VERSION 5.8 ;
BUSBITCHARS "[]" ;
DIVIDERCHAR "/" ;
UNITS
    DATABASE MICRONS 1000 ;
END UNITS

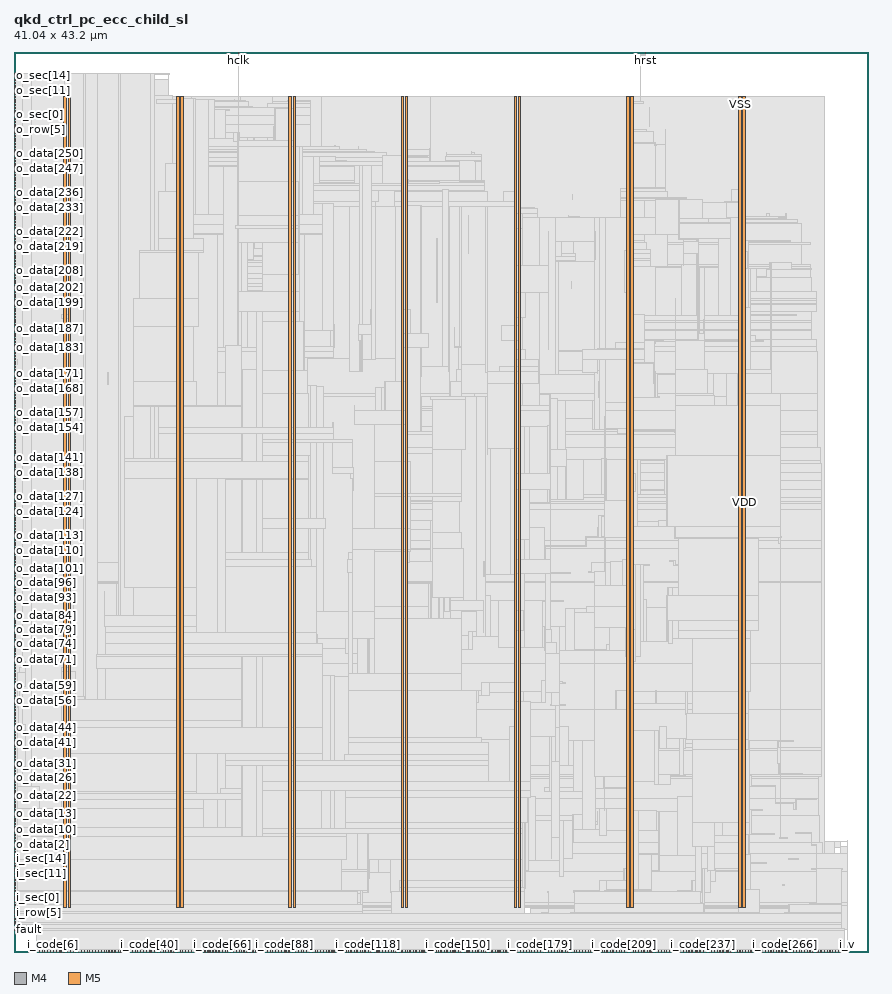
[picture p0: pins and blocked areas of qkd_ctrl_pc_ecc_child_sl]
MACRO qkd_ctrl_pc_ecc_child_sl
  FOREIGN qkd_ctrl_pc_ecc_child_sl 0 0 ;
  CLASS BLOCK ;
  SIZE 41.04 BY 43.2 ;
  PIN fault
    DIRECTION OUTPUT ;
    USE SIGNAL ;
    PORT
      LAYER M4 ;
        RECT  0 1.056 0.084 1.08 ;
    END
  END fault
  PIN hclk
    DIRECTION INPUT ;
    USE SIGNAL ;
    PORT
      LAYER M5 ;
        RECT  10.752 43.116 10.776 43.2 ;
    END
  END hclk
  PIN hrst
    DIRECTION INPUT ;
    USE SIGNAL ;
    PORT
      LAYER M5 ;
        RECT  30.288 43.116 30.312 43.2 ;
    END
  END hrst
  PIN i_code[0]
    DIRECTION INPUT ;
    USE SIGNAL ;
    PORT
      LAYER M5 ;
        RECT  1.056 0 1.08 0.084 ;
    END
  END i_code[0]
  PIN i_code[100]
    DIRECTION INPUT ;
    USE SIGNAL ;
    PORT
      LAYER M5 ;
        RECT  14.544 0 14.568 0.084 ;
    END
  END i_code[100]
  PIN i_code[101]
    DIRECTION INPUT ;
    USE SIGNAL ;
    PORT
      LAYER M5 ;
        RECT  14.688 0 14.712 0.084 ;
    END
  END i_code[101]
  PIN i_code[102]
    DIRECTION INPUT ;
    USE SIGNAL ;
    PORT
      LAYER M5 ;
        RECT  14.832 0 14.856 0.084 ;
    END
  END i_code[102]
  PIN i_code[103]
    DIRECTION INPUT ;
    USE SIGNAL ;
    PORT
      LAYER M5 ;
        RECT  14.976 0 15 0.084 ;
    END
  END i_code[103]
  PIN i_code[104]
    DIRECTION INPUT ;
    USE SIGNAL ;
    PORT
      LAYER M5 ;
        RECT  15.12 0 15.144 0.084 ;
    END
  END i_code[104]
  PIN i_code[105]
    DIRECTION INPUT ;
    USE SIGNAL ;
    PORT
      LAYER M5 ;
        RECT  15.264 0 15.288 0.084 ;
    END
  END i_code[105]
  PIN i_code[106]
    DIRECTION INPUT ;
    USE SIGNAL ;
    PORT
      LAYER M5 ;
        RECT  15.36 0 15.384 0.084 ;
    END
  END i_code[106]
  PIN i_code[107]
    DIRECTION INPUT ;
    USE SIGNAL ;
    PORT
      LAYER M5 ;
        RECT  15.504 0 15.528 0.084 ;
    END
  END i_code[107]
  PIN i_code[108]
    DIRECTION INPUT ;
    USE SIGNAL ;
    PORT
      LAYER M5 ;
        RECT  15.648 0 15.672 0.084 ;
    END
  END i_code[108]
  PIN i_code[109]
    DIRECTION INPUT ;
    USE SIGNAL ;
    PORT
      LAYER M5 ;
        RECT  15.792 0 15.816 0.084 ;
    END
  END i_code[109]
  PIN i_code[10]
    DIRECTION INPUT ;
    USE SIGNAL ;
    PORT
      LAYER M5 ;
        RECT  2.4 0 2.424 0.084 ;
    END
  END i_code[10]
  PIN i_code[110]
    DIRECTION INPUT ;
    USE SIGNAL ;
    PORT
      LAYER M5 ;
        RECT  15.936 0 15.96 0.084 ;
    END
  END i_code[110]
  PIN i_code[111]
    DIRECTION INPUT ;
    USE SIGNAL ;
    PORT
      LAYER M5 ;
        RECT  16.032 0 16.056 0.084 ;
    END
  END i_code[111]
  PIN i_code[112]
    DIRECTION INPUT ;
    USE SIGNAL ;
    PORT
      LAYER M5 ;
        RECT  16.176 0 16.2 0.084 ;
    END
  END i_code[112]
  PIN i_code[113]
    DIRECTION INPUT ;
    USE SIGNAL ;
    PORT
      LAYER M5 ;
        RECT  16.32 0 16.344 0.084 ;
    END
  END i_code[113]
  PIN i_code[114]
    DIRECTION INPUT ;
    USE SIGNAL ;
    PORT
      LAYER M5 ;
        RECT  16.464 0 16.488 0.084 ;
    END
  END i_code[114]
  PIN i_code[115]
    DIRECTION INPUT ;
    USE SIGNAL ;
    PORT
      LAYER M5 ;
        RECT  16.608 0 16.632 0.084 ;
    END
  END i_code[115]
  PIN i_code[116]
    DIRECTION INPUT ;
    USE SIGNAL ;
    PORT
      LAYER M5 ;
        RECT  16.704 0 16.728 0.084 ;
    END
  END i_code[116]
  PIN i_code[117]
    DIRECTION INPUT ;
    USE SIGNAL ;
    PORT
      LAYER M5 ;
        RECT  16.848 0 16.872 0.084 ;
    END
  END i_code[117]
  PIN i_code[118]
    DIRECTION INPUT ;
    USE SIGNAL ;
    PORT
      LAYER M5 ;
        RECT  16.992 0 17.016 0.084 ;
    END
  END i_code[118]
  PIN i_code[119]
    DIRECTION INPUT ;
    USE SIGNAL ;
    PORT
      LAYER M5 ;
        RECT  17.136 0 17.16 0.084 ;
    END
  END i_code[119]
  PIN i_code[11]
    DIRECTION INPUT ;
    USE SIGNAL ;
    PORT
      LAYER M5 ;
        RECT  2.544 0 2.568 0.084 ;
    END
  END i_code[11]
  PIN i_code[120]
    DIRECTION INPUT ;
    USE SIGNAL ;
    PORT
      LAYER M5 ;
        RECT  17.28 0 17.304 0.084 ;
    END
  END i_code[120]
  PIN i_code[121]
    DIRECTION INPUT ;
    USE SIGNAL ;
    PORT
      LAYER M5 ;
        RECT  17.424 0 17.448 0.084 ;
    END
  END i_code[121]
  PIN i_code[122]
    DIRECTION INPUT ;
    USE SIGNAL ;
    PORT
      LAYER M5 ;
        RECT  17.52 0 17.544 0.084 ;
    END
  END i_code[122]
  PIN i_code[123]
    DIRECTION INPUT ;
    USE SIGNAL ;
    PORT
      LAYER M5 ;
        RECT  17.664 0 17.688 0.084 ;
    END
  END i_code[123]
  PIN i_code[124]
    DIRECTION INPUT ;
    USE SIGNAL ;
    PORT
      LAYER M5 ;
        RECT  17.808 0 17.832 0.084 ;
    END
  END i_code[124]
  PIN i_code[125]
    DIRECTION INPUT ;
    USE SIGNAL ;
    PORT
      LAYER M5 ;
        RECT  17.952 0 17.976 0.084 ;
    END
  END i_code[125]
  PIN i_code[126]
    DIRECTION INPUT ;
    USE SIGNAL ;
    PORT
      LAYER M5 ;
        RECT  18.096 0 18.12 0.084 ;
    END
  END i_code[126]
  PIN i_code[127]
    DIRECTION INPUT ;
    USE SIGNAL ;
    PORT
      LAYER M5 ;
        RECT  18.192 0 18.216 0.084 ;
    END
  END i_code[127]
  PIN i_code[128]
    DIRECTION INPUT ;
    USE SIGNAL ;
    PORT
      LAYER M5 ;
        RECT  18.336 0 18.36 0.084 ;
    END
  END i_code[128]
  PIN i_code[129]
    DIRECTION INPUT ;
    USE SIGNAL ;
    PORT
      LAYER M5 ;
        RECT  18.48 0 18.504 0.084 ;
    END
  END i_code[129]
  PIN i_code[12]
    DIRECTION INPUT ;
    USE SIGNAL ;
    PORT
      LAYER M5 ;
        RECT  2.688 0 2.712 0.084 ;
    END
  END i_code[12]
  PIN i_code[130]
    DIRECTION INPUT ;
    USE SIGNAL ;
    PORT
      LAYER M5 ;
        RECT  18.624 0 18.648 0.084 ;
    END
  END i_code[130]
  PIN i_code[131]
    DIRECTION INPUT ;
    USE SIGNAL ;
    PORT
      LAYER M5 ;
        RECT  18.768 0 18.792 0.084 ;
    END
  END i_code[131]
  PIN i_code[132]
    DIRECTION INPUT ;
    USE SIGNAL ;
    PORT
      LAYER M5 ;
        RECT  18.864 0 18.888 0.084 ;
    END
  END i_code[132]
  PIN i_code[133]
    DIRECTION INPUT ;
    USE SIGNAL ;
    PORT
      LAYER M5 ;
        RECT  19.008 0 19.032 0.084 ;
    END
  END i_code[133]
  PIN i_code[134]
    DIRECTION INPUT ;
    USE SIGNAL ;
    PORT
      LAYER M5 ;
        RECT  19.152 0 19.176 0.084 ;
    END
  END i_code[134]
  PIN i_code[135]
    DIRECTION INPUT ;
    USE SIGNAL ;
    PORT
      LAYER M5 ;
        RECT  19.296 0 19.32 0.084 ;
    END
  END i_code[135]
  PIN i_code[136]
    DIRECTION INPUT ;
    USE SIGNAL ;
    PORT
      LAYER M5 ;
        RECT  19.44 0 19.464 0.084 ;
    END
  END i_code[136]
  PIN i_code[137]
    DIRECTION INPUT ;
    USE SIGNAL ;
    PORT
      LAYER M5 ;
        RECT  19.584 0 19.608 0.084 ;
    END
  END i_code[137]
  PIN i_code[138]
    DIRECTION INPUT ;
    USE SIGNAL ;
    PORT
      LAYER M5 ;
        RECT  19.68 0 19.704 0.084 ;
    END
  END i_code[138]
  PIN i_code[139]
    DIRECTION INPUT ;
    USE SIGNAL ;
    PORT
      LAYER M5 ;
        RECT  19.824 0 19.848 0.084 ;
    END
  END i_code[139]
  PIN i_code[13]
    DIRECTION INPUT ;
    USE SIGNAL ;
    PORT
      LAYER M5 ;
        RECT  2.832 0 2.856 0.084 ;
    END
  END i_code[13]
  PIN i_code[140]
    DIRECTION INPUT ;
    USE SIGNAL ;
    PORT
      LAYER M5 ;
        RECT  19.968 0 19.992 0.084 ;
    END
  END i_code[140]
  PIN i_code[141]
    DIRECTION INPUT ;
    USE SIGNAL ;
    PORT
      LAYER M5 ;
        RECT  20.112 0 20.136 0.084 ;
    END
  END i_code[141]
  PIN i_code[142]
    DIRECTION INPUT ;
    USE SIGNAL ;
    PORT
      LAYER M5 ;
        RECT  20.256 0 20.28 0.084 ;
    END
  END i_code[142]
  PIN i_code[143]
    DIRECTION INPUT ;
    USE SIGNAL ;
    PORT
      LAYER M5 ;
        RECT  20.352 0 20.376 0.084 ;
    END
  END i_code[143]
  PIN i_code[144]
    DIRECTION INPUT ;
    USE SIGNAL ;
    PORT
      LAYER M5 ;
        RECT  20.496 0 20.52 0.084 ;
    END
  END i_code[144]
  PIN i_code[145]
    DIRECTION INPUT ;
    USE SIGNAL ;
    PORT
      LAYER M5 ;
        RECT  20.64 0 20.664 0.084 ;
    END
  END i_code[145]
  PIN i_code[146]
    DIRECTION INPUT ;
    USE SIGNAL ;
    PORT
      LAYER M5 ;
        RECT  20.784 0 20.808 0.084 ;
    END
  END i_code[146]
  PIN i_code[147]
    DIRECTION INPUT ;
    USE SIGNAL ;
    PORT
      LAYER M5 ;
        RECT  20.928 0 20.952 0.084 ;
    END
  END i_code[147]
  PIN i_code[148]
    DIRECTION INPUT ;
    USE SIGNAL ;
    PORT
      LAYER M5 ;
        RECT  21.072 0 21.096 0.084 ;
    END
  END i_code[148]
  PIN i_code[149]
    DIRECTION INPUT ;
    USE SIGNAL ;
    PORT
      LAYER M5 ;
        RECT  21.168 0 21.192 0.084 ;
    END
  END i_code[149]
  PIN i_code[14]
    DIRECTION INPUT ;
    USE SIGNAL ;
    PORT
      LAYER M5 ;
        RECT  2.928 0 2.952 0.084 ;
    END
  END i_code[14]
  PIN i_code[150]
    DIRECTION INPUT ;
    USE SIGNAL ;
    PORT
      LAYER M5 ;
        RECT  21.312 0 21.336 0.084 ;
    END
  END i_code[150]
  PIN i_code[151]
    DIRECTION INPUT ;
    USE SIGNAL ;
    PORT
      LAYER M5 ;
        RECT  21.456 0 21.48 0.084 ;
    END
  END i_code[151]
  PIN i_code[152]
    DIRECTION INPUT ;
    USE SIGNAL ;
    PORT
      LAYER M5 ;
        RECT  21.6 0 21.624 0.084 ;
    END
  END i_code[152]
  PIN i_code[153]
    DIRECTION INPUT ;
    USE SIGNAL ;
    PORT
      LAYER M5 ;
        RECT  21.744 0 21.768 0.084 ;
    END
  END i_code[153]
  PIN i_code[154]
    DIRECTION INPUT ;
    USE SIGNAL ;
    PORT
      LAYER M5 ;
        RECT  21.84 0 21.864 0.084 ;
    END
  END i_code[154]
  PIN i_code[155]
    DIRECTION INPUT ;
    USE SIGNAL ;
    PORT
      LAYER M5 ;
        RECT  21.984 0 22.008 0.084 ;
    END
  END i_code[155]
  PIN i_code[156]
    DIRECTION INPUT ;
    USE SIGNAL ;
    PORT
      LAYER M5 ;
        RECT  22.128 0 22.152 0.084 ;
    END
  END i_code[156]
  PIN i_code[157]
    DIRECTION INPUT ;
    USE SIGNAL ;
    PORT
      LAYER M5 ;
        RECT  22.272 0 22.296 0.084 ;
    END
  END i_code[157]
  PIN i_code[158]
    DIRECTION INPUT ;
    USE SIGNAL ;
    PORT
      LAYER M5 ;
        RECT  22.416 0 22.44 0.084 ;
    END
  END i_code[158]
  PIN i_code[159]
    DIRECTION INPUT ;
    USE SIGNAL ;
    PORT
      LAYER M5 ;
        RECT  22.512 0 22.536 0.084 ;
    END
  END i_code[159]
  PIN i_code[15]
    DIRECTION INPUT ;
    USE SIGNAL ;
    PORT
      LAYER M5 ;
        RECT  3.072 0 3.096 0.084 ;
    END
  END i_code[15]
  PIN i_code[160]
    DIRECTION INPUT ;
    USE SIGNAL ;
    PORT
      LAYER M5 ;
        RECT  22.656 0 22.68 0.084 ;
    END
  END i_code[160]
  PIN i_code[161]
    DIRECTION INPUT ;
    USE SIGNAL ;
    PORT
      LAYER M5 ;
        RECT  22.8 0 22.824 0.084 ;
    END
  END i_code[161]
  PIN i_code[162]
    DIRECTION INPUT ;
    USE SIGNAL ;
    PORT
      LAYER M5 ;
        RECT  22.944 0 22.968 0.084 ;
    END
  END i_code[162]
  PIN i_code[163]
    DIRECTION INPUT ;
    USE SIGNAL ;
    PORT
      LAYER M5 ;
        RECT  23.088 0 23.112 0.084 ;
    END
  END i_code[163]
  PIN i_code[164]
    DIRECTION INPUT ;
    USE SIGNAL ;
    PORT
      LAYER M5 ;
        RECT  23.232 0 23.256 0.084 ;
    END
  END i_code[164]
  PIN i_code[165]
    DIRECTION INPUT ;
    USE SIGNAL ;
    PORT
      LAYER M5 ;
        RECT  23.328 0 23.352 0.084 ;
    END
  END i_code[165]
  PIN i_code[166]
    DIRECTION INPUT ;
    USE SIGNAL ;
    PORT
      LAYER M5 ;
        RECT  23.472 0 23.496 0.084 ;
    END
  END i_code[166]
  PIN i_code[167]
    DIRECTION INPUT ;
    USE SIGNAL ;
    PORT
      LAYER M5 ;
        RECT  23.616 0 23.64 0.084 ;
    END
  END i_code[167]
  PIN i_code[168]
    DIRECTION INPUT ;
    USE SIGNAL ;
    PORT
      LAYER M5 ;
        RECT  23.76 0 23.784 0.084 ;
    END
  END i_code[168]
  PIN i_code[169]
    DIRECTION INPUT ;
    USE SIGNAL ;
    PORT
      LAYER M5 ;
        RECT  23.904 0 23.928 0.084 ;
    END
  END i_code[169]
  PIN i_code[16]
    DIRECTION INPUT ;
    USE SIGNAL ;
    PORT
      LAYER M5 ;
        RECT  3.216 0 3.24 0.084 ;
    END
  END i_code[16]
  PIN i_code[170]
    DIRECTION INPUT ;
    USE SIGNAL ;
    PORT
      LAYER M5 ;
        RECT  24 0 24.024 0.084 ;
    END
  END i_code[170]
  PIN i_code[171]
    DIRECTION INPUT ;
    USE SIGNAL ;
    PORT
      LAYER M5 ;
        RECT  24.144 0 24.168 0.084 ;
    END
  END i_code[171]
  PIN i_code[172]
    DIRECTION INPUT ;
    USE SIGNAL ;
    PORT
      LAYER M5 ;
        RECT  24.288 0 24.312 0.084 ;
    END
  END i_code[172]
  PIN i_code[173]
    DIRECTION INPUT ;
    USE SIGNAL ;
    PORT
      LAYER M5 ;
        RECT  24.432 0 24.456 0.084 ;
    END
  END i_code[173]
  PIN i_code[174]
    DIRECTION INPUT ;
    USE SIGNAL ;
    PORT
      LAYER M5 ;
        RECT  24.576 0 24.6 0.084 ;
    END
  END i_code[174]
  PIN i_code[175]
    DIRECTION INPUT ;
    USE SIGNAL ;
    PORT
      LAYER M5 ;
        RECT  24.72 0 24.744 0.084 ;
    END
  END i_code[175]
  PIN i_code[176]
    DIRECTION INPUT ;
    USE SIGNAL ;
    PORT
      LAYER M5 ;
        RECT  24.816 0 24.84 0.084 ;
    END
  END i_code[176]
  PIN i_code[177]
    DIRECTION INPUT ;
    USE SIGNAL ;
    PORT
      LAYER M5 ;
        RECT  24.96 0 24.984 0.084 ;
    END
  END i_code[177]
  PIN i_code[178]
    DIRECTION INPUT ;
    USE SIGNAL ;
    PORT
      LAYER M5 ;
        RECT  25.104 0 25.128 0.084 ;
    END
  END i_code[178]
  PIN i_code[179]
    DIRECTION INPUT ;
    USE SIGNAL ;
    PORT
      LAYER M5 ;
        RECT  25.248 0 25.272 0.084 ;
    END
  END i_code[179]
  PIN i_code[17]
    DIRECTION INPUT ;
    USE SIGNAL ;
    PORT
      LAYER M5 ;
        RECT  3.36 0 3.384 0.084 ;
    END
  END i_code[17]
  PIN i_code[180]
    DIRECTION INPUT ;
    USE SIGNAL ;
    PORT
      LAYER M5 ;
        RECT  25.392 0 25.416 0.084 ;
    END
  END i_code[180]
  PIN i_code[181]
    DIRECTION INPUT ;
    USE SIGNAL ;
    PORT
      LAYER M5 ;
        RECT  25.488 0 25.512 0.084 ;
    END
  END i_code[181]
  PIN i_code[182]
    DIRECTION INPUT ;
    USE SIGNAL ;
    PORT
      LAYER M5 ;
        RECT  25.632 0 25.656 0.084 ;
    END
  END i_code[182]
  PIN i_code[183]
    DIRECTION INPUT ;
    USE SIGNAL ;
    PORT
      LAYER M5 ;
        RECT  25.776 0 25.8 0.084 ;
    END
  END i_code[183]
  PIN i_code[184]
    DIRECTION INPUT ;
    USE SIGNAL ;
    PORT
      LAYER M5 ;
        RECT  25.92 0 25.944 0.084 ;
    END
  END i_code[184]
  PIN i_code[185]
    DIRECTION INPUT ;
    USE SIGNAL ;
    PORT
      LAYER M5 ;
        RECT  26.064 0 26.088 0.084 ;
    END
  END i_code[185]
  PIN i_code[186]
    DIRECTION INPUT ;
    USE SIGNAL ;
    PORT
      LAYER M5 ;
        RECT  26.16 0 26.184 0.084 ;
    END
  END i_code[186]
  PIN i_code[187]
    DIRECTION INPUT ;
    USE SIGNAL ;
    PORT
      LAYER M5 ;
        RECT  26.304 0 26.328 0.084 ;
    END
  END i_code[187]
  PIN i_code[188]
    DIRECTION INPUT ;
    USE SIGNAL ;
    PORT
      LAYER M5 ;
        RECT  26.448 0 26.472 0.084 ;
    END
  END i_code[188]
  PIN i_code[189]
    DIRECTION INPUT ;
    USE SIGNAL ;
    PORT
      LAYER M5 ;
        RECT  26.592 0 26.616 0.084 ;
    END
  END i_code[189]
  PIN i_code[18]
    DIRECTION INPUT ;
    USE SIGNAL ;
    PORT
      LAYER M5 ;
        RECT  3.504 0 3.528 0.084 ;
    END
  END i_code[18]
  PIN i_code[190]
    DIRECTION INPUT ;
    USE SIGNAL ;
    PORT
      LAYER M5 ;
        RECT  26.736 0 26.76 0.084 ;
    END
  END i_code[190]
  PIN i_code[191]
    DIRECTION INPUT ;
    USE SIGNAL ;
    PORT
      LAYER M5 ;
        RECT  26.88 0 26.904 0.084 ;
    END
  END i_code[191]
  PIN i_code[192]
    DIRECTION INPUT ;
    USE SIGNAL ;
    PORT
      LAYER M5 ;
        RECT  26.976 0 27 0.084 ;
    END
  END i_code[192]
  PIN i_code[193]
    DIRECTION INPUT ;
    USE SIGNAL ;
    PORT
      LAYER M5 ;
        RECT  27.12 0 27.144 0.084 ;
    END
  END i_code[193]
  PIN i_code[194]
    DIRECTION INPUT ;
    USE SIGNAL ;
    PORT
      LAYER M5 ;
        RECT  27.264 0 27.288 0.084 ;
    END
  END i_code[194]
  PIN i_code[195]
    DIRECTION INPUT ;
    USE SIGNAL ;
    PORT
      LAYER M5 ;
        RECT  27.408 0 27.432 0.084 ;
    END
  END i_code[195]
  PIN i_code[196]
    DIRECTION INPUT ;
    USE SIGNAL ;
    PORT
      LAYER M5 ;
        RECT  27.552 0 27.576 0.084 ;
    END
  END i_code[196]
  PIN i_code[197]
    DIRECTION INPUT ;
    USE SIGNAL ;
    PORT
      LAYER M5 ;
        RECT  27.648 0 27.672 0.084 ;
    END
  END i_code[197]
  PIN i_code[198]
    DIRECTION INPUT ;
    USE SIGNAL ;
    PORT
      LAYER M5 ;
        RECT  27.792 0 27.816 0.084 ;
    END
  END i_code[198]
  PIN i_code[199]
    DIRECTION INPUT ;
    USE SIGNAL ;
    PORT
      LAYER M5 ;
        RECT  27.936 0 27.96 0.084 ;
    END
  END i_code[199]
  PIN i_code[19]
    DIRECTION INPUT ;
    USE SIGNAL ;
    PORT
      LAYER M5 ;
        RECT  3.6 0 3.624 0.084 ;
    END
  END i_code[19]
  PIN i_code[1]
    DIRECTION INPUT ;
    USE SIGNAL ;
    PORT
      LAYER M5 ;
        RECT  1.2 0 1.224 0.084 ;
    END
  END i_code[1]
  PIN i_code[200]
    DIRECTION INPUT ;
    USE SIGNAL ;
    PORT
      LAYER M5 ;
        RECT  28.08 0 28.104 0.084 ;
    END
  END i_code[200]
  PIN i_code[201]
    DIRECTION INPUT ;
    USE SIGNAL ;
    PORT
      LAYER M5 ;
        RECT  28.224 0 28.248 0.084 ;
    END
  END i_code[201]
  PIN i_code[202]
    DIRECTION INPUT ;
    USE SIGNAL ;
    PORT
      LAYER M5 ;
        RECT  28.32 0 28.344 0.084 ;
    END
  END i_code[202]
  PIN i_code[203]
    DIRECTION INPUT ;
    USE SIGNAL ;
    PORT
      LAYER M5 ;
        RECT  28.464 0 28.488 0.084 ;
    END
  END i_code[203]
  PIN i_code[204]
    DIRECTION INPUT ;
    USE SIGNAL ;
    PORT
      LAYER M5 ;
        RECT  28.608 0 28.632 0.084 ;
    END
  END i_code[204]
  PIN i_code[205]
    DIRECTION INPUT ;
    USE SIGNAL ;
    PORT
      LAYER M5 ;
        RECT  28.752 0 28.776 0.084 ;
    END
  END i_code[205]
  PIN i_code[206]
    DIRECTION INPUT ;
    USE SIGNAL ;
    PORT
      LAYER M5 ;
        RECT  28.896 0 28.92 0.084 ;
    END
  END i_code[206]
  PIN i_code[207]
    DIRECTION INPUT ;
    USE SIGNAL ;
    PORT
      LAYER M5 ;
        RECT  29.04 0 29.064 0.084 ;
    END
  END i_code[207]
  PIN i_code[208]
    DIRECTION INPUT ;
    USE SIGNAL ;
    PORT
      LAYER M5 ;
        RECT  29.136 0 29.16 0.084 ;
    END
  END i_code[208]
  PIN i_code[209]
    DIRECTION INPUT ;
    USE SIGNAL ;
    PORT
      LAYER M5 ;
        RECT  29.28 0 29.304 0.084 ;
    END
  END i_code[209]
  PIN i_code[20]
    DIRECTION INPUT ;
    USE SIGNAL ;
    PORT
      LAYER M5 ;
        RECT  3.744 0 3.768 0.084 ;
    END
  END i_code[20]
  PIN i_code[210]
    DIRECTION INPUT ;
    USE SIGNAL ;
    PORT
      LAYER M5 ;
        RECT  29.424 0 29.448 0.084 ;
    END
  END i_code[210]
  PIN i_code[211]
    DIRECTION INPUT ;
    USE SIGNAL ;
    PORT
      LAYER M5 ;
        RECT  29.568 0 29.592 0.084 ;
    END
  END i_code[211]
  PIN i_code[212]
    DIRECTION INPUT ;
    USE SIGNAL ;
    PORT
      LAYER M5 ;
        RECT  29.712 0 29.736 0.084 ;
    END
  END i_code[212]
  PIN i_code[213]
    DIRECTION INPUT ;
    USE SIGNAL ;
    PORT
      LAYER M5 ;
        RECT  29.808 0 29.832 0.084 ;
    END
  END i_code[213]
  PIN i_code[214]
    DIRECTION INPUT ;
    USE SIGNAL ;
    PORT
      LAYER M5 ;
        RECT  29.952 0 29.976 0.084 ;
    END
  END i_code[214]
  PIN i_code[215]
    DIRECTION INPUT ;
    USE SIGNAL ;
    PORT
      LAYER M5 ;
        RECT  30.096 0 30.12 0.084 ;
    END
  END i_code[215]
  PIN i_code[216]
    DIRECTION INPUT ;
    USE SIGNAL ;
    PORT
      LAYER M5 ;
        RECT  30.24 0 30.264 0.084 ;
    END
  END i_code[216]
  PIN i_code[217]
    DIRECTION INPUT ;
    USE SIGNAL ;
    PORT
      LAYER M5 ;
        RECT  30.384 0 30.408 0.084 ;
    END
  END i_code[217]
  PIN i_code[218]
    DIRECTION INPUT ;
    USE SIGNAL ;
    PORT
      LAYER M5 ;
        RECT  30.528 0 30.552 0.084 ;
    END
  END i_code[218]
  PIN i_code[219]
    DIRECTION INPUT ;
    USE SIGNAL ;
    PORT
      LAYER M5 ;
        RECT  30.624 0 30.648 0.084 ;
    END
  END i_code[219]
  PIN i_code[21]
    DIRECTION INPUT ;
    USE SIGNAL ;
    PORT
      LAYER M5 ;
        RECT  3.888 0 3.912 0.084 ;
    END
  END i_code[21]
  PIN i_code[220]
    DIRECTION INPUT ;
    USE SIGNAL ;
    PORT
      LAYER M5 ;
        RECT  30.768 0 30.792 0.084 ;
    END
  END i_code[220]
  PIN i_code[221]
    DIRECTION INPUT ;
    USE SIGNAL ;
    PORT
      LAYER M5 ;
        RECT  30.912 0 30.936 0.084 ;
    END
  END i_code[221]
  PIN i_code[222]
    DIRECTION INPUT ;
    USE SIGNAL ;
    PORT
      LAYER M5 ;
        RECT  31.056 0 31.08 0.084 ;
    END
  END i_code[222]
  PIN i_code[223]
    DIRECTION INPUT ;
    USE SIGNAL ;
    PORT
      LAYER M5 ;
        RECT  31.2 0 31.224 0.084 ;
    END
  END i_code[223]
  PIN i_code[224]
    DIRECTION INPUT ;
    USE SIGNAL ;
    PORT
      LAYER M5 ;
        RECT  31.296 0 31.32 0.084 ;
    END
  END i_code[224]
  PIN i_code[225]
    DIRECTION INPUT ;
    USE SIGNAL ;
    PORT
      LAYER M5 ;
        RECT  31.44 0 31.464 0.084 ;
    END
  END i_code[225]
  PIN i_code[226]
    DIRECTION INPUT ;
    USE SIGNAL ;
    PORT
      LAYER M5 ;
        RECT  31.584 0 31.608 0.084 ;
    END
  END i_code[226]
  PIN i_code[227]
    DIRECTION INPUT ;
    USE SIGNAL ;
    PORT
      LAYER M5 ;
        RECT  31.728 0 31.752 0.084 ;
    END
  END i_code[227]
  PIN i_code[228]
    DIRECTION INPUT ;
    USE SIGNAL ;
    PORT
      LAYER M5 ;
        RECT  31.872 0 31.896 0.084 ;
    END
  END i_code[228]
  PIN i_code[229]
    DIRECTION INPUT ;
    USE SIGNAL ;
    PORT
      LAYER M5 ;
        RECT  31.968 0 31.992 0.084 ;
    END
  END i_code[229]
  PIN i_code[22]
    DIRECTION INPUT ;
    USE SIGNAL ;
    PORT
      LAYER M5 ;
        RECT  4.032 0 4.056 0.084 ;
    END
  END i_code[22]
  PIN i_code[230]
    DIRECTION INPUT ;
    USE SIGNAL ;
    PORT
      LAYER M5 ;
        RECT  32.112 0 32.136 0.084 ;
    END
  END i_code[230]
  PIN i_code[231]
    DIRECTION INPUT ;
    USE SIGNAL ;
    PORT
      LAYER M5 ;
        RECT  32.256 0 32.28 0.084 ;
    END
  END i_code[231]
  PIN i_code[232]
    DIRECTION INPUT ;
    USE SIGNAL ;
    PORT
      LAYER M5 ;
        RECT  32.4 0 32.424 0.084 ;
    END
  END i_code[232]
  PIN i_code[233]
    DIRECTION INPUT ;
    USE SIGNAL ;
    PORT
      LAYER M5 ;
        RECT  32.544 0 32.568 0.084 ;
    END
  END i_code[233]
  PIN i_code[234]
    DIRECTION INPUT ;
    USE SIGNAL ;
    PORT
      LAYER M5 ;
        RECT  32.688 0 32.712 0.084 ;
    END
  END i_code[234]
  PIN i_code[235]
    DIRECTION INPUT ;
    USE SIGNAL ;
    PORT
      LAYER M5 ;
        RECT  32.784 0 32.808 0.084 ;
    END
  END i_code[235]
  PIN i_code[236]
    DIRECTION INPUT ;
    USE SIGNAL ;
    PORT
      LAYER M5 ;
        RECT  32.928 0 32.952 0.084 ;
    END
  END i_code[236]
  PIN i_code[237]
    DIRECTION INPUT ;
    USE SIGNAL ;
    PORT
      LAYER M5 ;
        RECT  33.072 0 33.096 0.084 ;
    END
  END i_code[237]
  PIN i_code[238]
    DIRECTION INPUT ;
    USE SIGNAL ;
    PORT
      LAYER M5 ;
        RECT  33.216 0 33.24 0.084 ;
    END
  END i_code[238]
  PIN i_code[239]
    DIRECTION INPUT ;
    USE SIGNAL ;
    PORT
      LAYER M5 ;
        RECT  33.36 0 33.384 0.084 ;
    END
  END i_code[239]
  PIN i_code[23]
    DIRECTION INPUT ;
    USE SIGNAL ;
    PORT
      LAYER M5 ;
        RECT  4.176 0 4.2 0.084 ;
    END
  END i_code[23]
  PIN i_code[240]
    DIRECTION INPUT ;
    USE SIGNAL ;
    PORT
      LAYER M5 ;
        RECT  33.456 0 33.48 0.084 ;
    END
  END i_code[240]
  PIN i_code[241]
    DIRECTION INPUT ;
    USE SIGNAL ;
    PORT
      LAYER M5 ;
        RECT  33.6 0 33.624 0.084 ;
    END
  END i_code[241]
  PIN i_code[242]
    DIRECTION INPUT ;
    USE SIGNAL ;
    PORT
      LAYER M5 ;
        RECT  33.744 0 33.768 0.084 ;
    END
  END i_code[242]
  PIN i_code[243]
    DIRECTION INPUT ;
    USE SIGNAL ;
    PORT
      LAYER M5 ;
        RECT  33.888 0 33.912 0.084 ;
    END
  END i_code[243]
  PIN i_code[244]
    DIRECTION INPUT ;
    USE SIGNAL ;
    PORT
      LAYER M5 ;
        RECT  34.032 0 34.056 0.084 ;
    END
  END i_code[244]
  PIN i_code[245]
    DIRECTION INPUT ;
    USE SIGNAL ;
    PORT
      LAYER M5 ;
        RECT  34.176 0 34.2 0.084 ;
    END
  END i_code[245]
  PIN i_code[246]
    DIRECTION INPUT ;
    USE SIGNAL ;
    PORT
      LAYER M5 ;
        RECT  34.272 0 34.296 0.084 ;
    END
  END i_code[246]
  PIN i_code[247]
    DIRECTION INPUT ;
    USE SIGNAL ;
    PORT
      LAYER M5 ;
        RECT  34.416 0 34.44 0.084 ;
    END
  END i_code[247]
  PIN i_code[248]
    DIRECTION INPUT ;
    USE SIGNAL ;
    PORT
      LAYER M5 ;
        RECT  34.56 0 34.584 0.084 ;
    END
  END i_code[248]
  PIN i_code[249]
    DIRECTION INPUT ;
    USE SIGNAL ;
    PORT
      LAYER M5 ;
        RECT  34.704 0 34.728 0.084 ;
    END
  END i_code[249]
  PIN i_code[24]
    DIRECTION INPUT ;
    USE SIGNAL ;
    PORT
      LAYER M5 ;
        RECT  4.32 0 4.344 0.084 ;
    END
  END i_code[24]
  PIN i_code[250]
    DIRECTION INPUT ;
    USE SIGNAL ;
    PORT
      LAYER M5 ;
        RECT  34.848 0 34.872 0.084 ;
    END
  END i_code[250]
  PIN i_code[251]
    DIRECTION INPUT ;
    USE SIGNAL ;
    PORT
      LAYER M5 ;
        RECT  34.944 0 34.968 0.084 ;
    END
  END i_code[251]
  PIN i_code[252]
    DIRECTION INPUT ;
    USE SIGNAL ;
    PORT
      LAYER M5 ;
        RECT  35.088 0 35.112 0.084 ;
    END
  END i_code[252]
  PIN i_code[253]
    DIRECTION INPUT ;
    USE SIGNAL ;
    PORT
      LAYER M5 ;
        RECT  35.232 0 35.256 0.084 ;
    END
  END i_code[253]
  PIN i_code[254]
    DIRECTION INPUT ;
    USE SIGNAL ;
    PORT
      LAYER M5 ;
        RECT  35.376 0 35.4 0.084 ;
    END
  END i_code[254]
  PIN i_code[255]
    DIRECTION INPUT ;
    USE SIGNAL ;
    PORT
      LAYER M5 ;
        RECT  35.52 0 35.544 0.084 ;
    END
  END i_code[255]
  PIN i_code[256]
    DIRECTION INPUT ;
    USE SIGNAL ;
    PORT
      LAYER M5 ;
        RECT  35.616 0 35.64 0.084 ;
    END
  END i_code[256]
  PIN i_code[257]
    DIRECTION INPUT ;
    USE SIGNAL ;
    PORT
      LAYER M5 ;
        RECT  35.76 0 35.784 0.084 ;
    END
  END i_code[257]
  PIN i_code[258]
    DIRECTION INPUT ;
    USE SIGNAL ;
    PORT
      LAYER M5 ;
        RECT  35.904 0 35.928 0.084 ;
    END
  END i_code[258]
  PIN i_code[259]
    DIRECTION INPUT ;
    USE SIGNAL ;
    PORT
      LAYER M5 ;
        RECT  36.048 0 36.072 0.084 ;
    END
  END i_code[259]
  PIN i_code[25]
    DIRECTION INPUT ;
    USE SIGNAL ;
    PORT
      LAYER M5 ;
        RECT  4.416 0 4.44 0.084 ;
    END
  END i_code[25]
  PIN i_code[260]
    DIRECTION INPUT ;
    USE SIGNAL ;
    PORT
      LAYER M5 ;
        RECT  36.192 0 36.216 0.084 ;
    END
  END i_code[260]
  PIN i_code[261]
    DIRECTION INPUT ;
    USE SIGNAL ;
    PORT
      LAYER M5 ;
        RECT  36.336 0 36.36 0.084 ;
    END
  END i_code[261]
  PIN i_code[262]
    DIRECTION INPUT ;
    USE SIGNAL ;
    PORT
      LAYER M5 ;
        RECT  36.432 0 36.456 0.084 ;
    END
  END i_code[262]
  PIN i_code[263]
    DIRECTION INPUT ;
    USE SIGNAL ;
    PORT
      LAYER M5 ;
        RECT  36.576 0 36.6 0.084 ;
    END
  END i_code[263]
  PIN i_code[264]
    DIRECTION INPUT ;
    USE SIGNAL ;
    PORT
      LAYER M5 ;
        RECT  36.72 0 36.744 0.084 ;
    END
  END i_code[264]
  PIN i_code[265]
    DIRECTION INPUT ;
    USE SIGNAL ;
    PORT
      LAYER M5 ;
        RECT  36.864 0 36.888 0.084 ;
    END
  END i_code[265]
  PIN i_code[266]
    DIRECTION INPUT ;
    USE SIGNAL ;
    PORT
      LAYER M5 ;
        RECT  37.008 0 37.032 0.084 ;
    END
  END i_code[266]
  PIN i_code[267]
    DIRECTION INPUT ;
    USE SIGNAL ;
    PORT
      LAYER M5 ;
        RECT  37.104 0 37.128 0.084 ;
    END
  END i_code[267]
  PIN i_code[268]
    DIRECTION INPUT ;
    USE SIGNAL ;
    PORT
      LAYER M5 ;
        RECT  37.248 0 37.272 0.084 ;
    END
  END i_code[268]
  PIN i_code[269]
    DIRECTION INPUT ;
    USE SIGNAL ;
    PORT
      LAYER M5 ;
        RECT  37.392 0 37.416 0.084 ;
    END
  END i_code[269]
  PIN i_code[26]
    DIRECTION INPUT ;
    USE SIGNAL ;
    PORT
      LAYER M5 ;
        RECT  4.56 0 4.584 0.084 ;
    END
  END i_code[26]
  PIN i_code[270]
    DIRECTION INPUT ;
    USE SIGNAL ;
    PORT
      LAYER M5 ;
        RECT  37.536 0 37.56 0.084 ;
    END
  END i_code[270]
  PIN i_code[271]
    DIRECTION INPUT ;
    USE SIGNAL ;
    PORT
      LAYER M5 ;
        RECT  37.68 0 37.704 0.084 ;
    END
  END i_code[271]
  PIN i_code[272]
    DIRECTION INPUT ;
    USE SIGNAL ;
    PORT
      LAYER M5 ;
        RECT  37.776 0 37.8 0.084 ;
    END
  END i_code[272]
  PIN i_code[273]
    DIRECTION INPUT ;
    USE SIGNAL ;
    PORT
      LAYER M5 ;
        RECT  37.92 0 37.944 0.084 ;
    END
  END i_code[273]
  PIN i_code[274]
    DIRECTION INPUT ;
    USE SIGNAL ;
    PORT
      LAYER M5 ;
        RECT  38.064 0 38.088 0.084 ;
    END
  END i_code[274]
  PIN i_code[275]
    DIRECTION INPUT ;
    USE SIGNAL ;
    PORT
      LAYER M5 ;
        RECT  38.208 0 38.232 0.084 ;
    END
  END i_code[275]
  PIN i_code[276]
    DIRECTION INPUT ;
    USE SIGNAL ;
    PORT
      LAYER M5 ;
        RECT  38.352 0 38.376 0.084 ;
    END
  END i_code[276]
  PIN i_code[277]
    DIRECTION INPUT ;
    USE SIGNAL ;
    PORT
      LAYER M5 ;
        RECT  38.496 0 38.52 0.084 ;
    END
  END i_code[277]
  PIN i_code[278]
    DIRECTION INPUT ;
    USE SIGNAL ;
    PORT
      LAYER M5 ;
        RECT  38.592 0 38.616 0.084 ;
    END
  END i_code[278]
  PIN i_code[279]
    DIRECTION INPUT ;
    USE SIGNAL ;
    PORT
      LAYER M5 ;
        RECT  38.736 0 38.76 0.084 ;
    END
  END i_code[279]
  PIN i_code[27]
    DIRECTION INPUT ;
    USE SIGNAL ;
    PORT
      LAYER M5 ;
        RECT  4.704 0 4.728 0.084 ;
    END
  END i_code[27]
  PIN i_code[280]
    DIRECTION INPUT ;
    USE SIGNAL ;
    PORT
      LAYER M5 ;
        RECT  38.88 0 38.904 0.084 ;
    END
  END i_code[280]
  PIN i_code[281]
    DIRECTION INPUT ;
    USE SIGNAL ;
    PORT
      LAYER M5 ;
        RECT  39.024 0 39.048 0.084 ;
    END
  END i_code[281]
  PIN i_code[282]
    DIRECTION INPUT ;
    USE SIGNAL ;
    PORT
      LAYER M5 ;
        RECT  39.168 0 39.192 0.084 ;
    END
  END i_code[282]
  PIN i_code[283]
    DIRECTION INPUT ;
    USE SIGNAL ;
    PORT
      LAYER M5 ;
        RECT  39.264 0 39.288 0.084 ;
    END
  END i_code[283]
  PIN i_code[284]
    DIRECTION INPUT ;
    USE SIGNAL ;
    PORT
      LAYER M5 ;
        RECT  39.408 0 39.432 0.084 ;
    END
  END i_code[284]
  PIN i_code[285]
    DIRECTION INPUT ;
    USE SIGNAL ;
    PORT
      LAYER M5 ;
        RECT  39.552 0 39.576 0.084 ;
    END
  END i_code[285]
  PIN i_code[286]
    DIRECTION INPUT ;
    USE SIGNAL ;
    PORT
      LAYER M5 ;
        RECT  39.696 0 39.72 0.084 ;
    END
  END i_code[286]
  PIN i_code[287]
    DIRECTION INPUT ;
    USE SIGNAL ;
    PORT
      LAYER M5 ;
        RECT  39.84 0 39.864 0.084 ;
    END
  END i_code[287]
  PIN i_code[28]
    DIRECTION INPUT ;
    USE SIGNAL ;
    PORT
      LAYER M5 ;
        RECT  4.848 0 4.872 0.084 ;
    END
  END i_code[28]
  PIN i_code[29]
    DIRECTION INPUT ;
    USE SIGNAL ;
    PORT
      LAYER M5 ;
        RECT  4.992 0 5.016 0.084 ;
    END
  END i_code[29]
  PIN i_code[2]
    DIRECTION INPUT ;
    USE SIGNAL ;
    PORT
      LAYER M5 ;
        RECT  1.344 0 1.368 0.084 ;
    END
  END i_code[2]
  PIN i_code[30]
    DIRECTION INPUT ;
    USE SIGNAL ;
    PORT
      LAYER M5 ;
        RECT  5.088 0 5.112 0.084 ;
    END
  END i_code[30]
  PIN i_code[31]
    DIRECTION INPUT ;
    USE SIGNAL ;
    PORT
      LAYER M5 ;
        RECT  5.232 0 5.256 0.084 ;
    END
  END i_code[31]
  PIN i_code[32]
    DIRECTION INPUT ;
    USE SIGNAL ;
    PORT
      LAYER M5 ;
        RECT  5.376 0 5.4 0.084 ;
    END
  END i_code[32]
  PIN i_code[33]
    DIRECTION INPUT ;
    USE SIGNAL ;
    PORT
      LAYER M5 ;
        RECT  5.52 0 5.544 0.084 ;
    END
  END i_code[33]
  PIN i_code[34]
    DIRECTION INPUT ;
    USE SIGNAL ;
    PORT
      LAYER M5 ;
        RECT  5.664 0 5.688 0.084 ;
    END
  END i_code[34]
  PIN i_code[35]
    DIRECTION INPUT ;
    USE SIGNAL ;
    PORT
      LAYER M5 ;
        RECT  5.808 0 5.832 0.084 ;
    END
  END i_code[35]
  PIN i_code[36]
    DIRECTION INPUT ;
    USE SIGNAL ;
    PORT
      LAYER M5 ;
        RECT  5.904 0 5.928 0.084 ;
    END
  END i_code[36]
  PIN i_code[37]
    DIRECTION INPUT ;
    USE SIGNAL ;
    PORT
      LAYER M5 ;
        RECT  6.048 0 6.072 0.084 ;
    END
  END i_code[37]
  PIN i_code[38]
    DIRECTION INPUT ;
    USE SIGNAL ;
    PORT
      LAYER M5 ;
        RECT  6.192 0 6.216 0.084 ;
    END
  END i_code[38]
  PIN i_code[39]
    DIRECTION INPUT ;
    USE SIGNAL ;
    PORT
      LAYER M5 ;
        RECT  6.336 0 6.36 0.084 ;
    END
  END i_code[39]
  PIN i_code[3]
    DIRECTION INPUT ;
    USE SIGNAL ;
    PORT
      LAYER M5 ;
        RECT  1.44 0 1.464 0.084 ;
    END
  END i_code[3]
  PIN i_code[40]
    DIRECTION INPUT ;
    USE SIGNAL ;
    PORT
      LAYER M5 ;
        RECT  6.48 0 6.504 0.084 ;
    END
  END i_code[40]
  PIN i_code[41]
    DIRECTION INPUT ;
    USE SIGNAL ;
    PORT
      LAYER M5 ;
        RECT  6.576 0 6.6 0.084 ;
    END
  END i_code[41]
  PIN i_code[42]
    DIRECTION INPUT ;
    USE SIGNAL ;
    PORT
      LAYER M5 ;
        RECT  6.72 0 6.744 0.084 ;
    END
  END i_code[42]
  PIN i_code[43]
    DIRECTION INPUT ;
    USE SIGNAL ;
    PORT
      LAYER M5 ;
        RECT  6.864 0 6.888 0.084 ;
    END
  END i_code[43]
  PIN i_code[44]
    DIRECTION INPUT ;
    USE SIGNAL ;
    PORT
      LAYER M5 ;
        RECT  7.008 0 7.032 0.084 ;
    END
  END i_code[44]
  PIN i_code[45]
    DIRECTION INPUT ;
    USE SIGNAL ;
    PORT
      LAYER M5 ;
        RECT  7.152 0 7.176 0.084 ;
    END
  END i_code[45]
  PIN i_code[46]
    DIRECTION INPUT ;
    USE SIGNAL ;
    PORT
      LAYER M5 ;
        RECT  7.248 0 7.272 0.084 ;
    END
  END i_code[46]
  PIN i_code[47]
    DIRECTION INPUT ;
    USE SIGNAL ;
    PORT
      LAYER M5 ;
        RECT  7.392 0 7.416 0.084 ;
    END
  END i_code[47]
  PIN i_code[48]
    DIRECTION INPUT ;
    USE SIGNAL ;
    PORT
      LAYER M5 ;
        RECT  7.536 0 7.56 0.084 ;
    END
  END i_code[48]
  PIN i_code[49]
    DIRECTION INPUT ;
    USE SIGNAL ;
    PORT
      LAYER M5 ;
        RECT  7.68 0 7.704 0.084 ;
    END
  END i_code[49]
  PIN i_code[4]
    DIRECTION INPUT ;
    USE SIGNAL ;
    PORT
      LAYER M5 ;
        RECT  1.584 0 1.608 0.084 ;
    END
  END i_code[4]
  PIN i_code[50]
    DIRECTION INPUT ;
    USE SIGNAL ;
    PORT
      LAYER M5 ;
        RECT  7.824 0 7.848 0.084 ;
    END
  END i_code[50]
  PIN i_code[51]
    DIRECTION INPUT ;
    USE SIGNAL ;
    PORT
      LAYER M5 ;
        RECT  7.968 0 7.992 0.084 ;
    END
  END i_code[51]
  PIN i_code[52]
    DIRECTION INPUT ;
    USE SIGNAL ;
    PORT
      LAYER M5 ;
        RECT  8.064 0 8.088 0.084 ;
    END
  END i_code[52]
  PIN i_code[53]
    DIRECTION INPUT ;
    USE SIGNAL ;
    PORT
      LAYER M5 ;
        RECT  8.208 0 8.232 0.084 ;
    END
  END i_code[53]
  PIN i_code[54]
    DIRECTION INPUT ;
    USE SIGNAL ;
    PORT
      LAYER M5 ;
        RECT  8.352 0 8.376 0.084 ;
    END
  END i_code[54]
  PIN i_code[55]
    DIRECTION INPUT ;
    USE SIGNAL ;
    PORT
      LAYER M5 ;
        RECT  8.496 0 8.52 0.084 ;
    END
  END i_code[55]
  PIN i_code[56]
    DIRECTION INPUT ;
    USE SIGNAL ;
    PORT
      LAYER M5 ;
        RECT  8.64 0 8.664 0.084 ;
    END
  END i_code[56]
  PIN i_code[57]
    DIRECTION INPUT ;
    USE SIGNAL ;
    PORT
      LAYER M5 ;
        RECT  8.736 0 8.76 0.084 ;
    END
  END i_code[57]
  PIN i_code[58]
    DIRECTION INPUT ;
    USE SIGNAL ;
    PORT
      LAYER M5 ;
        RECT  8.88 0 8.904 0.084 ;
    END
  END i_code[58]
  PIN i_code[59]
    DIRECTION INPUT ;
    USE SIGNAL ;
    PORT
      LAYER M5 ;
        RECT  9.024 0 9.048 0.084 ;
    END
  END i_code[59]
  PIN i_code[5]
    DIRECTION INPUT ;
    USE SIGNAL ;
    PORT
      LAYER M5 ;
        RECT  1.728 0 1.752 0.084 ;
    END
  END i_code[5]
  PIN i_code[60]
    DIRECTION INPUT ;
    USE SIGNAL ;
    PORT
      LAYER M5 ;
        RECT  9.168 0 9.192 0.084 ;
    END
  END i_code[60]
  PIN i_code[61]
    DIRECTION INPUT ;
    USE SIGNAL ;
    PORT
      LAYER M5 ;
        RECT  9.312 0 9.336 0.084 ;
    END
  END i_code[61]
  PIN i_code[62]
    DIRECTION INPUT ;
    USE SIGNAL ;
    PORT
      LAYER M5 ;
        RECT  9.408 0 9.432 0.084 ;
    END
  END i_code[62]
  PIN i_code[63]
    DIRECTION INPUT ;
    USE SIGNAL ;
    PORT
      LAYER M5 ;
        RECT  9.552 0 9.576 0.084 ;
    END
  END i_code[63]
  PIN i_code[64]
    DIRECTION INPUT ;
    USE SIGNAL ;
    PORT
      LAYER M5 ;
        RECT  9.696 0 9.72 0.084 ;
    END
  END i_code[64]
  PIN i_code[65]
    DIRECTION INPUT ;
    USE SIGNAL ;
    PORT
      LAYER M5 ;
        RECT  9.84 0 9.864 0.084 ;
    END
  END i_code[65]
  PIN i_code[66]
    DIRECTION INPUT ;
    USE SIGNAL ;
    PORT
      LAYER M5 ;
        RECT  9.984 0 10.008 0.084 ;
    END
  END i_code[66]
  PIN i_code[67]
    DIRECTION INPUT ;
    USE SIGNAL ;
    PORT
      LAYER M5 ;
        RECT  10.128 0 10.152 0.084 ;
    END
  END i_code[67]
  PIN i_code[68]
    DIRECTION INPUT ;
    USE SIGNAL ;
    PORT
      LAYER M5 ;
        RECT  10.224 0 10.248 0.084 ;
    END
  END i_code[68]
  PIN i_code[69]
    DIRECTION INPUT ;
    USE SIGNAL ;
    PORT
      LAYER M5 ;
        RECT  10.368 0 10.392 0.084 ;
    END
  END i_code[69]
  PIN i_code[6]
    DIRECTION INPUT ;
    USE SIGNAL ;
    PORT
      LAYER M5 ;
        RECT  1.872 0 1.896 0.084 ;
    END
  END i_code[6]
  PIN i_code[70]
    DIRECTION INPUT ;
    USE SIGNAL ;
    PORT
      LAYER M5 ;
        RECT  10.512 0 10.536 0.084 ;
    END
  END i_code[70]
  PIN i_code[71]
    DIRECTION INPUT ;
    USE SIGNAL ;
    PORT
      LAYER M5 ;
        RECT  10.656 0 10.68 0.084 ;
    END
  END i_code[71]
  PIN i_code[72]
    DIRECTION INPUT ;
    USE SIGNAL ;
    PORT
      LAYER M5 ;
        RECT  10.8 0 10.824 0.084 ;
    END
  END i_code[72]
  PIN i_code[73]
    DIRECTION INPUT ;
    USE SIGNAL ;
    PORT
      LAYER M5 ;
        RECT  10.896 0 10.92 0.084 ;
    END
  END i_code[73]
  PIN i_code[74]
    DIRECTION INPUT ;
    USE SIGNAL ;
    PORT
      LAYER M5 ;
        RECT  11.04 0 11.064 0.084 ;
    END
  END i_code[74]
  PIN i_code[75]
    DIRECTION INPUT ;
    USE SIGNAL ;
    PORT
      LAYER M5 ;
        RECT  11.184 0 11.208 0.084 ;
    END
  END i_code[75]
  PIN i_code[76]
    DIRECTION INPUT ;
    USE SIGNAL ;
    PORT
      LAYER M5 ;
        RECT  11.328 0 11.352 0.084 ;
    END
  END i_code[76]
  PIN i_code[77]
    DIRECTION INPUT ;
    USE SIGNAL ;
    PORT
      LAYER M5 ;
        RECT  11.472 0 11.496 0.084 ;
    END
  END i_code[77]
  PIN i_code[78]
    DIRECTION INPUT ;
    USE SIGNAL ;
    PORT
      LAYER M5 ;
        RECT  11.616 0 11.64 0.084 ;
    END
  END i_code[78]
  PIN i_code[79]
    DIRECTION INPUT ;
    USE SIGNAL ;
    PORT
      LAYER M5 ;
        RECT  11.712 0 11.736 0.084 ;
    END
  END i_code[79]
  PIN i_code[7]
    DIRECTION INPUT ;
    USE SIGNAL ;
    PORT
      LAYER M5 ;
        RECT  2.016 0 2.04 0.084 ;
    END
  END i_code[7]
  PIN i_code[80]
    DIRECTION INPUT ;
    USE SIGNAL ;
    PORT
      LAYER M5 ;
        RECT  11.856 0 11.88 0.084 ;
    END
  END i_code[80]
  PIN i_code[81]
    DIRECTION INPUT ;
    USE SIGNAL ;
    PORT
      LAYER M5 ;
        RECT  12 0 12.024 0.084 ;
    END
  END i_code[81]
  PIN i_code[82]
    DIRECTION INPUT ;
    USE SIGNAL ;
    PORT
      LAYER M5 ;
        RECT  12.144 0 12.168 0.084 ;
    END
  END i_code[82]
  PIN i_code[83]
    DIRECTION INPUT ;
    USE SIGNAL ;
    PORT
      LAYER M5 ;
        RECT  12.288 0 12.312 0.084 ;
    END
  END i_code[83]
  PIN i_code[84]
    DIRECTION INPUT ;
    USE SIGNAL ;
    PORT
      LAYER M5 ;
        RECT  12.384 0 12.408 0.084 ;
    END
  END i_code[84]
  PIN i_code[85]
    DIRECTION INPUT ;
    USE SIGNAL ;
    PORT
      LAYER M5 ;
        RECT  12.528 0 12.552 0.084 ;
    END
  END i_code[85]
  PIN i_code[86]
    DIRECTION INPUT ;
    USE SIGNAL ;
    PORT
      LAYER M5 ;
        RECT  12.672 0 12.696 0.084 ;
    END
  END i_code[86]
  PIN i_code[87]
    DIRECTION INPUT ;
    USE SIGNAL ;
    PORT
      LAYER M5 ;
        RECT  12.816 0 12.84 0.084 ;
    END
  END i_code[87]
  PIN i_code[88]
    DIRECTION INPUT ;
    USE SIGNAL ;
    PORT
      LAYER M5 ;
        RECT  12.96 0 12.984 0.084 ;
    END
  END i_code[88]
  PIN i_code[89]
    DIRECTION INPUT ;
    USE SIGNAL ;
    PORT
      LAYER M5 ;
        RECT  13.056 0 13.08 0.084 ;
    END
  END i_code[89]
  PIN i_code[8]
    DIRECTION INPUT ;
    USE SIGNAL ;
    PORT
      LAYER M5 ;
        RECT  2.16 0 2.184 0.084 ;
    END
  END i_code[8]
  PIN i_code[90]
    DIRECTION INPUT ;
    USE SIGNAL ;
    PORT
      LAYER M5 ;
        RECT  13.2 0 13.224 0.084 ;
    END
  END i_code[90]
  PIN i_code[91]
    DIRECTION INPUT ;
    USE SIGNAL ;
    PORT
      LAYER M5 ;
        RECT  13.344 0 13.368 0.084 ;
    END
  END i_code[91]
  PIN i_code[92]
    DIRECTION INPUT ;
    USE SIGNAL ;
    PORT
      LAYER M5 ;
        RECT  13.488 0 13.512 0.084 ;
    END
  END i_code[92]
  PIN i_code[93]
    DIRECTION INPUT ;
    USE SIGNAL ;
    PORT
      LAYER M5 ;
        RECT  13.632 0 13.656 0.084 ;
    END
  END i_code[93]
  PIN i_code[94]
    DIRECTION INPUT ;
    USE SIGNAL ;
    PORT
      LAYER M5 ;
        RECT  13.776 0 13.8 0.084 ;
    END
  END i_code[94]
  PIN i_code[95]
    DIRECTION INPUT ;
    USE SIGNAL ;
    PORT
      LAYER M5 ;
        RECT  13.872 0 13.896 0.084 ;
    END
  END i_code[95]
  PIN i_code[96]
    DIRECTION INPUT ;
    USE SIGNAL ;
    PORT
      LAYER M5 ;
        RECT  14.016 0 14.04 0.084 ;
    END
  END i_code[96]
  PIN i_code[97]
    DIRECTION INPUT ;
    USE SIGNAL ;
    PORT
      LAYER M5 ;
        RECT  14.16 0 14.184 0.084 ;
    END
  END i_code[97]
  PIN i_code[98]
    DIRECTION INPUT ;
    USE SIGNAL ;
    PORT
      LAYER M5 ;
        RECT  14.304 0 14.328 0.084 ;
    END
  END i_code[98]
  PIN i_code[99]
    DIRECTION INPUT ;
    USE SIGNAL ;
    PORT
      LAYER M5 ;
        RECT  14.448 0 14.472 0.084 ;
    END
  END i_code[99]
  PIN i_code[9]
    DIRECTION INPUT ;
    USE SIGNAL ;
    PORT
      LAYER M5 ;
        RECT  2.256 0 2.28 0.084 ;
    END
  END i_code[9]
  PIN i_row[0]
    DIRECTION INPUT ;
    USE SIGNAL ;
    PORT
      LAYER M4 ;
        RECT  0 1.2 0.084 1.224 ;
    END
  END i_row[0]
  PIN i_row[1]
    DIRECTION INPUT ;
    USE SIGNAL ;
    PORT
      LAYER M4 ;
        RECT  0 1.344 0.084 1.368 ;
    END
  END i_row[1]
  PIN i_row[2]
    DIRECTION INPUT ;
    USE SIGNAL ;
    PORT
      LAYER M4 ;
        RECT  0 1.44 0.084 1.464 ;
    END
  END i_row[2]
  PIN i_row[3]
    DIRECTION INPUT ;
    USE SIGNAL ;
    PORT
      LAYER M4 ;
        RECT  0 1.584 0.084 1.608 ;
    END
  END i_row[3]
  PIN i_row[4]
    DIRECTION INPUT ;
    USE SIGNAL ;
    PORT
      LAYER M4 ;
        RECT  0 1.728 0.084 1.752 ;
    END
  END i_row[4]
  PIN i_row[5]
    DIRECTION INPUT ;
    USE SIGNAL ;
    PORT
      LAYER M4 ;
        RECT  0 1.872 0.084 1.896 ;
    END
  END i_row[5]
  PIN i_row[6]
    DIRECTION INPUT ;
    USE SIGNAL ;
    PORT
      LAYER M4 ;
        RECT  0 1.968 0.084 1.992 ;
    END
  END i_row[6]
  PIN i_row[7]
    DIRECTION INPUT ;
    USE SIGNAL ;
    PORT
      LAYER M4 ;
        RECT  0 2.112 0.084 2.136 ;
    END
  END i_row[7]
  PIN i_sec[0]
    DIRECTION INPUT ;
    USE SIGNAL ;
    PORT
      LAYER M4 ;
        RECT  0 2.256 0.084 2.28 ;
    END
  END i_sec[0]
  PIN i_sec[10]
    DIRECTION INPUT ;
    USE SIGNAL ;
    PORT
      LAYER M4 ;
        RECT  0 3.6 0.084 3.624 ;
    END
  END i_sec[10]
  PIN i_sec[11]
    DIRECTION INPUT ;
    USE SIGNAL ;
    PORT
      LAYER M4 ;
        RECT  0 3.744 0.084 3.768 ;
    END
  END i_sec[11]
  PIN i_sec[12]
    DIRECTION INPUT ;
    USE SIGNAL ;
    PORT
      LAYER M4 ;
        RECT  0 3.888 0.084 3.912 ;
    END
  END i_sec[12]
  PIN i_sec[13]
    DIRECTION INPUT ;
    USE SIGNAL ;
    PORT
      LAYER M4 ;
        RECT  0 3.984 0.084 4.008 ;
    END
  END i_sec[13]
  PIN i_sec[14]
    DIRECTION INPUT ;
    USE SIGNAL ;
    PORT
      LAYER M4 ;
        RECT  0 4.128 0.084 4.152 ;
    END
  END i_sec[14]
  PIN i_sec[15]
    DIRECTION INPUT ;
    USE SIGNAL ;
    PORT
      LAYER M4 ;
        RECT  0 4.272 0.084 4.296 ;
    END
  END i_sec[15]
  PIN i_sec[16]
    DIRECTION INPUT ;
    USE SIGNAL ;
    PORT
      LAYER M4 ;
        RECT  0 4.416 0.084 4.44 ;
    END
  END i_sec[16]
  PIN i_sec[1]
    DIRECTION INPUT ;
    USE SIGNAL ;
    PORT
      LAYER M4 ;
        RECT  0 2.4 0.084 2.424 ;
    END
  END i_sec[1]
  PIN i_sec[2]
    DIRECTION INPUT ;
    USE SIGNAL ;
    PORT
      LAYER M4 ;
        RECT  0 2.544 0.084 2.568 ;
    END
  END i_sec[2]
  PIN i_sec[3]
    DIRECTION INPUT ;
    USE SIGNAL ;
    PORT
      LAYER M4 ;
        RECT  0 2.64 0.084 2.664 ;
    END
  END i_sec[3]
  PIN i_sec[4]
    DIRECTION INPUT ;
    USE SIGNAL ;
    PORT
      LAYER M4 ;
        RECT  0 2.784 0.084 2.808 ;
    END
  END i_sec[4]
  PIN i_sec[5]
    DIRECTION INPUT ;
    USE SIGNAL ;
    PORT
      LAYER M4 ;
        RECT  0 2.928 0.084 2.952 ;
    END
  END i_sec[5]
  PIN i_sec[6]
    DIRECTION INPUT ;
    USE SIGNAL ;
    PORT
      LAYER M4 ;
        RECT  0 3.072 0.084 3.096 ;
    END
  END i_sec[6]
  PIN i_sec[7]
    DIRECTION INPUT ;
    USE SIGNAL ;
    PORT
      LAYER M4 ;
        RECT  0 3.216 0.084 3.24 ;
    END
  END i_sec[7]
  PIN i_sec[8]
    DIRECTION INPUT ;
    USE SIGNAL ;
    PORT
      LAYER M4 ;
        RECT  0 3.312 0.084 3.336 ;
    END
  END i_sec[8]
  PIN i_sec[9]
    DIRECTION INPUT ;
    USE SIGNAL ;
    PORT
      LAYER M4 ;
        RECT  0 3.456 0.084 3.48 ;
    END
  END i_sec[9]
  PIN i_v
    DIRECTION INPUT ;
    USE SIGNAL ;
    PORT
      LAYER M5 ;
        RECT  39.984 0 40.008 0.084 ;
    END
  END i_v
  PIN o_data[0]
    DIRECTION OUTPUT ;
    USE SIGNAL ;
    PORT
      LAYER M4 ;
        RECT  0 4.512 0.084 4.536 ;
    END
  END o_data[0]
  PIN o_data[100]
    DIRECTION OUTPUT ;
    USE SIGNAL ;
    PORT
      LAYER M4 ;
        RECT  0 17.904 0.084 17.928 ;
    END
  END o_data[100]
  PIN o_data[101]
    DIRECTION OUTPUT ;
    USE SIGNAL ;
    PORT
      LAYER M4 ;
        RECT  0 18.048 0.084 18.072 ;
    END
  END o_data[101]
  PIN o_data[102]
    DIRECTION OUTPUT ;
    USE SIGNAL ;
    PORT
      LAYER M4 ;
        RECT  0 18.192 0.084 18.216 ;
    END
  END o_data[102]
  PIN o_data[103]
    DIRECTION OUTPUT ;
    USE SIGNAL ;
    PORT
      LAYER M4 ;
        RECT  0 18.288 0.084 18.312 ;
    END
  END o_data[103]
  PIN o_data[104]
    DIRECTION OUTPUT ;
    USE SIGNAL ;
    PORT
      LAYER M4 ;
        RECT  0 18.432 0.084 18.456 ;
    END
  END o_data[104]
  PIN o_data[105]
    DIRECTION OUTPUT ;
    USE SIGNAL ;
    PORT
      LAYER M4 ;
        RECT  0 18.576 0.084 18.6 ;
    END
  END o_data[105]
  PIN o_data[106]
    DIRECTION OUTPUT ;
    USE SIGNAL ;
    PORT
      LAYER M4 ;
        RECT  0 18.72 0.084 18.744 ;
    END
  END o_data[106]
  PIN o_data[107]
    DIRECTION OUTPUT ;
    USE SIGNAL ;
    PORT
      LAYER M4 ;
        RECT  0 18.864 0.084 18.888 ;
    END
  END o_data[107]
  PIN o_data[108]
    DIRECTION OUTPUT ;
    USE SIGNAL ;
    PORT
      LAYER M4 ;
        RECT  0 18.96 0.084 18.984 ;
    END
  END o_data[108]
  PIN o_data[109]
    DIRECTION OUTPUT ;
    USE SIGNAL ;
    PORT
      LAYER M4 ;
        RECT  0 19.104 0.084 19.128 ;
    END
  END o_data[109]
  PIN o_data[10]
    DIRECTION OUTPUT ;
    USE SIGNAL ;
    PORT
      LAYER M4 ;
        RECT  0 5.856 0.084 5.88 ;
    END
  END o_data[10]
  PIN o_data[110]
    DIRECTION OUTPUT ;
    USE SIGNAL ;
    PORT
      LAYER M4 ;
        RECT  0 19.248 0.084 19.272 ;
    END
  END o_data[110]
  PIN o_data[111]
    DIRECTION OUTPUT ;
    USE SIGNAL ;
    PORT
      LAYER M4 ;
        RECT  0 19.392 0.084 19.416 ;
    END
  END o_data[111]
  PIN o_data[112]
    DIRECTION OUTPUT ;
    USE SIGNAL ;
    PORT
      LAYER M4 ;
        RECT  0 19.536 0.084 19.56 ;
    END
  END o_data[112]
  PIN o_data[113]
    DIRECTION OUTPUT ;
    USE SIGNAL ;
    PORT
      LAYER M4 ;
        RECT  0 19.632 0.084 19.656 ;
    END
  END o_data[113]
  PIN o_data[114]
    DIRECTION OUTPUT ;
    USE SIGNAL ;
    PORT
      LAYER M4 ;
        RECT  0 19.776 0.084 19.8 ;
    END
  END o_data[114]
  PIN o_data[115]
    DIRECTION OUTPUT ;
    USE SIGNAL ;
    PORT
      LAYER M4 ;
        RECT  0 19.92 0.084 19.944 ;
    END
  END o_data[115]
  PIN o_data[116]
    DIRECTION OUTPUT ;
    USE SIGNAL ;
    PORT
      LAYER M4 ;
        RECT  0 20.064 0.084 20.088 ;
    END
  END o_data[116]
  PIN o_data[117]
    DIRECTION OUTPUT ;
    USE SIGNAL ;
    PORT
      LAYER M4 ;
        RECT  0 20.16 0.084 20.184 ;
    END
  END o_data[117]
  PIN o_data[118]
    DIRECTION OUTPUT ;
    USE SIGNAL ;
    PORT
      LAYER M4 ;
        RECT  0 20.304 0.084 20.328 ;
    END
  END o_data[118]
  PIN o_data[119]
    DIRECTION OUTPUT ;
    USE SIGNAL ;
    PORT
      LAYER M4 ;
        RECT  0 20.448 0.084 20.472 ;
    END
  END o_data[119]
  PIN o_data[11]
    DIRECTION OUTPUT ;
    USE SIGNAL ;
    PORT
      LAYER M4 ;
        RECT  0 6 0.084 6.024 ;
    END
  END o_data[11]
  PIN o_data[120]
    DIRECTION OUTPUT ;
    USE SIGNAL ;
    PORT
      LAYER M4 ;
        RECT  0 20.592 0.084 20.616 ;
    END
  END o_data[120]
  PIN o_data[121]
    DIRECTION OUTPUT ;
    USE SIGNAL ;
    PORT
      LAYER M4 ;
        RECT  0 20.736 0.084 20.76 ;
    END
  END o_data[121]
  PIN o_data[122]
    DIRECTION OUTPUT ;
    USE SIGNAL ;
    PORT
      LAYER M4 ;
        RECT  0 20.832 0.084 20.856 ;
    END
  END o_data[122]
  PIN o_data[123]
    DIRECTION OUTPUT ;
    USE SIGNAL ;
    PORT
      LAYER M4 ;
        RECT  0 20.976 0.084 21 ;
    END
  END o_data[123]
  PIN o_data[124]
    DIRECTION OUTPUT ;
    USE SIGNAL ;
    PORT
      LAYER M4 ;
        RECT  0 21.12 0.084 21.144 ;
    END
  END o_data[124]
  PIN o_data[125]
    DIRECTION OUTPUT ;
    USE SIGNAL ;
    PORT
      LAYER M4 ;
        RECT  0 21.264 0.084 21.288 ;
    END
  END o_data[125]
  PIN o_data[126]
    DIRECTION OUTPUT ;
    USE SIGNAL ;
    PORT
      LAYER M4 ;
        RECT  0 21.408 0.084 21.432 ;
    END
  END o_data[126]
  PIN o_data[127]
    DIRECTION OUTPUT ;
    USE SIGNAL ;
    PORT
      LAYER M4 ;
        RECT  0 21.504 0.084 21.528 ;
    END
  END o_data[127]
  PIN o_data[128]
    DIRECTION OUTPUT ;
    USE SIGNAL ;
    PORT
      LAYER M4 ;
        RECT  0 21.648 0.084 21.672 ;
    END
  END o_data[128]
  PIN o_data[129]
    DIRECTION OUTPUT ;
    USE SIGNAL ;
    PORT
      LAYER M4 ;
        RECT  0 21.792 0.084 21.816 ;
    END
  END o_data[129]
  PIN o_data[12]
    DIRECTION OUTPUT ;
    USE SIGNAL ;
    PORT
      LAYER M4 ;
        RECT  0 6.144 0.084 6.168 ;
    END
  END o_data[12]
  PIN o_data[130]
    DIRECTION OUTPUT ;
    USE SIGNAL ;
    PORT
      LAYER M4 ;
        RECT  0 21.936 0.084 21.96 ;
    END
  END o_data[130]
  PIN o_data[131]
    DIRECTION OUTPUT ;
    USE SIGNAL ;
    PORT
      LAYER M4 ;
        RECT  0 22.08 0.084 22.104 ;
    END
  END o_data[131]
  PIN o_data[132]
    DIRECTION OUTPUT ;
    USE SIGNAL ;
    PORT
      LAYER M4 ;
        RECT  0 22.176 0.084 22.2 ;
    END
  END o_data[132]
  PIN o_data[133]
    DIRECTION OUTPUT ;
    USE SIGNAL ;
    PORT
      LAYER M4 ;
        RECT  0 22.32 0.084 22.344 ;
    END
  END o_data[133]
  PIN o_data[134]
    DIRECTION OUTPUT ;
    USE SIGNAL ;
    PORT
      LAYER M4 ;
        RECT  0 22.464 0.084 22.488 ;
    END
  END o_data[134]
  PIN o_data[135]
    DIRECTION OUTPUT ;
    USE SIGNAL ;
    PORT
      LAYER M4 ;
        RECT  0 22.608 0.084 22.632 ;
    END
  END o_data[135]
  PIN o_data[136]
    DIRECTION OUTPUT ;
    USE SIGNAL ;
    PORT
      LAYER M4 ;
        RECT  0 22.704 0.084 22.728 ;
    END
  END o_data[136]
  PIN o_data[137]
    DIRECTION OUTPUT ;
    USE SIGNAL ;
    PORT
      LAYER M4 ;
        RECT  0 22.848 0.084 22.872 ;
    END
  END o_data[137]
  PIN o_data[138]
    DIRECTION OUTPUT ;
    USE SIGNAL ;
    PORT
      LAYER M4 ;
        RECT  0 22.992 0.084 23.016 ;
    END
  END o_data[138]
  PIN o_data[139]
    DIRECTION OUTPUT ;
    USE SIGNAL ;
    PORT
      LAYER M4 ;
        RECT  0 23.136 0.084 23.16 ;
    END
  END o_data[139]
  PIN o_data[13]
    DIRECTION OUTPUT ;
    USE SIGNAL ;
    PORT
      LAYER M4 ;
        RECT  0 6.288 0.084 6.312 ;
    END
  END o_data[13]
  PIN o_data[140]
    DIRECTION OUTPUT ;
    USE SIGNAL ;
    PORT
      LAYER M4 ;
        RECT  0 23.28 0.084 23.304 ;
    END
  END o_data[140]
  PIN o_data[141]
    DIRECTION OUTPUT ;
    USE SIGNAL ;
    PORT
      LAYER M4 ;
        RECT  0 23.376 0.084 23.4 ;
    END
  END o_data[141]
  PIN o_data[142]
    DIRECTION OUTPUT ;
    USE SIGNAL ;
    PORT
      LAYER M4 ;
        RECT  0 23.52 0.084 23.544 ;
    END
  END o_data[142]
  PIN o_data[143]
    DIRECTION OUTPUT ;
    USE SIGNAL ;
    PORT
      LAYER M4 ;
        RECT  0 23.664 0.084 23.688 ;
    END
  END o_data[143]
  PIN o_data[144]
    DIRECTION OUTPUT ;
    USE SIGNAL ;
    PORT
      LAYER M4 ;
        RECT  0 23.808 0.084 23.832 ;
    END
  END o_data[144]
  PIN o_data[145]
    DIRECTION OUTPUT ;
    USE SIGNAL ;
    PORT
      LAYER M4 ;
        RECT  0 23.952 0.084 23.976 ;
    END
  END o_data[145]
  PIN o_data[146]
    DIRECTION OUTPUT ;
    USE SIGNAL ;
    PORT
      LAYER M4 ;
        RECT  0 24.048 0.084 24.072 ;
    END
  END o_data[146]
  PIN o_data[147]
    DIRECTION OUTPUT ;
    USE SIGNAL ;
    PORT
      LAYER M4 ;
        RECT  0 24.192 0.084 24.216 ;
    END
  END o_data[147]
  PIN o_data[148]
    DIRECTION OUTPUT ;
    USE SIGNAL ;
    PORT
      LAYER M4 ;
        RECT  0 24.336 0.084 24.36 ;
    END
  END o_data[148]
  PIN o_data[149]
    DIRECTION OUTPUT ;
    USE SIGNAL ;
    PORT
      LAYER M4 ;
        RECT  0 24.48 0.084 24.504 ;
    END
  END o_data[149]
  PIN o_data[14]
    DIRECTION OUTPUT ;
    USE SIGNAL ;
    PORT
      LAYER M4 ;
        RECT  0 6.384 0.084 6.408 ;
    END
  END o_data[14]
  PIN o_data[150]
    DIRECTION OUTPUT ;
    USE SIGNAL ;
    PORT
      LAYER M4 ;
        RECT  0 24.576 0.084 24.6 ;
    END
  END o_data[150]
  PIN o_data[151]
    DIRECTION OUTPUT ;
    USE SIGNAL ;
    PORT
      LAYER M4 ;
        RECT  0 24.72 0.084 24.744 ;
    END
  END o_data[151]
  PIN o_data[152]
    DIRECTION OUTPUT ;
    USE SIGNAL ;
    PORT
      LAYER M4 ;
        RECT  0 24.864 0.084 24.888 ;
    END
  END o_data[152]
  PIN o_data[153]
    DIRECTION OUTPUT ;
    USE SIGNAL ;
    PORT
      LAYER M4 ;
        RECT  0 25.008 0.084 25.032 ;
    END
  END o_data[153]
  PIN o_data[154]
    DIRECTION OUTPUT ;
    USE SIGNAL ;
    PORT
      LAYER M4 ;
        RECT  0 25.152 0.084 25.176 ;
    END
  END o_data[154]
  PIN o_data[155]
    DIRECTION OUTPUT ;
    USE SIGNAL ;
    PORT
      LAYER M4 ;
        RECT  0 25.248 0.084 25.272 ;
    END
  END o_data[155]
  PIN o_data[156]
    DIRECTION OUTPUT ;
    USE SIGNAL ;
    PORT
      LAYER M4 ;
        RECT  0 25.392 0.084 25.416 ;
    END
  END o_data[156]
  PIN o_data[157]
    DIRECTION OUTPUT ;
    USE SIGNAL ;
    PORT
      LAYER M4 ;
        RECT  0 25.536 0.084 25.56 ;
    END
  END o_data[157]
  PIN o_data[158]
    DIRECTION OUTPUT ;
    USE SIGNAL ;
    PORT
      LAYER M4 ;
        RECT  0 25.68 0.084 25.704 ;
    END
  END o_data[158]
  PIN o_data[159]
    DIRECTION OUTPUT ;
    USE SIGNAL ;
    PORT
      LAYER M4 ;
        RECT  0 25.824 0.084 25.848 ;
    END
  END o_data[159]
  PIN o_data[15]
    DIRECTION OUTPUT ;
    USE SIGNAL ;
    PORT
      LAYER M4 ;
        RECT  0 6.528 0.084 6.552 ;
    END
  END o_data[15]
  PIN o_data[160]
    DIRECTION OUTPUT ;
    USE SIGNAL ;
    PORT
      LAYER M4 ;
        RECT  0 25.92 0.084 25.944 ;
    END
  END o_data[160]
  PIN o_data[161]
    DIRECTION OUTPUT ;
    USE SIGNAL ;
    PORT
      LAYER M4 ;
        RECT  0 26.064 0.084 26.088 ;
    END
  END o_data[161]
  PIN o_data[162]
    DIRECTION OUTPUT ;
    USE SIGNAL ;
    PORT
      LAYER M4 ;
        RECT  0 26.208 0.084 26.232 ;
    END
  END o_data[162]
  PIN o_data[163]
    DIRECTION OUTPUT ;
    USE SIGNAL ;
    PORT
      LAYER M4 ;
        RECT  0 26.352 0.084 26.376 ;
    END
  END o_data[163]
  PIN o_data[164]
    DIRECTION OUTPUT ;
    USE SIGNAL ;
    PORT
      LAYER M4 ;
        RECT  0 26.448 0.084 26.472 ;
    END
  END o_data[164]
  PIN o_data[165]
    DIRECTION OUTPUT ;
    USE SIGNAL ;
    PORT
      LAYER M4 ;
        RECT  0 26.592 0.084 26.616 ;
    END
  END o_data[165]
  PIN o_data[166]
    DIRECTION OUTPUT ;
    USE SIGNAL ;
    PORT
      LAYER M4 ;
        RECT  0 26.736 0.084 26.76 ;
    END
  END o_data[166]
  PIN o_data[167]
    DIRECTION OUTPUT ;
    USE SIGNAL ;
    PORT
      LAYER M4 ;
        RECT  0 26.88 0.084 26.904 ;
    END
  END o_data[167]
  PIN o_data[168]
    DIRECTION OUTPUT ;
    USE SIGNAL ;
    PORT
      LAYER M4 ;
        RECT  0 27.024 0.084 27.048 ;
    END
  END o_data[168]
  PIN o_data[169]
    DIRECTION OUTPUT ;
    USE SIGNAL ;
    PORT
      LAYER M4 ;
        RECT  0 27.12 0.084 27.144 ;
    END
  END o_data[169]
  PIN o_data[16]
    DIRECTION OUTPUT ;
    USE SIGNAL ;
    PORT
      LAYER M4 ;
        RECT  0 6.672 0.084 6.696 ;
    END
  END o_data[16]
  PIN o_data[170]
    DIRECTION OUTPUT ;
    USE SIGNAL ;
    PORT
      LAYER M4 ;
        RECT  0 27.264 0.084 27.288 ;
    END
  END o_data[170]
  PIN o_data[171]
    DIRECTION OUTPUT ;
    USE SIGNAL ;
    PORT
      LAYER M4 ;
        RECT  0 27.408 0.084 27.432 ;
    END
  END o_data[171]
  PIN o_data[172]
    DIRECTION OUTPUT ;
    USE SIGNAL ;
    PORT
      LAYER M4 ;
        RECT  0 27.552 0.084 27.576 ;
    END
  END o_data[172]
  PIN o_data[173]
    DIRECTION OUTPUT ;
    USE SIGNAL ;
    PORT
      LAYER M4 ;
        RECT  0 27.696 0.084 27.72 ;
    END
  END o_data[173]
  PIN o_data[174]
    DIRECTION OUTPUT ;
    USE SIGNAL ;
    PORT
      LAYER M4 ;
        RECT  0 27.792 0.084 27.816 ;
    END
  END o_data[174]
  PIN o_data[175]
    DIRECTION OUTPUT ;
    USE SIGNAL ;
    PORT
      LAYER M4 ;
        RECT  0 27.936 0.084 27.96 ;
    END
  END o_data[175]
  PIN o_data[176]
    DIRECTION OUTPUT ;
    USE SIGNAL ;
    PORT
      LAYER M4 ;
        RECT  0 28.08 0.084 28.104 ;
    END
  END o_data[176]
  PIN o_data[177]
    DIRECTION OUTPUT ;
    USE SIGNAL ;
    PORT
      LAYER M4 ;
        RECT  0 28.224 0.084 28.248 ;
    END
  END o_data[177]
  PIN o_data[178]
    DIRECTION OUTPUT ;
    USE SIGNAL ;
    PORT
      LAYER M4 ;
        RECT  0 28.32 0.084 28.344 ;
    END
  END o_data[178]
  PIN o_data[179]
    DIRECTION OUTPUT ;
    USE SIGNAL ;
    PORT
      LAYER M4 ;
        RECT  0 28.464 0.084 28.488 ;
    END
  END o_data[179]
  PIN o_data[17]
    DIRECTION OUTPUT ;
    USE SIGNAL ;
    PORT
      LAYER M4 ;
        RECT  0 6.816 0.084 6.84 ;
    END
  END o_data[17]
  PIN o_data[180]
    DIRECTION OUTPUT ;
    USE SIGNAL ;
    PORT
      LAYER M4 ;
        RECT  0 28.608 0.084 28.632 ;
    END
  END o_data[180]
  PIN o_data[181]
    DIRECTION OUTPUT ;
    USE SIGNAL ;
    PORT
      LAYER M4 ;
        RECT  0 28.752 0.084 28.776 ;
    END
  END o_data[181]
  PIN o_data[182]
    DIRECTION OUTPUT ;
    USE SIGNAL ;
    PORT
      LAYER M4 ;
        RECT  0 28.896 0.084 28.92 ;
    END
  END o_data[182]
  PIN o_data[183]
    DIRECTION OUTPUT ;
    USE SIGNAL ;
    PORT
      LAYER M4 ;
        RECT  0 28.992 0.084 29.016 ;
    END
  END o_data[183]
  PIN o_data[184]
    DIRECTION OUTPUT ;
    USE SIGNAL ;
    PORT
      LAYER M4 ;
        RECT  0 29.136 0.084 29.16 ;
    END
  END o_data[184]
  PIN o_data[185]
    DIRECTION OUTPUT ;
    USE SIGNAL ;
    PORT
      LAYER M4 ;
        RECT  0 29.28 0.084 29.304 ;
    END
  END o_data[185]
  PIN o_data[186]
    DIRECTION OUTPUT ;
    USE SIGNAL ;
    PORT
      LAYER M4 ;
        RECT  0 29.424 0.084 29.448 ;
    END
  END o_data[186]
  PIN o_data[187]
    DIRECTION OUTPUT ;
    USE SIGNAL ;
    PORT
      LAYER M4 ;
        RECT  0 29.568 0.084 29.592 ;
    END
  END o_data[187]
  PIN o_data[188]
    DIRECTION OUTPUT ;
    USE SIGNAL ;
    PORT
      LAYER M4 ;
        RECT  0 29.664 0.084 29.688 ;
    END
  END o_data[188]
  PIN o_data[189]
    DIRECTION OUTPUT ;
    USE SIGNAL ;
    PORT
      LAYER M4 ;
        RECT  0 29.808 0.084 29.832 ;
    END
  END o_data[189]
  PIN o_data[18]
    DIRECTION OUTPUT ;
    USE SIGNAL ;
    PORT
      LAYER M4 ;
        RECT  0 6.96 0.084 6.984 ;
    END
  END o_data[18]
  PIN o_data[190]
    DIRECTION OUTPUT ;
    USE SIGNAL ;
    PORT
      LAYER M4 ;
        RECT  0 29.952 0.084 29.976 ;
    END
  END o_data[190]
  PIN o_data[191]
    DIRECTION OUTPUT ;
    USE SIGNAL ;
    PORT
      LAYER M4 ;
        RECT  0 30.096 0.084 30.12 ;
    END
  END o_data[191]
  PIN o_data[192]
    DIRECTION OUTPUT ;
    USE SIGNAL ;
    PORT
      LAYER M4 ;
        RECT  0 30.24 0.084 30.264 ;
    END
  END o_data[192]
  PIN o_data[193]
    DIRECTION OUTPUT ;
    USE SIGNAL ;
    PORT
      LAYER M4 ;
        RECT  0 30.336 0.084 30.36 ;
    END
  END o_data[193]
  PIN o_data[194]
    DIRECTION OUTPUT ;
    USE SIGNAL ;
    PORT
      LAYER M4 ;
        RECT  0 30.48 0.084 30.504 ;
    END
  END o_data[194]
  PIN o_data[195]
    DIRECTION OUTPUT ;
    USE SIGNAL ;
    PORT
      LAYER M4 ;
        RECT  0 30.624 0.084 30.648 ;
    END
  END o_data[195]
  PIN o_data[196]
    DIRECTION OUTPUT ;
    USE SIGNAL ;
    PORT
      LAYER M4 ;
        RECT  0 30.768 0.084 30.792 ;
    END
  END o_data[196]
  PIN o_data[197]
    DIRECTION OUTPUT ;
    USE SIGNAL ;
    PORT
      LAYER M4 ;
        RECT  0 30.864 0.084 30.888 ;
    END
  END o_data[197]
  PIN o_data[198]
    DIRECTION OUTPUT ;
    USE SIGNAL ;
    PORT
      LAYER M4 ;
        RECT  0 31.008 0.084 31.032 ;
    END
  END o_data[198]
  PIN o_data[199]
    DIRECTION OUTPUT ;
    USE SIGNAL ;
    PORT
      LAYER M4 ;
        RECT  0 31.152 0.084 31.176 ;
    END
  END o_data[199]
  PIN o_data[19]
    DIRECTION OUTPUT ;
    USE SIGNAL ;
    PORT
      LAYER M4 ;
        RECT  0 7.056 0.084 7.08 ;
    END
  END o_data[19]
  PIN o_data[1]
    DIRECTION OUTPUT ;
    USE SIGNAL ;
    PORT
      LAYER M4 ;
        RECT  0 4.656 0.084 4.68 ;
    END
  END o_data[1]
  PIN o_data[200]
    DIRECTION OUTPUT ;
    USE SIGNAL ;
    PORT
      LAYER M4 ;
        RECT  0 31.296 0.084 31.32 ;
    END
  END o_data[200]
  PIN o_data[201]
    DIRECTION OUTPUT ;
    USE SIGNAL ;
    PORT
      LAYER M4 ;
        RECT  0 31.44 0.084 31.464 ;
    END
  END o_data[201]
  PIN o_data[202]
    DIRECTION OUTPUT ;
    USE SIGNAL ;
    PORT
      LAYER M4 ;
        RECT  0 31.536 0.084 31.56 ;
    END
  END o_data[202]
  PIN o_data[203]
    DIRECTION OUTPUT ;
    USE SIGNAL ;
    PORT
      LAYER M4 ;
        RECT  0 31.68 0.084 31.704 ;
    END
  END o_data[203]
  PIN o_data[204]
    DIRECTION OUTPUT ;
    USE SIGNAL ;
    PORT
      LAYER M4 ;
        RECT  0 31.824 0.084 31.848 ;
    END
  END o_data[204]
  PIN o_data[205]
    DIRECTION OUTPUT ;
    USE SIGNAL ;
    PORT
      LAYER M4 ;
        RECT  0 31.968 0.084 31.992 ;
    END
  END o_data[205]
  PIN o_data[206]
    DIRECTION OUTPUT ;
    USE SIGNAL ;
    PORT
      LAYER M4 ;
        RECT  0 32.112 0.084 32.136 ;
    END
  END o_data[206]
  PIN o_data[207]
    DIRECTION OUTPUT ;
    USE SIGNAL ;
    PORT
      LAYER M4 ;
        RECT  0 32.208 0.084 32.232 ;
    END
  END o_data[207]
  PIN o_data[208]
    DIRECTION OUTPUT ;
    USE SIGNAL ;
    PORT
      LAYER M4 ;
        RECT  0 32.352 0.084 32.376 ;
    END
  END o_data[208]
  PIN o_data[209]
    DIRECTION OUTPUT ;
    USE SIGNAL ;
    PORT
      LAYER M4 ;
        RECT  0 32.496 0.084 32.52 ;
    END
  END o_data[209]
  PIN o_data[20]
    DIRECTION OUTPUT ;
    USE SIGNAL ;
    PORT
      LAYER M4 ;
        RECT  0 7.2 0.084 7.224 ;
    END
  END o_data[20]
  PIN o_data[210]
    DIRECTION OUTPUT ;
    USE SIGNAL ;
    PORT
      LAYER M4 ;
        RECT  0 32.64 0.084 32.664 ;
    END
  END o_data[210]
  PIN o_data[211]
    DIRECTION OUTPUT ;
    USE SIGNAL ;
    PORT
      LAYER M4 ;
        RECT  0 32.736 0.084 32.76 ;
    END
  END o_data[211]
  PIN o_data[212]
    DIRECTION OUTPUT ;
    USE SIGNAL ;
    PORT
      LAYER M4 ;
        RECT  0 32.88 0.084 32.904 ;
    END
  END o_data[212]
  PIN o_data[213]
    DIRECTION OUTPUT ;
    USE SIGNAL ;
    PORT
      LAYER M4 ;
        RECT  0 33.024 0.084 33.048 ;
    END
  END o_data[213]
  PIN o_data[214]
    DIRECTION OUTPUT ;
    USE SIGNAL ;
    PORT
      LAYER M4 ;
        RECT  0 33.168 0.084 33.192 ;
    END
  END o_data[214]
  PIN o_data[215]
    DIRECTION OUTPUT ;
    USE SIGNAL ;
    PORT
      LAYER M4 ;
        RECT  0 33.312 0.084 33.336 ;
    END
  END o_data[215]
  PIN o_data[216]
    DIRECTION OUTPUT ;
    USE SIGNAL ;
    PORT
      LAYER M4 ;
        RECT  0 33.408 0.084 33.432 ;
    END
  END o_data[216]
  PIN o_data[217]
    DIRECTION OUTPUT ;
    USE SIGNAL ;
    PORT
      LAYER M4 ;
        RECT  0 33.552 0.084 33.576 ;
    END
  END o_data[217]
  PIN o_data[218]
    DIRECTION OUTPUT ;
    USE SIGNAL ;
    PORT
      LAYER M4 ;
        RECT  0 33.696 0.084 33.72 ;
    END
  END o_data[218]
  PIN o_data[219]
    DIRECTION OUTPUT ;
    USE SIGNAL ;
    PORT
      LAYER M4 ;
        RECT  0 33.84 0.084 33.864 ;
    END
  END o_data[219]
  PIN o_data[21]
    DIRECTION OUTPUT ;
    USE SIGNAL ;
    PORT
      LAYER M4 ;
        RECT  0 7.344 0.084 7.368 ;
    END
  END o_data[21]
  PIN o_data[220]
    DIRECTION OUTPUT ;
    USE SIGNAL ;
    PORT
      LAYER M4 ;
        RECT  0 33.984 0.084 34.008 ;
    END
  END o_data[220]
  PIN o_data[221]
    DIRECTION OUTPUT ;
    USE SIGNAL ;
    PORT
      LAYER M4 ;
        RECT  0 34.08 0.084 34.104 ;
    END
  END o_data[221]
  PIN o_data[222]
    DIRECTION OUTPUT ;
    USE SIGNAL ;
    PORT
      LAYER M4 ;
        RECT  0 34.224 0.084 34.248 ;
    END
  END o_data[222]
  PIN o_data[223]
    DIRECTION OUTPUT ;
    USE SIGNAL ;
    PORT
      LAYER M4 ;
        RECT  0 34.368 0.084 34.392 ;
    END
  END o_data[223]
  PIN o_data[224]
    DIRECTION OUTPUT ;
    USE SIGNAL ;
    PORT
      LAYER M4 ;
        RECT  0 34.512 0.084 34.536 ;
    END
  END o_data[224]
  PIN o_data[225]
    DIRECTION OUTPUT ;
    USE SIGNAL ;
    PORT
      LAYER M4 ;
        RECT  0 34.608 0.084 34.632 ;
    END
  END o_data[225]
  PIN o_data[226]
    DIRECTION OUTPUT ;
    USE SIGNAL ;
    PORT
      LAYER M4 ;
        RECT  0 34.752 0.084 34.776 ;
    END
  END o_data[226]
  PIN o_data[227]
    DIRECTION OUTPUT ;
    USE SIGNAL ;
    PORT
      LAYER M4 ;
        RECT  0 34.896 0.084 34.92 ;
    END
  END o_data[227]
  PIN o_data[228]
    DIRECTION OUTPUT ;
    USE SIGNAL ;
    PORT
      LAYER M4 ;
        RECT  0 35.04 0.084 35.064 ;
    END
  END o_data[228]
  PIN o_data[229]
    DIRECTION OUTPUT ;
    USE SIGNAL ;
    PORT
      LAYER M4 ;
        RECT  0 35.184 0.084 35.208 ;
    END
  END o_data[229]
  PIN o_data[22]
    DIRECTION OUTPUT ;
    USE SIGNAL ;
    PORT
      LAYER M4 ;
        RECT  0 7.488 0.084 7.512 ;
    END
  END o_data[22]
  PIN o_data[230]
    DIRECTION OUTPUT ;
    USE SIGNAL ;
    PORT
      LAYER M4 ;
        RECT  0 35.28 0.084 35.304 ;
    END
  END o_data[230]
  PIN o_data[231]
    DIRECTION OUTPUT ;
    USE SIGNAL ;
    PORT
      LAYER M4 ;
        RECT  0 35.424 0.084 35.448 ;
    END
  END o_data[231]
  PIN o_data[232]
    DIRECTION OUTPUT ;
    USE SIGNAL ;
    PORT
      LAYER M4 ;
        RECT  0 35.568 0.084 35.592 ;
    END
  END o_data[232]
  PIN o_data[233]
    DIRECTION OUTPUT ;
    USE SIGNAL ;
    PORT
      LAYER M4 ;
        RECT  0 35.712 0.084 35.736 ;
    END
  END o_data[233]
  PIN o_data[234]
    DIRECTION OUTPUT ;
    USE SIGNAL ;
    PORT
      LAYER M4 ;
        RECT  0 35.856 0.084 35.88 ;
    END
  END o_data[234]
  PIN o_data[235]
    DIRECTION OUTPUT ;
    USE SIGNAL ;
    PORT
      LAYER M4 ;
        RECT  0 35.952 0.084 35.976 ;
    END
  END o_data[235]
  PIN o_data[236]
    DIRECTION OUTPUT ;
    USE SIGNAL ;
    PORT
      LAYER M4 ;
        RECT  0 36.096 0.084 36.12 ;
    END
  END o_data[236]
  PIN o_data[237]
    DIRECTION OUTPUT ;
    USE SIGNAL ;
    PORT
      LAYER M4 ;
        RECT  0 36.24 0.084 36.264 ;
    END
  END o_data[237]
  PIN o_data[238]
    DIRECTION OUTPUT ;
    USE SIGNAL ;
    PORT
      LAYER M4 ;
        RECT  0 36.384 0.084 36.408 ;
    END
  END o_data[238]
  PIN o_data[239]
    DIRECTION OUTPUT ;
    USE SIGNAL ;
    PORT
      LAYER M4 ;
        RECT  0 36.48 0.084 36.504 ;
    END
  END o_data[239]
  PIN o_data[23]
    DIRECTION OUTPUT ;
    USE SIGNAL ;
    PORT
      LAYER M4 ;
        RECT  0 7.632 0.084 7.656 ;
    END
  END o_data[23]
  PIN o_data[240]
    DIRECTION OUTPUT ;
    USE SIGNAL ;
    PORT
      LAYER M4 ;
        RECT  0 36.624 0.084 36.648 ;
    END
  END o_data[240]
  PIN o_data[241]
    DIRECTION OUTPUT ;
    USE SIGNAL ;
    PORT
      LAYER M4 ;
        RECT  0 36.768 0.084 36.792 ;
    END
  END o_data[241]
  PIN o_data[242]
    DIRECTION OUTPUT ;
    USE SIGNAL ;
    PORT
      LAYER M4 ;
        RECT  0 36.912 0.084 36.936 ;
    END
  END o_data[242]
  PIN o_data[243]
    DIRECTION OUTPUT ;
    USE SIGNAL ;
    PORT
      LAYER M4 ;
        RECT  0 37.056 0.084 37.08 ;
    END
  END o_data[243]
  PIN o_data[244]
    DIRECTION OUTPUT ;
    USE SIGNAL ;
    PORT
      LAYER M4 ;
        RECT  0 37.152 0.084 37.176 ;
    END
  END o_data[244]
  PIN o_data[245]
    DIRECTION OUTPUT ;
    USE SIGNAL ;
    PORT
      LAYER M4 ;
        RECT  0 37.296 0.084 37.32 ;
    END
  END o_data[245]
  PIN o_data[246]
    DIRECTION OUTPUT ;
    USE SIGNAL ;
    PORT
      LAYER M4 ;
        RECT  0 37.44 0.084 37.464 ;
    END
  END o_data[246]
  PIN o_data[247]
    DIRECTION OUTPUT ;
    USE SIGNAL ;
    PORT
      LAYER M4 ;
        RECT  0 37.584 0.084 37.608 ;
    END
  END o_data[247]
  PIN o_data[248]
    DIRECTION OUTPUT ;
    USE SIGNAL ;
    PORT
      LAYER M4 ;
        RECT  0 37.728 0.084 37.752 ;
    END
  END o_data[248]
  PIN o_data[249]
    DIRECTION OUTPUT ;
    USE SIGNAL ;
    PORT
      LAYER M4 ;
        RECT  0 37.824 0.084 37.848 ;
    END
  END o_data[249]
  PIN o_data[24]
    DIRECTION OUTPUT ;
    USE SIGNAL ;
    PORT
      LAYER M4 ;
        RECT  0 7.728 0.084 7.752 ;
    END
  END o_data[24]
  PIN o_data[250]
    DIRECTION OUTPUT ;
    USE SIGNAL ;
    PORT
      LAYER M4 ;
        RECT  0 37.968 0.084 37.992 ;
    END
  END o_data[250]
  PIN o_data[251]
    DIRECTION OUTPUT ;
    USE SIGNAL ;
    PORT
      LAYER M4 ;
        RECT  0 38.112 0.084 38.136 ;
    END
  END o_data[251]
  PIN o_data[252]
    DIRECTION OUTPUT ;
    USE SIGNAL ;
    PORT
      LAYER M4 ;
        RECT  0 38.256 0.084 38.28 ;
    END
  END o_data[252]
  PIN o_data[253]
    DIRECTION OUTPUT ;
    USE SIGNAL ;
    PORT
      LAYER M4 ;
        RECT  0 38.4 0.084 38.424 ;
    END
  END o_data[253]
  PIN o_data[254]
    DIRECTION OUTPUT ;
    USE SIGNAL ;
    PORT
      LAYER M4 ;
        RECT  0 38.496 0.084 38.52 ;
    END
  END o_data[254]
  PIN o_data[255]
    DIRECTION OUTPUT ;
    USE SIGNAL ;
    PORT
      LAYER M4 ;
        RECT  0 38.64 0.084 38.664 ;
    END
  END o_data[255]
  PIN o_data[25]
    DIRECTION OUTPUT ;
    USE SIGNAL ;
    PORT
      LAYER M4 ;
        RECT  0 7.872 0.084 7.896 ;
    END
  END o_data[25]
  PIN o_data[26]
    DIRECTION OUTPUT ;
    USE SIGNAL ;
    PORT
      LAYER M4 ;
        RECT  0 8.016 0.084 8.04 ;
    END
  END o_data[26]
  PIN o_data[27]
    DIRECTION OUTPUT ;
    USE SIGNAL ;
    PORT
      LAYER M4 ;
        RECT  0 8.16 0.084 8.184 ;
    END
  END o_data[27]
  PIN o_data[28]
    DIRECTION OUTPUT ;
    USE SIGNAL ;
    PORT
      LAYER M4 ;
        RECT  0 8.256 0.084 8.28 ;
    END
  END o_data[28]
  PIN o_data[29]
    DIRECTION OUTPUT ;
    USE SIGNAL ;
    PORT
      LAYER M4 ;
        RECT  0 8.4 0.084 8.424 ;
    END
  END o_data[29]
  PIN o_data[2]
    DIRECTION OUTPUT ;
    USE SIGNAL ;
    PORT
      LAYER M4 ;
        RECT  0 4.8 0.084 4.824 ;
    END
  END o_data[2]
  PIN o_data[30]
    DIRECTION OUTPUT ;
    USE SIGNAL ;
    PORT
      LAYER M4 ;
        RECT  0 8.544 0.084 8.568 ;
    END
  END o_data[30]
  PIN o_data[31]
    DIRECTION OUTPUT ;
    USE SIGNAL ;
    PORT
      LAYER M4 ;
        RECT  0 8.688 0.084 8.712 ;
    END
  END o_data[31]
  PIN o_data[32]
    DIRECTION OUTPUT ;
    USE SIGNAL ;
    PORT
      LAYER M4 ;
        RECT  0 8.832 0.084 8.856 ;
    END
  END o_data[32]
  PIN o_data[33]
    DIRECTION OUTPUT ;
    USE SIGNAL ;
    PORT
      LAYER M4 ;
        RECT  0 8.928 0.084 8.952 ;
    END
  END o_data[33]
  PIN o_data[34]
    DIRECTION OUTPUT ;
    USE SIGNAL ;
    PORT
      LAYER M4 ;
        RECT  0 9.072 0.084 9.096 ;
    END
  END o_data[34]
  PIN o_data[35]
    DIRECTION OUTPUT ;
    USE SIGNAL ;
    PORT
      LAYER M4 ;
        RECT  0 9.216 0.084 9.24 ;
    END
  END o_data[35]
  PIN o_data[36]
    DIRECTION OUTPUT ;
    USE SIGNAL ;
    PORT
      LAYER M4 ;
        RECT  0 9.36 0.084 9.384 ;
    END
  END o_data[36]
  PIN o_data[37]
    DIRECTION OUTPUT ;
    USE SIGNAL ;
    PORT
      LAYER M4 ;
        RECT  0 9.504 0.084 9.528 ;
    END
  END o_data[37]
  PIN o_data[38]
    DIRECTION OUTPUT ;
    USE SIGNAL ;
    PORT
      LAYER M4 ;
        RECT  0 9.6 0.084 9.624 ;
    END
  END o_data[38]
  PIN o_data[39]
    DIRECTION OUTPUT ;
    USE SIGNAL ;
    PORT
      LAYER M4 ;
        RECT  0 9.744 0.084 9.768 ;
    END
  END o_data[39]
  PIN o_data[3]
    DIRECTION OUTPUT ;
    USE SIGNAL ;
    PORT
      LAYER M4 ;
        RECT  0 4.944 0.084 4.968 ;
    END
  END o_data[3]
  PIN o_data[40]
    DIRECTION OUTPUT ;
    USE SIGNAL ;
    PORT
      LAYER M4 ;
        RECT  0 9.888 0.084 9.912 ;
    END
  END o_data[40]
  PIN o_data[41]
    DIRECTION OUTPUT ;
    USE SIGNAL ;
    PORT
      LAYER M4 ;
        RECT  0 10.032 0.084 10.056 ;
    END
  END o_data[41]
  PIN o_data[42]
    DIRECTION OUTPUT ;
    USE SIGNAL ;
    PORT
      LAYER M4 ;
        RECT  0 10.128 0.084 10.152 ;
    END
  END o_data[42]
  PIN o_data[43]
    DIRECTION OUTPUT ;
    USE SIGNAL ;
    PORT
      LAYER M4 ;
        RECT  0 10.272 0.084 10.296 ;
    END
  END o_data[43]
  PIN o_data[44]
    DIRECTION OUTPUT ;
    USE SIGNAL ;
    PORT
      LAYER M4 ;
        RECT  0 10.416 0.084 10.44 ;
    END
  END o_data[44]
  PIN o_data[45]
    DIRECTION OUTPUT ;
    USE SIGNAL ;
    PORT
      LAYER M4 ;
        RECT  0 10.56 0.084 10.584 ;
    END
  END o_data[45]
  PIN o_data[46]
    DIRECTION OUTPUT ;
    USE SIGNAL ;
    PORT
      LAYER M4 ;
        RECT  0 10.704 0.084 10.728 ;
    END
  END o_data[46]
  PIN o_data[47]
    DIRECTION OUTPUT ;
    USE SIGNAL ;
    PORT
      LAYER M4 ;
        RECT  0 10.8 0.084 10.824 ;
    END
  END o_data[47]
  PIN o_data[48]
    DIRECTION OUTPUT ;
    USE SIGNAL ;
    PORT
      LAYER M4 ;
        RECT  0 10.944 0.084 10.968 ;
    END
  END o_data[48]
  PIN o_data[49]
    DIRECTION OUTPUT ;
    USE SIGNAL ;
    PORT
      LAYER M4 ;
        RECT  0 11.088 0.084 11.112 ;
    END
  END o_data[49]
  PIN o_data[4]
    DIRECTION OUTPUT ;
    USE SIGNAL ;
    PORT
      LAYER M4 ;
        RECT  0 5.088 0.084 5.112 ;
    END
  END o_data[4]
  PIN o_data[50]
    DIRECTION OUTPUT ;
    USE SIGNAL ;
    PORT
      LAYER M4 ;
        RECT  0 11.232 0.084 11.256 ;
    END
  END o_data[50]
  PIN o_data[51]
    DIRECTION OUTPUT ;
    USE SIGNAL ;
    PORT
      LAYER M4 ;
        RECT  0 11.376 0.084 11.4 ;
    END
  END o_data[51]
  PIN o_data[52]
    DIRECTION OUTPUT ;
    USE SIGNAL ;
    PORT
      LAYER M4 ;
        RECT  0 11.472 0.084 11.496 ;
    END
  END o_data[52]
  PIN o_data[53]
    DIRECTION OUTPUT ;
    USE SIGNAL ;
    PORT
      LAYER M4 ;
        RECT  0 11.616 0.084 11.64 ;
    END
  END o_data[53]
  PIN o_data[54]
    DIRECTION OUTPUT ;
    USE SIGNAL ;
    PORT
      LAYER M4 ;
        RECT  0 11.76 0.084 11.784 ;
    END
  END o_data[54]
  PIN o_data[55]
    DIRECTION OUTPUT ;
    USE SIGNAL ;
    PORT
      LAYER M4 ;
        RECT  0 11.904 0.084 11.928 ;
    END
  END o_data[55]
  PIN o_data[56]
    DIRECTION OUTPUT ;
    USE SIGNAL ;
    PORT
      LAYER M4 ;
        RECT  0 12.048 0.084 12.072 ;
    END
  END o_data[56]
  PIN o_data[57]
    DIRECTION OUTPUT ;
    USE SIGNAL ;
    PORT
      LAYER M4 ;
        RECT  0 12.144 0.084 12.168 ;
    END
  END o_data[57]
  PIN o_data[58]
    DIRECTION OUTPUT ;
    USE SIGNAL ;
    PORT
      LAYER M4 ;
        RECT  0 12.288 0.084 12.312 ;
    END
  END o_data[58]
  PIN o_data[59]
    DIRECTION OUTPUT ;
    USE SIGNAL ;
    PORT
      LAYER M4 ;
        RECT  0 12.432 0.084 12.456 ;
    END
  END o_data[59]
  PIN o_data[5]
    DIRECTION OUTPUT ;
    USE SIGNAL ;
    PORT
      LAYER M4 ;
        RECT  0 5.184 0.084 5.208 ;
    END
  END o_data[5]
  PIN o_data[60]
    DIRECTION OUTPUT ;
    USE SIGNAL ;
    PORT
      LAYER M4 ;
        RECT  0 12.576 0.084 12.6 ;
    END
  END o_data[60]
  PIN o_data[61]
    DIRECTION OUTPUT ;
    USE SIGNAL ;
    PORT
      LAYER M4 ;
        RECT  0 12.672 0.084 12.696 ;
    END
  END o_data[61]
  PIN o_data[62]
    DIRECTION OUTPUT ;
    USE SIGNAL ;
    PORT
      LAYER M4 ;
        RECT  0 12.816 0.084 12.84 ;
    END
  END o_data[62]
  PIN o_data[63]
    DIRECTION OUTPUT ;
    USE SIGNAL ;
    PORT
      LAYER M4 ;
        RECT  0 12.96 0.084 12.984 ;
    END
  END o_data[63]
  PIN o_data[64]
    DIRECTION OUTPUT ;
    USE SIGNAL ;
    PORT
      LAYER M4 ;
        RECT  0 13.104 0.084 13.128 ;
    END
  END o_data[64]
  PIN o_data[65]
    DIRECTION OUTPUT ;
    USE SIGNAL ;
    PORT
      LAYER M4 ;
        RECT  0 13.248 0.084 13.272 ;
    END
  END o_data[65]
  PIN o_data[66]
    DIRECTION OUTPUT ;
    USE SIGNAL ;
    PORT
      LAYER M4 ;
        RECT  0 13.344 0.084 13.368 ;
    END
  END o_data[66]
  PIN o_data[67]
    DIRECTION OUTPUT ;
    USE SIGNAL ;
    PORT
      LAYER M4 ;
        RECT  0 13.488 0.084 13.512 ;
    END
  END o_data[67]
  PIN o_data[68]
    DIRECTION OUTPUT ;
    USE SIGNAL ;
    PORT
      LAYER M4 ;
        RECT  0 13.632 0.084 13.656 ;
    END
  END o_data[68]
  PIN o_data[69]
    DIRECTION OUTPUT ;
    USE SIGNAL ;
    PORT
      LAYER M4 ;
        RECT  0 13.776 0.084 13.8 ;
    END
  END o_data[69]
  PIN o_data[6]
    DIRECTION OUTPUT ;
    USE SIGNAL ;
    PORT
      LAYER M4 ;
        RECT  0 5.328 0.084 5.352 ;
    END
  END o_data[6]
  PIN o_data[70]
    DIRECTION OUTPUT ;
    USE SIGNAL ;
    PORT
      LAYER M4 ;
        RECT  0 13.92 0.084 13.944 ;
    END
  END o_data[70]
  PIN o_data[71]
    DIRECTION OUTPUT ;
    USE SIGNAL ;
    PORT
      LAYER M4 ;
        RECT  0 14.016 0.084 14.04 ;
    END
  END o_data[71]
  PIN o_data[72]
    DIRECTION OUTPUT ;
    USE SIGNAL ;
    PORT
      LAYER M4 ;
        RECT  0 14.16 0.084 14.184 ;
    END
  END o_data[72]
  PIN o_data[73]
    DIRECTION OUTPUT ;
    USE SIGNAL ;
    PORT
      LAYER M4 ;
        RECT  0 14.304 0.084 14.328 ;
    END
  END o_data[73]
  PIN o_data[74]
    DIRECTION OUTPUT ;
    USE SIGNAL ;
    PORT
      LAYER M4 ;
        RECT  0 14.448 0.084 14.472 ;
    END
  END o_data[74]
  PIN o_data[75]
    DIRECTION OUTPUT ;
    USE SIGNAL ;
    PORT
      LAYER M4 ;
        RECT  0 14.544 0.084 14.568 ;
    END
  END o_data[75]
  PIN o_data[76]
    DIRECTION OUTPUT ;
    USE SIGNAL ;
    PORT
      LAYER M4 ;
        RECT  0 14.688 0.084 14.712 ;
    END
  END o_data[76]
  PIN o_data[77]
    DIRECTION OUTPUT ;
    USE SIGNAL ;
    PORT
      LAYER M4 ;
        RECT  0 14.832 0.084 14.856 ;
    END
  END o_data[77]
  PIN o_data[78]
    DIRECTION OUTPUT ;
    USE SIGNAL ;
    PORT
      LAYER M4 ;
        RECT  0 14.976 0.084 15 ;
    END
  END o_data[78]
  PIN o_data[79]
    DIRECTION OUTPUT ;
    USE SIGNAL ;
    PORT
      LAYER M4 ;
        RECT  0 15.12 0.084 15.144 ;
    END
  END o_data[79]
  PIN o_data[7]
    DIRECTION OUTPUT ;
    USE SIGNAL ;
    PORT
      LAYER M4 ;
        RECT  0 5.472 0.084 5.496 ;
    END
  END o_data[7]
  PIN o_data[80]
    DIRECTION OUTPUT ;
    USE SIGNAL ;
    PORT
      LAYER M4 ;
        RECT  0 15.216 0.084 15.24 ;
    END
  END o_data[80]
  PIN o_data[81]
    DIRECTION OUTPUT ;
    USE SIGNAL ;
    PORT
      LAYER M4 ;
        RECT  0 15.36 0.084 15.384 ;
    END
  END o_data[81]
  PIN o_data[82]
    DIRECTION OUTPUT ;
    USE SIGNAL ;
    PORT
      LAYER M4 ;
        RECT  0 15.504 0.084 15.528 ;
    END
  END o_data[82]
  PIN o_data[83]
    DIRECTION OUTPUT ;
    USE SIGNAL ;
    PORT
      LAYER M4 ;
        RECT  0 15.648 0.084 15.672 ;
    END
  END o_data[83]
  PIN o_data[84]
    DIRECTION OUTPUT ;
    USE SIGNAL ;
    PORT
      LAYER M4 ;
        RECT  0 15.792 0.084 15.816 ;
    END
  END o_data[84]
  PIN o_data[85]
    DIRECTION OUTPUT ;
    USE SIGNAL ;
    PORT
      LAYER M4 ;
        RECT  0 15.888 0.084 15.912 ;
    END
  END o_data[85]
  PIN o_data[86]
    DIRECTION OUTPUT ;
    USE SIGNAL ;
    PORT
      LAYER M4 ;
        RECT  0 16.032 0.084 16.056 ;
    END
  END o_data[86]
  PIN o_data[87]
    DIRECTION OUTPUT ;
    USE SIGNAL ;
    PORT
      LAYER M4 ;
        RECT  0 16.176 0.084 16.2 ;
    END
  END o_data[87]
  PIN o_data[88]
    DIRECTION OUTPUT ;
    USE SIGNAL ;
    PORT
      LAYER M4 ;
        RECT  0 16.32 0.084 16.344 ;
    END
  END o_data[88]
  PIN o_data[89]
    DIRECTION OUTPUT ;
    USE SIGNAL ;
    PORT
      LAYER M4 ;
        RECT  0 16.416 0.084 16.44 ;
    END
  END o_data[89]
  PIN o_data[8]
    DIRECTION OUTPUT ;
    USE SIGNAL ;
    PORT
      LAYER M4 ;
        RECT  0 5.616 0.084 5.64 ;
    END
  END o_data[8]
  PIN o_data[90]
    DIRECTION OUTPUT ;
    USE SIGNAL ;
    PORT
      LAYER M4 ;
        RECT  0 16.56 0.084 16.584 ;
    END
  END o_data[90]
  PIN o_data[91]
    DIRECTION OUTPUT ;
    USE SIGNAL ;
    PORT
      LAYER M4 ;
        RECT  0 16.704 0.084 16.728 ;
    END
  END o_data[91]
  PIN o_data[92]
    DIRECTION OUTPUT ;
    USE SIGNAL ;
    PORT
      LAYER M4 ;
        RECT  0 16.848 0.084 16.872 ;
    END
  END o_data[92]
  PIN o_data[93]
    DIRECTION OUTPUT ;
    USE SIGNAL ;
    PORT
      LAYER M4 ;
        RECT  0 16.992 0.084 17.016 ;
    END
  END o_data[93]
  PIN o_data[94]
    DIRECTION OUTPUT ;
    USE SIGNAL ;
    PORT
      LAYER M4 ;
        RECT  0 17.088 0.084 17.112 ;
    END
  END o_data[94]
  PIN o_data[95]
    DIRECTION OUTPUT ;
    USE SIGNAL ;
    PORT
      LAYER M4 ;
        RECT  0 17.232 0.084 17.256 ;
    END
  END o_data[95]
  PIN o_data[96]
    DIRECTION OUTPUT ;
    USE SIGNAL ;
    PORT
      LAYER M4 ;
        RECT  0 17.376 0.084 17.4 ;
    END
  END o_data[96]
  PIN o_data[97]
    DIRECTION OUTPUT ;
    USE SIGNAL ;
    PORT
      LAYER M4 ;
        RECT  0 17.52 0.084 17.544 ;
    END
  END o_data[97]
  PIN o_data[98]
    DIRECTION OUTPUT ;
    USE SIGNAL ;
    PORT
      LAYER M4 ;
        RECT  0 17.664 0.084 17.688 ;
    END
  END o_data[98]
  PIN o_data[99]
    DIRECTION OUTPUT ;
    USE SIGNAL ;
    PORT
      LAYER M4 ;
        RECT  0 17.76 0.084 17.784 ;
    END
  END o_data[99]
  PIN o_data[9]
    DIRECTION OUTPUT ;
    USE SIGNAL ;
    PORT
      LAYER M4 ;
        RECT  0 5.76 0.084 5.784 ;
    END
  END o_data[9]
  PIN o_row[0]
    DIRECTION OUTPUT ;
    USE SIGNAL ;
    PORT
      LAYER M4 ;
        RECT  0 38.784 0.084 38.808 ;
    END
  END o_row[0]
  PIN o_row[1]
    DIRECTION OUTPUT ;
    USE SIGNAL ;
    PORT
      LAYER M4 ;
        RECT  0 38.928 0.084 38.952 ;
    END
  END o_row[1]
  PIN o_row[2]
    DIRECTION OUTPUT ;
    USE SIGNAL ;
    PORT
      LAYER M4 ;
        RECT  0 39.024 0.084 39.048 ;
    END
  END o_row[2]
  PIN o_row[3]
    DIRECTION OUTPUT ;
    USE SIGNAL ;
    PORT
      LAYER M4 ;
        RECT  0 39.168 0.084 39.192 ;
    END
  END o_row[3]
  PIN o_row[4]
    DIRECTION OUTPUT ;
    USE SIGNAL ;
    PORT
      LAYER M4 ;
        RECT  0 39.312 0.084 39.336 ;
    END
  END o_row[4]
  PIN o_row[5]
    DIRECTION OUTPUT ;
    USE SIGNAL ;
    PORT
      LAYER M4 ;
        RECT  0 39.456 0.084 39.48 ;
    END
  END o_row[5]
  PIN o_row[6]
    DIRECTION OUTPUT ;
    USE SIGNAL ;
    PORT
      LAYER M4 ;
        RECT  0 39.6 0.084 39.624 ;
    END
  END o_row[6]
  PIN o_row[7]
    DIRECTION OUTPUT ;
    USE SIGNAL ;
    PORT
      LAYER M4 ;
        RECT  0 39.696 0.084 39.72 ;
    END
  END o_row[7]
  PIN o_sec[0]
    DIRECTION OUTPUT ;
    USE SIGNAL ;
    PORT
      LAYER M4 ;
        RECT  0 39.84 0.084 39.864 ;
    END
  END o_sec[0]
  PIN o_sec[10]
    DIRECTION OUTPUT ;
    USE SIGNAL ;
    PORT
      LAYER M4 ;
        RECT  0 41.184 0.084 41.208 ;
    END
  END o_sec[10]
  PIN o_sec[11]
    DIRECTION OUTPUT ;
    USE SIGNAL ;
    PORT
      LAYER M4 ;
        RECT  0 41.328 0.084 41.352 ;
    END
  END o_sec[11]
  PIN o_sec[12]
    DIRECTION OUTPUT ;
    USE SIGNAL ;
    PORT
      LAYER M4 ;
        RECT  0 41.472 0.084 41.496 ;
    END
  END o_sec[12]
  PIN o_sec[13]
    DIRECTION OUTPUT ;
    USE SIGNAL ;
    PORT
      LAYER M4 ;
        RECT  0 41.568 0.084 41.592 ;
    END
  END o_sec[13]
  PIN o_sec[14]
    DIRECTION OUTPUT ;
    USE SIGNAL ;
    PORT
      LAYER M4 ;
        RECT  0 41.712 0.084 41.736 ;
    END
  END o_sec[14]
  PIN o_sec[15]
    DIRECTION OUTPUT ;
    USE SIGNAL ;
    PORT
      LAYER M4 ;
        RECT  0 41.856 0.084 41.88 ;
    END
  END o_sec[15]
  PIN o_sec[16]
    DIRECTION OUTPUT ;
    USE SIGNAL ;
    PORT
      LAYER M4 ;
        RECT  0 42 0.084 42.024 ;
    END
  END o_sec[16]
  PIN o_sec[1]
    DIRECTION OUTPUT ;
    USE SIGNAL ;
    PORT
      LAYER M4 ;
        RECT  0 39.984 0.084 40.008 ;
    END
  END o_sec[1]
  PIN o_sec[2]
    DIRECTION OUTPUT ;
    USE SIGNAL ;
    PORT
      LAYER M4 ;
        RECT  0 40.128 0.084 40.152 ;
    END
  END o_sec[2]
  PIN o_sec[3]
    DIRECTION OUTPUT ;
    USE SIGNAL ;
    PORT
      LAYER M4 ;
        RECT  0 40.272 0.084 40.296 ;
    END
  END o_sec[3]
  PIN o_sec[4]
    DIRECTION OUTPUT ;
    USE SIGNAL ;
    PORT
      LAYER M4 ;
        RECT  0 40.368 0.084 40.392 ;
    END
  END o_sec[4]
  PIN o_sec[5]
    DIRECTION OUTPUT ;
    USE SIGNAL ;
    PORT
      LAYER M4 ;
        RECT  0 40.512 0.084 40.536 ;
    END
  END o_sec[5]
  PIN o_sec[6]
    DIRECTION OUTPUT ;
    USE SIGNAL ;
    PORT
      LAYER M4 ;
        RECT  0 40.656 0.084 40.68 ;
    END
  END o_sec[6]
  PIN o_sec[7]
    DIRECTION OUTPUT ;
    USE SIGNAL ;
    PORT
      LAYER M4 ;
        RECT  0 40.8 0.084 40.824 ;
    END
  END o_sec[7]
  PIN o_sec[8]
    DIRECTION OUTPUT ;
    USE SIGNAL ;
    PORT
      LAYER M4 ;
        RECT  0 40.896 0.084 40.92 ;
    END
  END o_sec[8]
  PIN o_sec[9]
    DIRECTION OUTPUT ;
    USE SIGNAL ;
    PORT
      LAYER M4 ;
        RECT  0 41.04 0.084 41.064 ;
    END
  END o_sec[9]
  PIN o_v
    DIRECTION OUTPUT ;
    USE SIGNAL ;
    PORT
      LAYER M4 ;
        RECT  0 42.144 0.084 42.168 ;
    END
  END o_v
  PIN VDD
    DIRECTION INOUT ;
    USE POWER ;
    PORT
      LAYER M5 ;
        RECT  34.992 2.151 35.112 41.049 ;
        RECT  29.592 2.151 29.712 41.049 ;
        RECT  24.192 2.151 24.312 41.049 ;
        RECT  18.792 2.151 18.912 41.049 ;
        RECT  13.392 2.151 13.512 41.049 ;
        RECT  7.992 2.151 8.112 41.049 ;
        RECT  2.592 2.151 2.712 41.049 ;
    END
  END VDD
  PIN VSS
    DIRECTION INOUT ;
    USE GROUND ;
    PORT
      LAYER M5 ;
        RECT  34.8 2.137 34.92 41.063 ;
        RECT  29.4 2.137 29.52 41.063 ;
        RECT  24 2.137 24.12 41.063 ;
        RECT  18.6 2.137 18.72 41.063 ;
        RECT  13.2 2.137 13.32 41.063 ;
        RECT  7.8 2.137 7.92 41.063 ;
        RECT  2.4 2.137 2.52 41.063 ;
    END
  END VSS
  OBS
    LAYER RVTN ;
     RECT  2.16 2.16 38.88 2.295 ;
     RECT  2.16 2.565 38.88 2.835 ;
     RECT  2.16 3.105 38.88 3.375 ;
     RECT  2.16 3.645 38.88 3.915 ;
     RECT  2.16 4.185 38.88 4.455 ;
     RECT  2.16 4.725 38.88 4.995 ;
     RECT  2.16 5.265 38.88 5.535 ;
     RECT  2.16 5.805 38.88 6.075 ;
     RECT  2.16 6.345 38.88 6.615 ;
     RECT  2.16 6.885 38.88 7.155 ;
     RECT  2.16 7.425 38.88 7.695 ;
     RECT  2.16 7.965 38.88 8.235 ;
     RECT  2.16 8.505 38.88 8.775 ;
     RECT  2.16 9.045 38.88 9.315 ;
     RECT  2.16 9.585 38.88 9.855 ;
     RECT  2.16 10.125 38.88 10.395 ;
     RECT  2.16 10.665 38.88 10.935 ;
     RECT  2.16 11.205 38.88 11.475 ;
     RECT  2.16 11.745 38.88 12.015 ;
     RECT  2.16 12.285 38.88 12.555 ;
     RECT  2.16 12.825 38.88 13.095 ;
     RECT  2.16 13.365 38.88 13.635 ;
     RECT  2.16 13.905 38.88 14.175 ;
     RECT  2.16 14.445 38.88 14.715 ;
     RECT  2.16 14.985 38.88 15.255 ;
     RECT  2.16 15.525 38.88 15.795 ;
     RECT  2.16 16.065 38.88 16.335 ;
     RECT  2.16 16.605 38.88 16.875 ;
     RECT  2.16 17.145 38.88 17.415 ;
     RECT  2.16 17.685 38.88 17.955 ;
     RECT  2.16 18.225 38.88 18.495 ;
     RECT  2.16 18.765 38.88 19.035 ;
     RECT  2.16 19.305 38.88 19.575 ;
     RECT  2.16 19.845 38.88 20.115 ;
     RECT  2.16 20.385 38.88 20.655 ;
     RECT  2.16 20.925 38.88 21.195 ;
     RECT  2.16 21.465 38.88 21.735 ;
     RECT  2.16 22.005 38.88 22.275 ;
     RECT  2.16 22.545 38.88 22.815 ;
     RECT  2.16 23.085 38.88 23.355 ;
     RECT  2.16 23.625 38.88 23.895 ;
     RECT  2.16 24.165 38.88 24.435 ;
     RECT  2.16 24.705 38.88 24.975 ;
     RECT  2.16 25.245 38.88 25.515 ;
     RECT  2.16 25.785 38.88 26.055 ;
     RECT  2.16 26.325 38.88 26.595 ;
     RECT  2.16 26.865 38.88 27.135 ;
     RECT  2.16 27.405 38.88 27.675 ;
     RECT  2.16 27.945 38.88 28.215 ;
     RECT  2.16 28.485 38.88 28.755 ;
     RECT  2.16 29.025 38.88 29.295 ;
     RECT  2.16 29.565 38.88 29.835 ;
     RECT  2.16 30.105 38.88 30.375 ;
     RECT  2.16 30.645 38.88 30.915 ;
     RECT  2.16 31.185 38.88 31.455 ;
     RECT  2.16 31.725 38.88 31.995 ;
     RECT  2.16 32.265 38.88 32.535 ;
     RECT  2.16 32.805 38.88 33.075 ;
     RECT  2.16 33.345 38.88 33.615 ;
     RECT  2.16 33.885 38.88 34.155 ;
     RECT  2.16 34.425 38.88 34.695 ;
     RECT  2.16 34.965 38.88 35.235 ;
     RECT  2.16 35.505 38.88 35.775 ;
     RECT  2.16 36.045 38.88 36.315 ;
     RECT  2.16 36.585 38.88 36.855 ;
     RECT  2.16 37.125 38.88 37.395 ;
     RECT  2.16 37.665 38.88 37.935 ;
     RECT  2.16 38.205 38.88 38.475 ;
     RECT  2.16 38.745 38.88 39.015 ;
     RECT  2.16 39.285 38.88 39.555 ;
     RECT  2.16 39.825 38.88 40.095 ;
     RECT  2.16 40.365 38.88 40.635 ;
     RECT  2.16 40.905 38.88 41.04 ;
    LAYER RVTP ;
     RECT  2.16 2.295 38.88 2.565 ;
     RECT  2.16 2.835 38.88 3.105 ;
     RECT  2.16 3.375 38.88 3.645 ;
     RECT  2.16 3.915 38.88 4.185 ;
     RECT  2.16 4.455 38.88 4.725 ;
     RECT  2.16 4.995 38.88 5.265 ;
     RECT  2.16 5.535 38.88 5.805 ;
     RECT  2.16 6.075 38.88 6.345 ;
     RECT  2.16 6.615 38.88 6.885 ;
     RECT  2.16 7.155 38.88 7.425 ;
     RECT  2.16 7.695 38.88 7.965 ;
     RECT  2.16 8.235 38.88 8.505 ;
     RECT  2.16 8.775 38.88 9.045 ;
     RECT  2.16 9.315 38.88 9.585 ;
     RECT  2.16 9.855 38.88 10.125 ;
     RECT  2.16 10.395 38.88 10.665 ;
     RECT  2.16 10.935 38.88 11.205 ;
     RECT  2.16 11.475 38.88 11.745 ;
     RECT  2.16 12.015 38.88 12.285 ;
     RECT  2.16 12.555 38.88 12.825 ;
     RECT  2.16 13.095 38.88 13.365 ;
     RECT  2.16 13.635 38.88 13.905 ;
     RECT  2.16 14.175 38.88 14.445 ;
     RECT  2.16 14.715 38.88 14.985 ;
     RECT  2.16 15.255 38.88 15.525 ;
     RECT  2.16 15.795 38.88 16.065 ;
     RECT  2.16 16.335 38.88 16.605 ;
     RECT  2.16 16.875 38.88 17.145 ;
     RECT  2.16 17.415 38.88 17.685 ;
     RECT  2.16 17.955 38.88 18.225 ;
     RECT  2.16 18.495 38.88 18.765 ;
     RECT  2.16 19.035 38.88 19.305 ;
     RECT  2.16 19.575 38.88 19.845 ;
     RECT  2.16 20.115 38.88 20.385 ;
     RECT  2.16 20.655 38.88 20.925 ;
     RECT  2.16 21.195 38.88 21.465 ;
     RECT  2.16 21.735 38.88 22.005 ;
     RECT  2.16 22.275 38.88 22.545 ;
     RECT  2.16 22.815 38.88 23.085 ;
     RECT  2.16 23.355 38.88 23.625 ;
     RECT  2.16 23.895 38.88 24.165 ;
     RECT  2.16 24.435 38.88 24.705 ;
     RECT  2.16 24.975 38.88 25.245 ;
     RECT  2.16 25.515 38.88 25.785 ;
     RECT  2.16 26.055 38.88 26.325 ;
     RECT  2.16 26.595 38.88 26.865 ;
     RECT  2.16 27.135 38.88 27.405 ;
     RECT  2.16 27.675 38.88 27.945 ;
     RECT  2.16 28.215 38.88 28.485 ;
     RECT  2.16 28.755 38.88 29.025 ;
     RECT  2.16 29.295 38.88 29.565 ;
     RECT  2.16 29.835 38.88 30.105 ;
     RECT  2.16 30.375 38.88 30.645 ;
     RECT  2.16 30.915 38.88 31.185 ;
     RECT  2.16 31.455 38.88 31.725 ;
     RECT  2.16 31.995 38.88 32.265 ;
     RECT  2.16 32.535 38.88 32.805 ;
     RECT  2.16 33.075 38.88 33.345 ;
     RECT  2.16 33.615 38.88 33.885 ;
     RECT  2.16 34.155 38.88 34.425 ;
     RECT  2.16 34.695 38.88 34.965 ;
     RECT  2.16 35.235 38.88 35.505 ;
     RECT  2.16 35.775 38.88 36.045 ;
     RECT  2.16 36.315 38.88 36.585 ;
     RECT  2.16 36.855 38.88 37.125 ;
     RECT  2.16 37.395 38.88 37.665 ;
     RECT  2.16 37.935 38.88 38.205 ;
     RECT  2.16 38.475 38.88 38.745 ;
     RECT  2.16 39.015 38.88 39.285 ;
     RECT  2.16 39.555 38.88 39.825 ;
     RECT  2.16 40.095 38.88 40.365 ;
     RECT  2.16 40.635 38.88 40.905 ;
    LAYER M1 ;
     RECT  2.16 2.151 38.88 41.049 ;
    LAYER M2 ;
     RECT  0.067 6.012 0.103 6.03 ;
     RECT  0.103 5.472 0.139 6.03 ;
     RECT  0.103 14.958 0.139 14.976 ;
     RECT  0.067 1.881 0.167 1.899 ;
     RECT  0.103 26.766 0.203 26.784 ;
     RECT  0.103 13.104 0.211 13.662 ;
     RECT  0.139 4.968 0.239 6.03 ;
     RECT  0.139 14.958 0.239 15.354 ;
     RECT  0.139 30.996 0.239 31.014 ;
     RECT  0.211 17.496 0.311 17.514 ;
     RECT  0.463 38.106 0.499 38.124 ;
     RECT  0.499 38.106 0.535 38.574 ;
     RECT  0.535 22.788 0.571 23.112 ;
     RECT  0.239 5.076 0.823 6.03 ;
     RECT  0.571 22.752 1.399 23.112 ;
     RECT  0.823 5.076 1.723 6.3 ;
     RECT  1.399 22.752 1.723 23.724 ;
     RECT  1.723 4.932 1.903 6.3 ;
     RECT  1.903 4.464 1.975 6.3 ;
     RECT  1.975 4.464 2.16 6.408 ;
     RECT  1.723 7.362 2.16 7.38 ;
     RECT  0.211 13.104 2.16 14.004 ;
     RECT  1.435 20.466 2.16 20.484 ;
     RECT  0.535 21.546 2.16 21.564 ;
     RECT  1.723 22.626 2.16 23.724 ;
     RECT  0.535 31.806 2.16 31.824 ;
     RECT  0.535 37.476 2.16 38.574 ;
     RECT  1.111 40.176 2.16 40.194 ;
     RECT  2.16 2.151 2.263 41.049 ;
     RECT  2.263 2.151 2.839 41.094 ;
     RECT  2.839 2.151 5.683 41.319 ;
     RECT  5.683 2.106 6.503 41.319 ;
     RECT  6.503 2.151 7.043 41.319 ;
     RECT  7.043 2.151 8.527 41.049 ;
     RECT  8.527 2.106 10.867 41.049 ;
     RECT  10.867 2.034 12.407 41.049 ;
     RECT  12.407 2.106 14.783 41.049 ;
     RECT  14.783 2.151 18.895 41.049 ;
     RECT  18.895 2.106 20.003 41.049 ;
     RECT  20.003 2.151 38.88 41.049 ;
     RECT  38.88 3.96 39.371 5.328 ;
     RECT  39.371 3.96 39.407 3.978 ;
     RECT  39.371 5.04 39.695 5.328 ;
     RECT  39.695 5.31 40.019 5.328 ;
    LAYER M3 ;
     RECT  2.808 0.091 2.826 0.269 ;
     RECT  24.48 0.091 24.498 0.365 ;
     RECT  37.08 0.619 37.098 1.003 ;
     RECT  12.564 0.571 12.582 1.099 ;
     RECT  17.64 0.523 17.658 1.099 ;
     RECT  39.996 0.091 40.014 1.099 ;
     RECT  0.108 1.195 0.126 1.579 ;
     RECT  3.996 1.099 4.014 1.723 ;
     RECT  12.564 1.099 13.05 1.723 ;
     RECT  14.832 0.571 14.85 1.723 ;
     RECT  17.64 1.099 18.198 1.723 ;
     RECT  19.944 1.099 19.962 1.723 ;
     RECT  31.968 1.147 31.986 1.723 ;
     RECT  35.964 1.099 35.982 1.723 ;
     RECT  37.08 1.003 37.386 1.723 ;
     RECT  7.956 1.723 9.882 1.771 ;
     RECT  11.412 1.723 11.826 1.771 ;
     RECT  12.564 1.723 20.718 1.771 ;
     RECT  21.528 1.723 21.546 1.771 ;
     RECT  22.86 1.723 23.706 1.771 ;
     RECT  24.84 1.723 28.062 1.771 ;
     RECT  28.908 1.723 30.438 1.771 ;
     RECT  24.768 1.771 30.438 1.819 ;
     RECT  31.212 1.723 38.178 1.819 ;
     RECT  0.108 1.579 0.198 1.876 ;
     RECT  7.956 1.771 23.85 2.011 ;
     RECT  5.364 0.091 5.382 2.101 ;
     RECT  6.732 1.723 7.038 2.101 ;
     RECT  0.072 1.876 0.198 2.107 ;
     RECT  24.768 1.819 38.178 2.107 ;
     RECT  7.956 2.011 23.994 2.143 ;
     RECT  24.768 2.107 38.43 2.143 ;
     RECT  3.384 1.723 4.014 2.155 ;
     RECT  5.364 2.101 5.706 2.155 ;
     RECT  2.415 2.143 2.505 2.191 ;
     RECT  3.384 2.155 5.706 2.191 ;
     RECT  6.48 2.101 7.038 2.191 ;
     RECT  7.815 2.143 38.43 2.191 ;
     RECT  2.415 2.191 38.43 2.251 ;
     RECT  39.348 1.099 40.014 2.251 ;
     RECT  2.415 2.251 40.014 2.395 ;
     RECT  0.072 2.107 0.846 2.635 ;
     RECT  1.98 2.395 40.014 3.883 ;
     RECT  1.728 3.883 40.014 4.721 ;
     RECT  0.072 2.635 0.918 4.733 ;
     RECT  39.672 4.721 40.014 5.063 ;
     RECT  1.728 4.721 38.79 5.261 ;
     RECT  39.996 5.063 40.014 5.333 ;
     RECT  0.072 4.733 0.846 6.029 ;
     RECT  0.072 6.029 0.09 6.035 ;
     RECT  0.828 6.029 0.846 6.305 ;
     RECT  1.728 5.261 38.646 6.539 ;
     RECT  0.144 7.051 0.162 7.181 ;
     RECT  1.728 6.539 38.61 7.385 ;
     RECT  2.304 7.385 38.61 8.339 ;
     RECT  2.34 8.339 38.61 8.401 ;
     RECT  2.34 8.401 38.754 8.501 ;
     RECT  2.376 8.501 38.754 9.661 ;
     RECT  2.34 9.661 38.754 9.823 ;
     RECT  0.144 8.539 0.162 11.083 ;
     RECT  2.304 9.823 38.754 11.659 ;
     RECT  0.108 11.083 0.162 11.755 ;
     RECT  0.108 11.755 0.342 11.933 ;
     RECT  0.108 11.933 0.126 12.667 ;
     RECT  0.108 12.667 0.162 13.243 ;
     RECT  0.108 13.243 0.342 13.373 ;
     RECT  2.268 11.659 38.754 13.829 ;
     RECT  0.108 13.373 0.234 14.045 ;
     RECT  0.144 14.045 0.234 14.827 ;
     RECT  0.144 14.827 0.342 14.953 ;
     RECT  0.108 14.953 0.342 15.005 ;
     RECT  0.144 15.005 0.234 15.869 ;
     RECT  0.216 15.869 0.234 15.917 ;
     RECT  0.144 16.699 0.162 17.213 ;
     RECT  1.116 17.083 1.134 17.213 ;
     RECT  0.216 17.227 0.234 17.467 ;
     RECT  0.216 17.467 0.306 17.519 ;
     RECT  0.216 17.519 0.234 17.549 ;
     RECT  2.304 13.829 38.754 17.752 ;
     RECT  2.268 17.752 38.754 17.789 ;
     RECT  0.324 18.283 0.342 18.461 ;
     RECT  0.18 18.859 0.198 19.085 ;
     RECT  1.44 18.187 1.458 19.387 ;
     RECT  2.304 17.789 38.754 19.387 ;
     RECT  1.44 19.387 38.754 19.771 ;
     RECT  0.144 20.347 0.162 20.477 ;
     RECT  1.404 19.771 38.754 21.259 ;
     RECT  0.18 20.731 0.198 21.541 ;
     RECT  1.224 21.259 38.754 21.541 ;
     RECT  0.18 21.541 38.754 21.643 ;
     RECT  0.144 21.643 38.754 21.821 ;
     RECT  1.152 21.821 38.754 22.205 ;
     RECT  0.144 21.821 0.162 22.637 ;
     RECT  1.404 22.205 38.754 22.649 ;
     RECT  0.54 22.699 0.594 22.987 ;
     RECT  1.404 22.649 1.422 22.987 ;
     RECT  2.304 22.649 38.754 23.009 ;
     RECT  0.54 22.987 1.422 23.117 ;
     RECT  2.376 23.009 38.754 23.459 ;
     RECT  0.54 23.117 0.558 23.515 ;
     RECT  2.376 23.459 38.718 23.585 ;
     RECT  1.404 23.117 1.422 23.729 ;
     RECT  0.144 23.515 0.558 23.837 ;
     RECT  2.415 23.585 38.718 24.233 ;
     RECT  2.415 24.233 38.574 24.859 ;
     RECT  2.304 24.859 38.574 25.007 ;
     RECT  0.144 23.837 0.162 25.147 ;
     RECT  0.144 25.147 0.342 25.517 ;
     RECT  0.216 25.517 0.342 25.901 ;
     RECT  2.415 25.007 38.574 26.015 ;
     RECT  0.324 25.901 0.342 26.093 ;
     RECT  2.415 26.015 21.366 26.095 ;
     RECT  2.376 26.095 21.366 26.203 ;
     RECT  2.304 26.203 21.366 26.401 ;
     RECT  2.268 26.401 21.366 26.477 ;
     RECT  0.144 26.635 0.198 26.761 ;
     RECT  2.304 26.477 21.366 26.797 ;
     RECT  22.104 26.015 38.574 26.797 ;
     RECT  0.108 26.761 0.198 27.053 ;
     RECT  0.144 27.053 0.198 27.101 ;
     RECT  0.144 27.101 0.162 28.109 ;
     RECT  0.216 28.171 0.234 28.349 ;
     RECT  2.304 26.797 38.574 28.823 ;
     RECT  2.304 28.823 38.538 29.069 ;
     RECT  16.2 29.069 38.538 29.399 ;
     RECT  0.144 29.659 0.162 29.789 ;
     RECT  16.2 29.399 38.286 29.839 ;
     RECT  2.304 29.069 15.21 29.875 ;
     RECT  16.128 29.839 38.286 29.875 ;
     RECT  2.304 29.875 38.286 30.235 ;
     RECT  2.268 30.235 38.286 30.299 ;
     RECT  2.268 30.299 23.238 30.479 ;
     RECT  24.015 30.299 38.286 30.721 ;
     RECT  2.304 30.479 23.238 30.941 ;
     RECT  0.144 30.763 0.162 30.955 ;
     RECT  0.144 30.955 0.234 31.019 ;
     RECT  0.144 31.019 0.162 31.037 ;
     RECT  22.356 30.941 23.238 31.099 ;
     RECT  24.015 30.721 38.538 31.099 ;
     RECT  22.356 31.099 38.538 31.109 ;
     RECT  28.26 31.109 38.538 31.253 ;
     RECT  2.304 30.941 21.438 31.325 ;
     RECT  28.296 31.253 38.538 31.373 ;
     RECT  22.356 31.109 27.486 31.693 ;
     RECT  28.476 31.373 38.538 31.721 ;
     RECT  0.54 31.801 0.558 31.819 ;
     RECT  22.248 31.693 27.486 31.901 ;
     RECT  22.248 31.901 26.766 31.927 ;
     RECT  2.34 31.325 21.438 31.963 ;
     RECT  22.212 31.927 26.766 31.963 ;
     RECT  2.34 31.963 26.766 32.071 ;
     RECT  0.252 31.819 0.558 32.237 ;
     RECT  0.252 32.237 0.27 32.285 ;
     RECT  2.304 32.071 26.766 32.347 ;
     RECT  28.476 31.721 38.286 32.369 ;
     RECT  2.196 32.347 26.766 32.573 ;
     RECT  2.268 32.573 26.766 32.881 ;
     RECT  28.476 32.369 38.25 32.909 ;
     RECT  31.356 32.909 38.25 32.999 ;
     RECT  2.268 32.881 26.982 33.08 ;
     RECT  2.268 33.08 26.946 33.197 ;
     RECT  28.476 32.909 30.546 33.211 ;
     RECT  28.224 33.211 30.546 33.269 ;
     RECT  2.304 33.197 26.946 33.377 ;
     RECT  2.304 33.377 25.542 33.449 ;
     RECT  26.28 33.377 26.946 33.539 ;
     RECT  28.296 33.269 30.546 33.539 ;
     RECT  29.016 33.539 30.546 33.719 ;
     RECT  31.356 32.999 37.818 33.961 ;
     RECT  2.415 33.449 25.542 34.079 ;
     RECT  29.052 33.719 30.366 34.079 ;
     RECT  31.356 33.961 38.214 34.079 ;
     RECT  29.052 34.079 30.258 34.157 ;
     RECT  2.415 34.079 25.47 34.205 ;
     RECT  28.044 34.231 28.062 34.349 ;
     RECT  2.415 34.205 25.362 34.501 ;
     RECT  26.28 33.539 26.874 34.555 ;
     RECT  27.9 34.357 27.918 34.589 ;
     RECT  0.144 33.979 0.162 34.685 ;
     RECT  26.208 34.555 26.874 34.771 ;
     RECT  2.304 34.501 25.362 34.925 ;
     RECT  26.208 34.771 27.09 34.933 ;
     RECT  31.356 34.079 37.818 34.961 ;
     RECT  31.356 34.961 37.602 34.997 ;
     RECT  34.056 34.997 37.602 35.033 ;
     RECT  29.304 34.157 30.258 35.041 ;
     RECT  29.124 35.041 30.258 35.131 ;
     RECT  26.208 34.933 27.162 35.159 ;
     RECT  34.416 35.033 37.602 35.159 ;
     RECT  34.416 35.159 37.062 35.165 ;
     RECT  26.604 35.159 27.162 35.231 ;
     RECT  18.072 34.925 25.362 35.267 ;
     RECT  26.604 35.231 27.126 35.303 ;
     RECT  34.452 35.165 37.062 35.309 ;
     RECT  26.604 35.303 26.622 35.339 ;
     RECT  18.072 35.267 25.146 35.429 ;
     RECT  36.108 35.309 36.27 35.429 ;
     RECT  37.044 35.309 37.062 35.429 ;
     RECT  36.108 35.429 36.126 35.465 ;
     RECT  18.072 35.429 25.11 35.699 ;
     RECT  31.356 34.997 33.318 35.699 ;
     RECT  18.252 35.699 24.966 35.735 ;
     RECT  34.452 35.309 35.097 35.947 ;
     RECT  33.012 35.699 33.318 35.969 ;
     RECT  34.092 35.947 35.097 36.005 ;
     RECT  2.304 34.925 17.334 36.013 ;
     RECT  18.252 35.735 24.297 36.041 ;
     RECT  29.088 35.131 30.258 36.091 ;
     RECT  31.356 35.699 32.274 36.091 ;
     RECT  33.012 35.969 33.03 36.125 ;
     RECT  29.088 36.091 32.274 36.149 ;
     RECT  29.124 36.149 32.274 36.239 ;
     RECT  26.784 36.121 26.802 36.383 ;
     RECT  18.252 36.041 22.734 36.509 ;
     RECT  23.508 36.041 24.297 36.509 ;
     RECT  29.124 36.239 31.374 36.509 ;
     RECT  2.304 36.013 17.478 36.553 ;
     RECT  18.252 36.509 22.59 36.553 ;
     RECT  34.452 36.005 35.097 36.581 ;
     RECT  29.124 36.509 31.266 36.653 ;
     RECT  29.415 36.653 31.266 36.689 ;
     RECT  2.304 36.553 22.59 36.797 ;
     RECT  2.415 36.797 22.59 36.923 ;
     RECT  13.104 36.923 22.59 36.959 ;
     RECT  13.176 36.959 22.59 37.037 ;
     RECT  13.176 37.037 22.446 37.049 ;
     RECT  0.144 35.467 0.162 37.471 ;
     RECT  2.415 36.923 12.294 37.669 ;
     RECT  2.376 37.669 12.294 37.705 ;
     RECT  13.176 37.049 21.366 37.705 ;
     RECT  2.376 37.705 21.366 37.723 ;
     RECT  2.304 37.723 21.366 37.769 ;
     RECT  0.144 37.471 0.558 37.853 ;
     RECT  22.14 37.049 22.446 37.939 ;
     RECT  2.376 37.769 21.366 37.967 ;
     RECT  20.7 37.967 21.366 37.975 ;
     RECT  22.104 37.939 22.446 37.975 ;
     RECT  2.376 37.967 19.962 38.129 ;
     RECT  20.7 37.975 22.446 38.165 ;
     RECT  18.612 38.129 19.962 38.237 ;
     RECT  20.736 38.165 22.446 38.273 ;
     RECT  2.376 38.129 17.874 38.399 ;
     RECT  20.736 38.273 20.754 38.399 ;
     RECT  21.96 38.273 22.086 38.399 ;
     RECT  2.376 38.399 17.298 38.435 ;
     RECT  21.96 38.399 21.978 38.435 ;
     RECT  0.468 37.853 0.558 38.479 ;
     RECT  2.376 38.435 16.902 38.507 ;
     RECT  18.615 38.237 19.962 38.507 ;
     RECT  2.376 38.507 16.542 38.515 ;
     RECT  2.304 38.515 16.542 38.543 ;
     RECT  19.944 38.507 19.962 38.579 ;
     RECT  2.304 38.543 15.606 38.669 ;
     RECT  16.524 38.543 16.542 38.669 ;
     RECT  15.408 38.669 15.426 38.705 ;
     RECT  30.816 36.689 31.266 38.765 ;
     RECT  0.468 38.479 0.846 39.067 ;
     RECT  29.415 36.689 29.697 39.355 ;
     RECT  29.415 39.355 30.366 39.479 ;
     RECT  31.248 38.765 31.266 39.479 ;
     RECT  2.304 38.669 14.238 39.739 ;
     RECT  0.144 39.067 0.846 40.171 ;
     RECT  1.728 39.739 14.238 40.171 ;
     RECT  0.144 40.171 14.238 40.541 ;
     RECT  2.268 40.541 14.238 40.559 ;
     RECT  30.492 39.631 30.51 40.559 ;
     RECT  2.268 40.559 11.43 40.595 ;
     RECT  29.415 39.479 29.697 40.711 ;
     RECT  12.168 40.559 14.238 40.739 ;
     RECT  18.615 38.507 18.897 40.787 ;
     RECT  24.015 36.509 24.297 40.787 ;
     RECT  34.815 36.581 35.097 40.787 ;
     RECT  0.144 40.541 1.134 40.829 ;
     RECT  2.268 40.595 11.25 40.829 ;
     RECT  12.384 40.739 14.238 40.829 ;
     RECT  29.415 40.711 30.222 40.829 ;
     RECT  2.268 40.829 11.106 40.865 ;
     RECT  12.384 40.829 12.402 40.865 ;
     RECT  13.14 40.829 14.238 40.865 ;
     RECT  2.268 40.865 9.63 40.901 ;
     RECT  0.144 40.829 0.846 40.925 ;
     RECT  5.112 40.901 8.694 40.925 ;
     RECT  9.612 40.901 9.63 40.925 ;
     RECT  5.148 40.925 8.694 40.937 ;
     RECT  10.584 40.865 10.602 40.937 ;
     RECT  13.176 40.865 13.305 40.937 ;
     RECT  2.268 40.901 3.942 40.973 ;
     RECT  5.364 40.937 8.694 40.973 ;
     RECT  5.364 40.973 5.958 41.009 ;
     RECT  5.364 41.009 5.706 41.021 ;
     RECT  6.732 40.973 7.905 41.057 ;
     RECT  13.215 40.937 13.305 41.057 ;
     RECT  18.615 40.787 18.705 41.057 ;
     RECT  24.015 40.787 24.105 41.057 ;
     RECT  29.415 40.829 30.078 41.057 ;
     RECT  34.815 40.787 34.905 41.057 ;
     RECT  2.268 40.973 2.862 41.099 ;
     RECT  6.732 41.057 7.614 41.117 ;
     RECT  2.304 41.099 2.862 41.213 ;
     RECT  3.708 40.973 3.942 41.357 ;
     RECT  0.828 40.925 0.846 41.501 ;
     RECT  3.924 41.357 3.942 41.597 ;
     RECT  5.364 41.021 5.382 41.741 ;
     RECT  6.732 41.117 7.434 41.885 ;
     RECT  2.844 41.213 2.862 42.029 ;
     RECT  7.416 41.885 7.434 42.173 ;
     RECT  30.06 41.057 30.078 43.085 ;
    LAYER M4 ;
     RECT  0.06 1.056 0.419 42.168 ;
     RECT  0.419 1.056 0.611 1.08 ;
     RECT  0.419 2.112 0.857 42.168 ;
     RECT  0.857 2.304 2.408 42.168 ;
     RECT  2.389 0.144 2.533 0.168 ;
     RECT  2.533 0.144 2.677 0.216 ;
     RECT  2.677 0.144 2.78 0.36 ;
     RECT  2.78 0.096 2.867 0.36 ;
     RECT  2.867 0.144 2.869 0.36 ;
     RECT  2.869 0.144 3.011 0.456 ;
     RECT  3.011 0.24 3.059 0.264 ;
     RECT  2.408 2.148 3.329 42.168 ;
     RECT  3.329 1.728 3.413 42.168 ;
     RECT  3.413 2.16 4.025 42.168 ;
     RECT  3.985 1.104 4.355 1.128 ;
     RECT  4.025 2.16 4.933 17.688 ;
     RECT  4.933 2.208 4.993 17.688 ;
     RECT  4.025 18.72 4.993 42.168 ;
     RECT  4.993 2.208 5.123 42.168 ;
     RECT  5.269 0.144 5.353 0.168 ;
     RECT  5.353 0.096 5.437 0.168 ;
     RECT  5.437 0.144 5.699 0.168 ;
     RECT  5.123 2.256 6.565 42.168 ;
     RECT  6.565 1.728 6.761 42.168 ;
     RECT  6.761 42.144 7.445 42.168 ;
     RECT  6.761 1.728 7.625 41.112 ;
     RECT  7.625 1.728 7.912 41.052 ;
     RECT  7.957 0.144 8.053 0.168 ;
     RECT  8.053 0.144 8.291 0.216 ;
     RECT  8.291 0.192 8.483 0.216 ;
     RECT  7.912 1.728 8.633 40.968 ;
     RECT  8.633 35.424 8.705 40.968 ;
     RECT  8.705 35.424 9.353 40.92 ;
     RECT  9.353 39.072 9.641 40.92 ;
     RECT  8.633 1.728 9.749 34.44 ;
     RECT  9.749 29.04 10.069 34.44 ;
     RECT  9.353 35.424 10.069 37.704 ;
     RECT  9.641 39.072 10.145 40.44 ;
     RECT  10.145 40.416 10.325 40.44 ;
     RECT  10.145 39.072 10.537 39.336 ;
     RECT  10.069 29.04 10.717 37.704 ;
     RECT  10.537 38.928 10.717 39.336 ;
     RECT  10.717 29.04 10.829 39.336 ;
     RECT  9.749 1.728 10.969 27.816 ;
     RECT  10.829 29.04 11.225 39.096 ;
     RECT  10.717 40.56 11.441 40.584 ;
     RECT  11.225 33.264 11.513 39.096 ;
     RECT  11.513 33.792 11.549 39.096 ;
     RECT  10.969 1.728 11.653 27.96 ;
     RECT  11.225 29.04 11.653 31.752 ;
     RECT  11.549 36.912 12.161 39.096 ;
     RECT  12.161 37.968 12.445 39.096 ;
     RECT  11.653 1.728 12.481 31.752 ;
     RECT  12.445 37.968 12.517 39.624 ;
     RECT  12.509 0.576 12.593 0.6 ;
     RECT  11.549 33.792 12.841 35.784 ;
     RECT  12.161 36.912 12.841 36.936 ;
     RECT  12.481 1.728 13.004 32.472 ;
     RECT  13.004 1.104 13.091 32.472 ;
     RECT  13.091 1.728 13.093 32.472 ;
     RECT  12.841 33.792 13.093 36.936 ;
     RECT  13.093 1.728 13.208 36.936 ;
     RECT  12.517 37.968 13.208 40.488 ;
     RECT  13.208 1.728 13.312 41.052 ;
     RECT  13.312 1.728 13.504 40.782 ;
     RECT  13.504 14.4 13.637 38.664 ;
     RECT  13.637 14.448 13.709 38.664 ;
     RECT  13.709 35.424 13.853 38.664 ;
     RECT  13.709 14.448 13.948 34.44 ;
     RECT  13.948 14.448 14.099 28.536 ;
     RECT  14.099 14.448 14.249 27.192 ;
     RECT  14.249 14.448 14.321 15.24 ;
     RECT  13.853 35.424 14.393 38.184 ;
     RECT  13.504 4.08 14.485 13.272 ;
     RECT  14.249 16.368 14.537 27.192 ;
     RECT  14.321 14.592 14.573 15.24 ;
     RECT  14.393 36.912 14.645 38.184 ;
     RECT  13.504 1.728 14.677 2.856 ;
     RECT  14.485 3.984 14.677 13.272 ;
     RECT  14.677 1.728 14.723 13.272 ;
     RECT  13.948 29.856 14.785 34.44 ;
     RECT  14.393 35.424 14.785 35.928 ;
     RECT  14.537 16.368 14.861 27.144 ;
     RECT  14.821 0.576 14.905 0.6 ;
     RECT  14.723 2.832 15.193 13.272 ;
     RECT  14.099 28.512 15.317 28.536 ;
     RECT  14.785 29.856 15.317 35.928 ;
     RECT  15.317 28.512 15.329 35.928 ;
     RECT  15.193 3.984 15.401 13.272 ;
     RECT  14.645 37.968 15.437 38.184 ;
     RECT  14.573 14.592 15.901 15.048 ;
     RECT  15.437 37.968 15.977 37.992 ;
     RECT  15.329 28.512 16.117 35.784 ;
     RECT  14.645 36.912 16.333 36.936 ;
     RECT  15.401 3.984 16.477 13.224 ;
     RECT  15.901 14.352 16.477 15.048 ;
     RECT  16.117 27.888 16.585 35.784 ;
     RECT  16.333 36.912 16.585 37.752 ;
     RECT  14.723 1.728 16.652 1.8 ;
     RECT  15.193 2.832 16.652 2.952 ;
     RECT  16.585 27.888 16.733 37.752 ;
     RECT  16.652 1.728 16.739 2.952 ;
     RECT  16.739 2.88 16.945 2.952 ;
     RECT  16.477 3.984 16.945 15.048 ;
     RECT  16.945 2.88 17.021 15.048 ;
     RECT  17.021 3.552 17.075 15.048 ;
     RECT  16.733 28.464 17.165 37.752 ;
     RECT  14.861 16.368 17.341 26.664 ;
     RECT  17.165 28.464 17.345 35.784 ;
     RECT  17.075 3.84 17.489 15.048 ;
     RECT  17.341 16.368 17.633 27.096 ;
     RECT  17.612 0.528 17.699 0.552 ;
     RECT  17.165 36.912 17.701 37.752 ;
     RECT  17.633 20.544 17.797 27.096 ;
     RECT  17.489 3.84 18.085 14.232 ;
     RECT  16.739 1.728 18.169 1.848 ;
     RECT  17.797 20.544 18.313 27.384 ;
     RECT  17.345 28.512 18.313 35.784 ;
     RECT  18.169 1.104 18.469 1.848 ;
     RECT  18.469 1.104 18.608 1.896 ;
     RECT  18.085 2.88 18.608 14.232 ;
     RECT  18.133 15.264 18.608 15.288 ;
     RECT  17.633 16.368 18.608 19.32 ;
     RECT  18.313 20.544 18.608 35.784 ;
     RECT  17.701 36.912 18.608 38.232 ;
     RECT  18.608 1.104 18.659 41.052 ;
     RECT  18.659 1.728 18.712 41.052 ;
     RECT  18.712 1.728 18.904 40.782 ;
     RECT  18.904 36.912 18.929 37.08 ;
     RECT  18.904 18.72 19.001 19.32 ;
     RECT  18.904 25.008 19.505 35.832 ;
     RECT  19.505 25.008 19.541 26.664 ;
     RECT  19.505 27.648 19.541 35.832 ;
     RECT  19.541 28.128 19.577 35.832 ;
     RECT  18.904 38.208 19.829 38.232 ;
     RECT  18.904 1.728 19.916 17.688 ;
     RECT  19.916 1.104 20.003 17.688 ;
     RECT  19.001 18.768 20.005 19.32 ;
     RECT  18.904 20.304 20.005 20.712 ;
     RECT  20.003 1.728 20.045 17.688 ;
     RECT  20.005 18.768 20.185 20.712 ;
     RECT  20.185 18.72 20.245 20.712 ;
     RECT  18.904 21.696 20.245 23.928 ;
     RECT  20.045 13.584 20.387 17.688 ;
     RECT  18.929 36.912 20.405 36.984 ;
     RECT  20.045 1.728 20.435 12.552 ;
     RECT  20.387 14.352 20.437 17.688 ;
     RECT  20.245 18.72 20.437 23.928 ;
     RECT  19.541 25.008 20.437 25.224 ;
     RECT  19.577 28.128 20.581 35.784 ;
     RECT  20.437 14.352 20.627 25.224 ;
     RECT  20.627 16.368 20.653 25.224 ;
     RECT  19.541 26.208 20.653 26.664 ;
     RECT  20.581 28.128 20.869 36.6 ;
     RECT  20.869 27.888 20.873 36.6 ;
     RECT  20.653 16.368 20.905 26.664 ;
     RECT  20.873 27.888 20.905 35.784 ;
     RECT  20.627 14.352 21.197 15.192 ;
     RECT  20.905 16.368 21.395 35.784 ;
     RECT  21.395 27.936 21.485 35.784 ;
     RECT  21.197 14.544 21.805 15.192 ;
     RECT  21.805 14.544 21.989 15.384 ;
     RECT  20.435 1.728 22.069 12.36 ;
     RECT  22.069 1.728 22.097 10.584 ;
     RECT  22.069 12 22.165 12.36 ;
     RECT  21.989 15.168 22.201 15.384 ;
     RECT  21.395 16.368 22.201 26.664 ;
     RECT  22.165 12 22.313 12.552 ;
     RECT  22.313 12.336 22.417 12.552 ;
     RECT  22.097 1.728 22.451 10.296 ;
     RECT  21.373 37.008 22.601 37.032 ;
     RECT  22.201 15.168 22.636 26.664 ;
     RECT  21.485 28.224 22.652 35.784 ;
     RECT  22.652 27.84 22.739 35.784 ;
     RECT  22.417 12.336 22.817 12.936 ;
     RECT  22.636 15.168 22.853 17.112 ;
     RECT  22.636 18.144 22.853 26.664 ;
     RECT  22.853 15.168 23.245 16.872 ;
     RECT  22.451 1.728 23.785 10.2 ;
     RECT  22.853 18.144 23.852 26.568 ;
     RECT  23.785 1.728 24.008 10.824 ;
     RECT  22.817 12.48 24.008 12.936 ;
     RECT  23.245 14.64 24.008 16.872 ;
     RECT  23.852 18.144 24.008 26.664 ;
     RECT  22.739 27.888 24.008 35.784 ;
     RECT  24.008 1.728 24.112 41.052 ;
     RECT  24.133 0.336 24.277 0.36 ;
     RECT  24.112 1.728 24.304 40.782 ;
     RECT  24.277 0.24 24.418 0.36 ;
     RECT  24.304 26.256 24.419 35.448 ;
     RECT  24.304 8.976 24.437 12.504 ;
     RECT  24.418 0.096 24.509 0.36 ;
     RECT  24.304 2.88 24.509 7.464 ;
     RECT  24.304 14.64 24.515 25.224 ;
     RECT  24.509 3.072 24.545 7.464 ;
     RECT  24.509 0.336 24.553 0.36 ;
     RECT  24.545 3.936 24.689 7.464 ;
     RECT  24.515 18.192 24.755 25.224 ;
     RECT  24.689 4.416 25.049 7.464 ;
     RECT  24.419 26.256 25.229 35.256 ;
     RECT  24.304 1.728 25.297 1.848 ;
     RECT  24.437 12 25.297 12.504 ;
     RECT  24.515 14.64 25.373 16.872 ;
     RECT  25.373 14.64 25.477 15.624 ;
     RECT  24.755 18.192 25.481 20.376 ;
     RECT  25.297 1.728 25.523 1.896 ;
     RECT  25.297 12 25.523 13.032 ;
     RECT  25.481 18.192 25.525 19.512 ;
     RECT  24.755 21.6 25.621 25.224 ;
     RECT  25.585 2.88 25.669 2.904 ;
     RECT  25.477 14.496 25.717 15.624 ;
     RECT  25.621 21.6 25.717 25.272 ;
     RECT  25.229 26.256 25.717 26.76 ;
     RECT  25.477 7.728 25.724 7.896 ;
     RECT  24.437 8.976 25.724 10.344 ;
     RECT  25.717 21.6 25.763 26.76 ;
     RECT  25.724 7.728 25.811 10.344 ;
     RECT  25.229 27.744 25.985 35.256 ;
     RECT  25.811 8.976 26.005 10.344 ;
     RECT  25.763 21.744 26.093 26.568 ;
     RECT  25.985 27.744 26.129 33.144 ;
     RECT  25.523 12.912 26.165 13.032 ;
     RECT  25.717 14.304 26.195 15.624 ;
     RECT  25.049 4.416 26.197 6.312 ;
     RECT  26.165 12.912 26.345 12.984 ;
     RECT  26.197 3.648 26.381 6.312 ;
     RECT  25.373 16.848 26.381 16.872 ;
     RECT  25.765 11.856 26.453 11.88 ;
     RECT  26.345 12.912 26.453 12.936 ;
     RECT  26.195 14.496 26.485 15.624 ;
     RECT  26.093 21.744 26.489 26.472 ;
     RECT  26.489 21.744 26.531 24.12 ;
     RECT  26.005 8.976 26.597 10.824 ;
     RECT  25.523 1.728 26.701 1.848 ;
     RECT  25.525 18.192 26.705 18.216 ;
     RECT  26.701 1.728 26.785 1.896 ;
     RECT  26.381 4.512 26.809 6.312 ;
     RECT  26.809 4.512 26.819 6.6 ;
     RECT  25.811 7.728 26.845 7.896 ;
     RECT  26.597 8.976 26.845 10.152 ;
     RECT  26.819 5.328 26.857 6.6 ;
     RECT  26.485 14.496 26.921 16.488 ;
     RECT  26.857 5.904 27.277 6.6 ;
     RECT  26.845 7.728 27.277 10.152 ;
     RECT  26.531 21.744 27.317 23.64 ;
     RECT  25.525 19.488 27.421 19.512 ;
     RECT  26.921 16.32 27.457 16.488 ;
     RECT  27.421 19.488 27.461 19.944 ;
     RECT  27.565 18.24 27.709 18.264 ;
     RECT  26.489 25.632 27.781 26.472 ;
     RECT  27.781 25.104 27.853 26.472 ;
     RECT  26.129 27.744 27.853 27.912 ;
     RECT  26.129 28.896 27.877 33.144 ;
     RECT  25.985 34.128 27.877 35.256 ;
     RECT  27.277 5.904 27.929 10.152 ;
     RECT  27.461 19.92 27.997 19.944 ;
     RECT  27.997 19.92 28.069 20.376 ;
     RECT  26.869 2.88 28.105 2.952 ;
     RECT  27.929 5.904 28.105 6.888 ;
     RECT  27.853 25.104 28.105 27.912 ;
     RECT  27.877 28.896 28.105 35.256 ;
     RECT  27.317 21.984 28.213 23.64 ;
     RECT  28.069 19.92 28.217 20.952 ;
     RECT  27.929 7.872 28.309 10.152 ;
     RECT  27.709 18.24 28.357 18.696 ;
     RECT  28.217 20.928 28.393 20.952 ;
     RECT  28.213 21.984 28.393 23.688 ;
     RECT  28.105 25.104 28.405 35.256 ;
     RECT  26.921 14.496 28.429 14.52 ;
     RECT  28.105 5.616 28.433 6.888 ;
     RECT  28.393 20.928 28.433 23.688 ;
     RECT  28.309 7.872 28.453 10.872 ;
     RECT  28.429 14.496 28.597 14.76 ;
     RECT  27.457 16.32 28.597 16.584 ;
     RECT  28.357 17.616 28.609 18.696 ;
     RECT  26.785 1.728 28.861 1.8 ;
     RECT  28.453 7.872 28.885 11.64 ;
     RECT  28.405 25.104 28.969 25.128 ;
     RECT  28.609 17.616 29.185 18.744 ;
     RECT  28.105 2.88 29.249 3.432 ;
     RECT  28.861 1.728 29.329 1.848 ;
     RECT  29.249 2.88 29.329 4.008 ;
     RECT  28.597 14.496 29.365 16.584 ;
     RECT  29.329 1.728 29.408 4.008 ;
     RECT  28.433 5.856 29.408 6.888 ;
     RECT  28.885 7.872 29.408 12.552 ;
     RECT  29.365 14.208 29.408 16.584 ;
     RECT  29.185 17.616 29.408 18.84 ;
     RECT  28.217 19.92 29.408 19.944 ;
     RECT  28.433 20.928 29.408 23.64 ;
     RECT  28.969 24.912 29.408 25.128 ;
     RECT  28.405 26.4 29.408 35.256 ;
     RECT  29.408 1.728 29.512 41.052 ;
     RECT  29.512 1.728 29.704 40.782 ;
     RECT  29.704 13.968 29.843 18.6 ;
     RECT  29.704 20.448 29.909 23.64 ;
     RECT  29.704 2.88 29.981 6.792 ;
     RECT  29.843 14.208 30.089 18.6 ;
     RECT  29.909 21.984 30.089 23.64 ;
     RECT  30.089 14.928 30.233 18.6 ;
     RECT  30.049 43.056 30.323 43.08 ;
     RECT  30.233 14.928 30.341 16.92 ;
     RECT  30.233 18.576 30.521 18.6 ;
     RECT  29.981 2.88 30.601 4.68 ;
     RECT  29.704 38.832 30.707 39.384 ;
     RECT  29.704 8.208 30.733 10.632 ;
     RECT  30.707 38.832 30.741 38.856 ;
     RECT  29.704 26.64 30.755 29.352 ;
     RECT  29.704 11.952 30.769 12.504 ;
     RECT  30.741 38.736 30.803 38.856 ;
     RECT  29.704 34.464 30.805 35.256 ;
     RECT  30.755 26.64 30.809 27.864 ;
     RECT  30.755 29.232 30.809 29.352 ;
     RECT  29.704 30.576 30.809 32.904 ;
     RECT  29.981 5.856 30.845 6.792 ;
     RECT  30.803 38.736 30.845 38.76 ;
     RECT  30.769 11.952 30.853 12.552 ;
     RECT  30.809 26.64 30.881 27.768 ;
     RECT  30.757 0.144 30.899 0.168 ;
     RECT  29.704 1.728 30.901 1.8 ;
     RECT  30.733 8.064 30.917 10.632 ;
     RECT  30.601 3.936 30.949 4.68 ;
     RECT  30.845 5.856 30.949 6.744 ;
     RECT  29.909 20.448 30.949 20.664 ;
     RECT  30.917 9.792 30.985 10.632 ;
     RECT  30.949 3.936 30.989 6.744 ;
     RECT  30.881 26.64 30.989 26.664 ;
     RECT  30.809 29.328 31.165 29.352 ;
     RECT  30.901 1.728 31.189 1.848 ;
     RECT  30.089 21.984 31.237 22.152 ;
     RECT  30.089 23.616 31.237 23.64 ;
     RECT  31.189 1.728 31.277 1.896 ;
     RECT  30.985 9.792 31.313 10.824 ;
     RECT  31.277 1.728 31.331 1.848 ;
     RECT  30.341 14.928 31.333 16.536 ;
     RECT  30.949 20.448 31.333 20.712 ;
     RECT  31.237 21.984 31.333 23.64 ;
     RECT  31.333 14.928 31.345 17.112 ;
     RECT  31.345 14.928 31.417 17.496 ;
     RECT  30.917 8.064 31.493 8.52 ;
     RECT  31.417 14.832 31.601 17.496 ;
     RECT  31.453 18.768 31.633 18.792 ;
     RECT  29.704 25.056 31.705 25.08 ;
     RECT  31.333 20.448 31.717 23.832 ;
     RECT  31.705 24.96 31.741 25.08 ;
     RECT  31.633 18.576 31.745 18.792 ;
     RECT  30.989 4.656 31.849 6.744 ;
     RECT  30.601 2.88 31.861 2.904 ;
     RECT  31.717 19.872 31.861 23.832 ;
     RECT  31.741 24.96 31.861 26.04 ;
     RECT  31.601 15.072 31.907 17.496 ;
     RECT  30.805 34.464 31.909 36.12 ;
     RECT  31.493 8.496 31.921 8.52 ;
     RECT  31.313 9.792 31.921 10.248 ;
     RECT  31.909 34.224 31.955 36.12 ;
     RECT  31.331 1.728 31.957 1.8 ;
     RECT  31.861 19.872 32.033 26.04 ;
     RECT  31.957 1.152 32.041 1.8 ;
     RECT  30.809 30.576 32.06 32.856 ;
     RECT  32.033 23.808 32.069 26.04 ;
     RECT  31.921 8.496 32.141 10.248 ;
     RECT  32.141 8.496 32.213 8.52 ;
     RECT  32.069 26.016 32.213 26.04 ;
     RECT  30.853 11.952 32.245 12.504 ;
     RECT  32.141 9.792 32.249 10.248 ;
     RECT  31.907 15.216 32.281 17.496 ;
     RECT  31.745 18.576 32.281 18.6 ;
     RECT  32.033 19.872 32.285 22.824 ;
     RECT  32.245 11.424 32.329 12.504 ;
     RECT  32.285 21.168 32.501 22.824 ;
     RECT  31.861 2.88 32.533 2.952 ;
     RECT  30.881 27.744 32.641 27.768 ;
     RECT  32.281 15.216 32.681 18.6 ;
     RECT  32.533 2.88 32.713 3.432 ;
     RECT  31.849 4.656 32.713 7.464 ;
     RECT  32.069 23.808 32.717 23.832 ;
     RECT  32.641 13.632 32.749 13.656 ;
     RECT  32.06 30.576 32.78 33 ;
     RECT  31.955 34.224 32.78 34.248 ;
     RECT  31.165 29.328 32.821 29.4 ;
     RECT  32.78 30.576 32.821 34.248 ;
     RECT  32.821 29.328 32.867 34.248 ;
     RECT  32.329 11.952 32.897 12.504 ;
     RECT  32.681 16.32 32.897 18.6 ;
     RECT  32.867 29.328 32.905 32.856 ;
     RECT  32.641 26.736 32.965 27.768 ;
     RECT  32.713 2.88 33.005 7.464 ;
     RECT  32.501 21.648 33.005 22.824 ;
     RECT  31.955 35.232 33.041 36.12 ;
     RECT  32.041 1.728 33.061 1.8 ;
     RECT  33.005 2.88 33.061 4.008 ;
     RECT  32.249 10.032 33.073 10.248 ;
     RECT  33.005 5.616 33.109 7.464 ;
     RECT  33.061 1.728 33.149 4.008 ;
     RECT  32.905 30.336 33.155 32.856 ;
     RECT  33.073 10.032 33.221 10.824 ;
     RECT  33.005 22.8 33.293 22.824 ;
     RECT  32.965 26.736 33.299 27.96 ;
     RECT  33.001 18.768 33.365 18.84 ;
     RECT  33.149 2.88 33.437 4.008 ;
     RECT  32.285 19.872 33.5 19.896 ;
     RECT  33.109 5.616 33.541 8.04 ;
     RECT  32.749 13.632 33.581 14.232 ;
     RECT  33.299 26.736 33.589 27.768 ;
     RECT  33.437 3.408 33.653 4.008 ;
     RECT  33.653 3.888 33.689 4.008 ;
     RECT  32.681 15.216 33.74 15.24 ;
     RECT  32.897 16.32 33.74 17.64 ;
     RECT  33.581 13.632 33.761 13.656 ;
     RECT  33.5 19.872 33.797 19.944 ;
     RECT  33.155 30.576 33.829 32.856 ;
     RECT  32.867 34.08 33.829 34.248 ;
     RECT  32.897 11.952 33.877 11.976 ;
     RECT  33.877 11.952 33.901 12.024 ;
     RECT  33.365 18.816 33.901 18.84 ;
     RECT  33.221 10.032 33.98 10.152 ;
     RECT  33.541 5.616 34.021 8.472 ;
     RECT  33.589 26.688 34.213 27.768 ;
     RECT  33.98 9.504 34.261 10.152 ;
     RECT  33.901 11.952 34.261 12.456 ;
     RECT  33.74 15.216 34.333 17.64 ;
     RECT  33.829 30.576 34.405 34.248 ;
     RECT  33.041 35.232 34.405 35.976 ;
     RECT  34.021 5.616 34.765 8.52 ;
     RECT  34.213 26.208 34.765 27.768 ;
     RECT  33.149 1.728 34.808 1.896 ;
     RECT  33.689 3.936 34.808 4.008 ;
     RECT  34.765 5.04 34.808 8.52 ;
     RECT  34.261 9.504 34.808 10.344 ;
     RECT  34.261 11.808 34.808 12.456 ;
     RECT  34.333 14.832 34.808 17.64 ;
     RECT  33.901 18.816 34.808 18.888 ;
     RECT  33.925 20.448 34.808 20.472 ;
     RECT  33.005 21.648 34.808 21.672 ;
     RECT  34.765 26.016 34.808 27.768 ;
     RECT  32.905 29.328 34.808 29.352 ;
     RECT  34.405 30.576 34.808 35.976 ;
     RECT  34.808 1.728 34.912 41.052 ;
     RECT  34.933 0.336 35.077 0.36 ;
     RECT  34.912 1.728 35.104 40.782 ;
     RECT  35.077 0.336 35.221 0.456 ;
     RECT  35.104 30.576 35.273 34.152 ;
     RECT  35.104 2.88 35.308 6.84 ;
     RECT  35.104 9.696 35.317 10.152 ;
     RECT  35.308 2.88 35.353 4.68 ;
     RECT  35.221 0.144 35.363 0.456 ;
     RECT  35.353 4.272 35.363 4.68 ;
     RECT  35.104 12.528 35.363 12.552 ;
     RECT  35.273 30.576 35.363 32.808 ;
     RECT  35.104 7.968 35.381 8.472 ;
     RECT  35.104 25.536 35.381 26.04 ;
     RECT  35.308 5.664 35.417 6.84 ;
     RECT  35.104 29.328 35.597 29.592 ;
     RECT  35.363 31.728 35.633 32.808 ;
     RECT  35.381 26.016 35.669 26.04 ;
     RECT  35.353 2.88 35.705 3 ;
     RECT  35.104 15.456 35.747 15.48 ;
     RECT  35.104 27.6 35.749 27.96 ;
     RECT  35.705 2.976 35.795 3 ;
     RECT  35.417 6.816 35.921 6.84 ;
     RECT  35.749 27.6 35.921 27.624 ;
     RECT  35.104 1.728 35.953 1.8 ;
     RECT  35.597 29.328 35.957 29.352 ;
     RECT  35.363 4.272 36.101 4.296 ;
     RECT  35.953 1.104 36.133 1.8 ;
     RECT  35.633 32.448 36.137 32.808 ;
     RECT  36.137 32.784 36.277 32.808 ;
     RECT  35.417 5.664 36.497 5.688 ;
     RECT  35.381 7.968 36.529 7.992 ;
     RECT  36.529 7.152 36.533 7.992 ;
     RECT  35.317 9.792 36.661 10.152 ;
     RECT  36.661 9.072 36.673 10.152 ;
     RECT  35.104 35.232 36.677 35.304 ;
     RECT  36.673 8.544 36.707 10.152 ;
     RECT  36.325 19.92 36.716 19.944 ;
     RECT  36.707 8.544 36.748 9.096 ;
     RECT  36.716 19.632 36.803 19.944 ;
     RECT  36.349 26.784 36.803 26.808 ;
     RECT  36.803 19.92 36.857 19.944 ;
     RECT  36.133 1.104 36.961 1.848 ;
     RECT  36.889 3.216 37.001 3.24 ;
     RECT  36.961 1.104 37.069 1.896 ;
     RECT  36.677 35.232 37.073 35.256 ;
     RECT  36.757 5.472 37.145 5.496 ;
     RECT  37.069 0.624 37.196 1.896 ;
     RECT  35.273 34.128 37.253 34.152 ;
     RECT  36.277 32.784 37.325 33.096 ;
     RECT  36.533 7.152 37.393 7.176 ;
     RECT  36.707 10.128 37.433 10.152 ;
     RECT  37.393 6.864 37.501 7.176 ;
     RECT  37.501 6.864 37.577 7.368 ;
     RECT  35.363 30.576 37.577 30.6 ;
     RECT  37.177 4.464 37.649 4.488 ;
     RECT  36.748 8.544 37.829 8.568 ;
     RECT  37.196 0.624 38.099 2.28 ;
     RECT  38.099 1.728 38.177 2.28 ;
     RECT  38.177 1.728 38.189 2.328 ;
     RECT  37.501 5.712 38.257 5.736 ;
     RECT  38.189 2.064 38.261 2.328 ;
     RECT  38.257 5.136 38.261 5.736 ;
     RECT  37.325 32.784 38.261 32.808 ;
     RECT  37.577 7.344 38.513 7.368 ;
     RECT  38.261 5.136 38.531 5.16 ;
     RECT  38.099 0.624 39.299 0.648 ;
     RECT  38.261 2.064 39.337 2.28 ;
     RECT  39.337 1.104 39.356 2.28 ;
     RECT  39.356 1.104 39.443 2.856 ;
     RECT  39.443 1.104 39.587 2.088 ;
     RECT  38.257 3.984 39.745 4.008 ;
     RECT  39.587 1.104 39.875 1.128 ;
     RECT  39.941 0.096 40.025 0.12 ;
    LAYER M5 ;
     RECT  1.056 0.016 40.008 0.131 ;
     RECT  1.056 0.131 39.864 1.045 ;
     RECT  0.576 1.045 39.864 1.139 ;
     RECT  0.576 1.139 39.72 1.333 ;
     RECT  0.288 1.333 39.72 1.429 ;
     RECT  0.192 1.429 39.72 1.859 ;
     RECT  25.488 1.859 25.656 1.907 ;
     RECT  26.736 1.859 33.624 1.907 ;
     RECT  34.704 1.859 35.784 1.907 ;
     RECT  37.008 1.859 39.72 1.907 ;
     RECT  0.192 1.859 16.728 1.957 ;
     RECT  0.144 1.957 16.728 2.291 ;
     RECT  37.248 1.907 39.72 2.291 ;
     RECT  26.88 1.907 33.096 2.339 ;
     RECT  38.208 2.291 39.72 2.339 ;
     RECT  0.144 2.291 16.488 2.915 ;
     RECT  18.096 1.859 24.504 2.915 ;
     RECT  25.632 1.907 25.656 2.915 ;
     RECT  26.88 2.339 32.952 2.915 ;
     RECT  0.144 2.915 15.96 2.963 ;
     RECT  27.264 2.915 27.288 2.963 ;
     RECT  28.32 2.915 30.552 2.963 ;
     RECT  31.872 2.915 32.568 2.963 ;
     RECT  28.464 2.963 30.552 3.011 ;
     RECT  34.8 1.907 35.784 3.011 ;
     RECT  18.48 2.915 24.504 3.107 ;
     RECT  18.48 3.107 24.408 3.443 ;
     RECT  28.464 3.011 29.712 3.443 ;
     RECT  32.544 2.963 32.568 3.443 ;
     RECT  33.264 3.877 33.288 3.925 ;
     RECT  29.28 3.443 29.712 4.019 ;
     RECT  38.496 2.339 39.72 4.019 ;
     RECT  0.144 2.963 15.72 4.453 ;
     RECT  17.04 3.541 17.064 4.453 ;
     RECT  18.6 3.443 24.408 4.453 ;
     RECT  34.8 3.011 35.352 4.691 ;
     RECT  33.264 3.925 33.624 5.077 ;
     RECT  38.496 4.019 38.52 5.171 ;
     RECT  26.784 4.501 26.808 5.363 ;
     RECT  25.776 4.501 25.8 5.509 ;
     RECT  0.144 4.453 15.96 5.555 ;
     RECT  34.8 4.691 35.256 5.653 ;
     RECT  11.904 5.555 15.96 5.701 ;
     RECT  17.04 4.453 24.408 5.701 ;
     RECT  11.904 5.701 24.408 5.939 ;
     RECT  0.144 5.555 10.92 5.987 ;
     RECT  27.888 6.085 27.912 6.133 ;
     RECT  15.888 5.939 24.408 6.229 ;
     RECT  32.592 5.077 33.624 6.229 ;
     RECT  34.8 5.653 35.304 6.229 ;
     RECT  27.888 6.133 28.008 6.275 ;
     RECT  27.984 6.275 28.008 6.755 ;
     RECT  0.144 5.987 9.096 6.899 ;
     RECT  2.304 6.899 9.096 7.333 ;
     RECT  10.128 5.987 10.92 7.333 ;
     RECT  15.888 6.229 24.648 7.429 ;
     RECT  2.304 7.333 10.92 7.619 ;
     RECT  2.304 7.619 8.76 7.715 ;
     RECT  11.904 5.939 14.76 7.765 ;
     RECT  15.888 7.429 24.792 7.765 ;
     RECT  9.888 7.619 10.92 7.859 ;
     RECT  28.32 6.805 28.344 7.909 ;
     RECT  29.4 4.019 29.712 7.909 ;
     RECT  0.144 6.899 1.224 7.955 ;
     RECT  11.904 7.765 24.792 8.195 ;
     RECT  28.32 7.909 29.712 8.437 ;
     RECT  0.144 7.955 0.408 8.917 ;
     RECT  10.128 7.859 10.92 8.965 ;
     RECT  11.904 8.195 22.776 8.965 ;
     RECT  36.768 5.461 36.792 9.061 ;
     RECT  25.776 5.509 26.184 9.155 ;
     RECT  10.128 8.965 22.776 9.203 ;
     RECT  15.84 9.203 22.776 9.491 ;
     RECT  2.4 7.715 8.76 9.541 ;
     RECT  10.128 9.203 14.808 9.541 ;
     RECT  32.592 6.229 35.304 9.731 ;
     RECT  36.672 9.061 36.792 9.827 ;
     RECT  16.08 9.491 22.776 10.067 ;
     RECT  32.592 9.731 35.256 10.213 ;
     RECT  16.08 10.067 22.44 10.307 ;
     RECT  0.144 8.917 0.552 10.643 ;
     RECT  2.4 9.541 14.808 10.787 ;
     RECT  26.16 9.155 26.184 10.789 ;
     RECT  0.192 10.643 0.552 10.931 ;
     RECT  2.4 10.787 10.92 11.125 ;
     RECT  32.256 10.213 35.256 11.459 ;
     RECT  27.84 8.437 29.712 11.651 ;
     RECT  0.192 10.931 0.216 11.749 ;
     RECT  26.016 10.789 26.184 11.845 ;
     RECT  0.144 11.749 0.216 11.989 ;
     RECT  24 8.195 24.792 12.035 ;
     RECT  2.304 11.125 10.92 12.131 ;
     RECT  2.304 12.131 3.384 12.275 ;
     RECT  25.776 11.845 26.184 12.469 ;
     RECT  32.592 11.459 35.256 12.517 ;
     RECT  16.08 10.307 22.2 12.563 ;
     RECT  28.896 11.651 29.712 12.563 ;
     RECT  30.816 11.941 30.84 12.563 ;
     RECT  0.144 11.989 0.264 12.757 ;
     RECT  16.08 12.563 21.48 13.379 ;
     RECT  0.144 12.757 0.552 13.427 ;
     RECT  2.304 12.275 2.952 13.475 ;
     RECT  4.368 12.131 10.92 13.621 ;
     RECT  0.24 13.427 0.552 13.667 ;
     RECT  2.304 13.475 2.712 13.667 ;
     RECT  0.528 13.667 0.552 13.955 ;
     RECT  29.4 12.563 29.712 13.957 ;
     RECT  3.936 13.621 10.92 14.197 ;
     RECT  11.904 10.787 14.808 14.197 ;
     RECT  3.936 14.197 14.808 14.291 ;
     RECT  25.488 12.469 26.184 14.339 ;
     RECT  2.4 13.667 2.712 14.725 ;
     RECT  4.368 14.291 14.808 14.819 ;
     RECT  25.488 14.339 26.04 14.867 ;
     RECT  32.592 12.517 35.352 15.061 ;
     RECT  4.368 14.819 14.52 15.347 ;
     RECT  24 12.035 24.312 15.445 ;
     RECT  31.872 15.061 35.352 15.445 ;
     RECT  25.488 14.867 25.8 15.491 ;
     RECT  29.4 13.957 29.832 15.491 ;
     RECT  27.84 11.651 27.864 15.589 ;
     RECT  29.4 15.491 29.712 15.589 ;
     RECT  4.368 15.347 8.76 15.637 ;
     RECT  31.872 15.445 35.736 15.925 ;
     RECT  17.28 13.379 21.48 16.019 ;
     RECT  4.32 15.637 8.76 16.163 ;
     RECT  20.976 16.019 21.48 16.405 ;
     RECT  22.512 15.349 22.536 16.405 ;
     RECT  24 15.445 24.456 16.405 ;
     RECT  17.28 16.019 19.896 16.595 ;
     RECT  27.84 15.589 29.712 16.595 ;
     RECT  20.976 16.405 22.536 16.883 ;
     RECT  2.4 14.725 2.856 16.979 ;
     RECT  20.976 16.883 21.576 17.029 ;
     RECT  31.344 15.925 35.736 17.123 ;
     RECT  4.32 16.163 4.344 17.315 ;
     RECT  5.712 16.163 8.76 17.509 ;
     RECT  27.84 16.595 27.864 17.605 ;
     RECT  24 16.405 24.504 18.181 ;
     RECT  25.488 15.491 25.752 18.181 ;
     RECT  16.08 13.379 16.248 18.229 ;
     RECT  27.84 17.605 28.392 18.275 ;
     RECT  10.128 15.347 14.52 18.515 ;
     RECT  0.144 18.421 0.168 18.563 ;
     RECT  22.56 18.037 22.584 18.755 ;
     RECT  10.128 18.515 14.28 18.851 ;
     RECT  15.984 18.229 16.248 18.851 ;
     RECT  24 18.181 25.752 18.851 ;
     RECT  10.128 18.851 14.136 19.187 ;
     RECT  16.032 18.851 16.248 19.187 ;
     RECT  17.28 16.595 18.912 19.237 ;
     RECT  16.224 19.187 16.248 19.333 ;
     RECT  17.28 19.237 19.032 19.333 ;
     RECT  20.064 17.029 21.576 19.379 ;
     RECT  24 18.851 24.504 19.813 ;
     RECT  31.872 17.123 35.736 19.861 ;
     RECT  28.368 18.275 28.392 19.909 ;
     RECT  29.4 16.595 29.712 19.909 ;
     RECT  31.728 19.861 35.736 19.909 ;
     RECT  36.768 9.827 36.792 19.909 ;
     RECT  20.064 19.379 21.48 20.147 ;
     RECT  16.224 19.333 19.032 20.339 ;
     RECT  11.904 19.187 14.136 20.341 ;
     RECT  31.728 19.909 36.792 20.437 ;
     RECT  11.904 20.341 14.952 20.819 ;
     RECT  20.064 20.147 21.384 21.637 ;
     RECT  28.368 19.909 29.712 21.683 ;
     RECT  17.28 20.339 19.032 21.877 ;
     RECT  20.064 21.637 21.48 21.877 ;
     RECT  17.28 21.877 21.48 22.019 ;
     RECT  29.4 21.683 29.712 22.117 ;
     RECT  16.224 20.339 16.248 22.165 ;
     RECT  24 19.813 24.744 22.213 ;
     RECT  25.728 18.851 25.752 22.213 ;
     RECT  10.128 19.187 10.92 22.693 ;
     RECT  11.904 20.819 14.136 22.693 ;
     RECT  5.28 17.509 8.76 22.741 ;
     RECT  10.128 22.693 14.136 22.741 ;
     RECT  16.224 22.165 16.296 22.741 ;
     RECT  24 22.213 25.752 22.979 ;
     RECT  29.4 22.117 29.832 22.979 ;
     RECT  16.128 22.741 16.296 22.981 ;
     RECT  15.312 22.981 16.296 23.267 ;
     RECT  25.728 22.979 25.752 23.317 ;
     RECT  5.28 22.741 14.136 23.555 ;
     RECT  17.28 22.019 19.032 23.555 ;
     RECT  5.28 23.555 10.92 23.699 ;
     RECT  31.344 20.437 36.792 23.843 ;
     RECT  11.904 23.555 14.136 23.845 ;
     RECT  25.728 23.317 26.52 24.131 ;
     RECT  20.064 22.019 21.48 24.133 ;
     RECT  22.704 23.893 22.728 24.181 ;
     RECT  24 22.979 24.312 24.181 ;
     RECT  11.904 23.845 14.232 24.469 ;
     RECT  15.312 23.267 16.248 24.469 ;
     RECT  11.904 24.469 16.248 24.611 ;
     RECT  6.912 23.699 10.92 24.901 ;
     RECT  11.904 24.611 15.336 24.901 ;
     RECT  6.912 24.901 15.336 25.187 ;
     RECT  17.28 23.555 18.912 25.333 ;
     RECT  15.312 25.187 15.336 25.427 ;
     RECT  0.144 25.237 0.168 25.669 ;
     RECT  5.28 23.699 5.736 25.715 ;
     RECT  28.368 21.683 28.392 25.715 ;
     RECT  0.144 25.669 0.216 25.907 ;
     RECT  16.32 25.333 18.912 26.003 ;
     RECT  0.144 25.907 0.168 26.099 ;
     RECT  5.712 25.715 5.736 26.197 ;
     RECT  6.912 25.187 10.92 26.197 ;
     RECT  5.712 26.197 10.92 26.243 ;
     RECT  16.32 26.003 16.344 26.243 ;
     RECT  31.728 23.843 36.792 26.243 ;
     RECT  20.064 24.133 21.672 26.533 ;
     RECT  20.016 26.533 21.672 26.675 ;
     RECT  31.728 26.243 33.624 26.723 ;
     RECT  25.728 24.131 25.752 26.771 ;
     RECT  11.904 25.187 14.136 26.819 ;
     RECT  31.728 26.723 33.576 26.819 ;
     RECT  34.704 26.243 36.792 26.819 ;
     RECT  22.704 24.181 24.312 27.301 ;
     RECT  5.712 26.243 8.76 27.395 ;
     RECT  17.808 26.003 18.912 27.395 ;
     RECT  20.976 26.675 21.48 27.395 ;
     RECT  28.032 26.629 28.056 27.395 ;
     RECT  34.704 26.819 36.36 27.779 ;
     RECT  4.512 27.253 4.536 27.827 ;
     RECT  2.4 16.979 2.712 27.829 ;
     RECT  27.984 27.781 28.008 27.829 ;
     RECT  22.704 27.301 25.176 27.875 ;
     RECT  11.904 26.819 14.088 27.923 ;
     RECT  2.4 27.829 2.856 27.971 ;
     RECT  21.216 27.395 21.48 27.971 ;
     RECT  31.728 26.819 33.288 27.971 ;
     RECT  34.8 27.779 36.36 27.971 ;
     RECT  23.328 27.875 25.176 28.115 ;
     RECT  29.4 22.979 29.712 28.261 ;
     RECT  30.72 27.301 30.744 28.261 ;
     RECT  29.4 28.261 30.744 28.307 ;
     RECT  0.144 28.213 0.168 28.451 ;
     RECT  24 28.115 25.176 28.451 ;
     RECT  27.264 27.829 28.008 28.453 ;
     RECT  29.4 28.307 30.264 28.453 ;
     RECT  24 28.451 24.552 28.931 ;
     RECT  27.264 28.453 30.264 28.931 ;
     RECT  27.984 28.931 30.264 28.979 ;
     RECT  18.6 27.395 18.912 29.029 ;
     RECT  21.36 27.971 21.48 29.029 ;
     RECT  21.12 29.029 21.48 29.075 ;
     RECT  10.128 26.243 10.92 29.123 ;
     RECT  28.848 28.979 30.264 29.267 ;
     RECT  31.728 27.971 33.144 29.363 ;
     RECT  16.656 27.877 16.68 29.365 ;
     RECT  24 28.931 24.312 29.365 ;
     RECT  16.56 29.365 16.68 29.653 ;
     RECT  18.6 29.029 19.896 29.699 ;
     RECT  32.832 29.363 33.144 29.699 ;
     RECT  21.12 29.075 21.144 29.987 ;
     RECT  5.712 27.395 8.112 30.037 ;
     RECT  23.376 29.365 24.312 30.083 ;
     RECT  15.36 29.029 15.384 30.131 ;
     RECT  16.56 29.653 17.16 30.131 ;
     RECT  11.904 27.923 13.896 30.275 ;
     RECT  33.12 29.699 33.144 30.371 ;
     RECT  2.4 27.971 2.712 30.421 ;
     RECT  24 30.083 24.312 30.469 ;
     RECT  2.304 30.421 2.712 30.611 ;
     RECT  29.4 29.267 30.264 30.611 ;
     RECT  10.752 29.123 10.92 30.757 ;
     RECT  11.904 30.275 13.704 30.757 ;
     RECT  17.136 30.131 17.16 30.851 ;
     RECT  18.6 29.699 19.032 30.851 ;
     RECT  34.8 27.971 35.352 30.947 ;
     RECT  5.712 30.037 8.856 31.379 ;
     RECT  31.728 29.363 31.752 31.379 ;
     RECT  24 30.469 24.552 31.669 ;
     RECT  25.632 28.933 25.656 31.669 ;
     RECT  29.4 30.611 29.712 31.669 ;
     RECT  10.752 30.757 13.704 31.715 ;
     RECT  26.736 31.861 26.76 32.195 ;
     RECT  11.904 31.715 13.704 32.531 ;
     RECT  34.8 30.947 35.112 32.821 ;
     RECT  24 31.669 25.656 32.963 ;
     RECT  36.336 27.971 36.36 33.107 ;
     RECT  32.112 32.965 32.136 33.541 ;
     RECT  6 31.379 8.856 33.589 ;
     RECT  34.8 32.821 35.208 33.635 ;
     RECT  6 33.589 9.096 33.683 ;
     RECT  29.28 31.669 29.712 33.683 ;
     RECT  10.752 31.715 10.92 34.069 ;
     RECT  11.904 32.531 13.656 34.069 ;
     RECT  32.112 33.541 32.856 34.115 ;
     RECT  32.112 34.115 32.136 34.213 ;
     RECT  6.912 33.683 9.096 34.259 ;
     RECT  20.304 31.189 20.328 34.259 ;
     RECT  31.92 34.213 32.136 34.259 ;
     RECT  31.92 34.259 31.944 34.499 ;
     RECT  25.632 32.963 25.656 34.595 ;
     RECT  27.888 33.253 27.912 34.595 ;
     RECT  10.752 34.069 13.656 34.741 ;
     RECT  24 32.963 24.312 34.741 ;
     RECT  10.608 34.741 13.656 34.883 ;
     RECT  34.8 33.635 35.112 35.269 ;
     RECT  10.752 34.883 13.656 35.363 ;
     RECT  21.792 33.541 21.816 35.363 ;
     RECT  24 34.741 24.408 35.459 ;
     RECT  34.176 35.269 35.112 35.987 ;
     RECT  6.912 34.259 8.112 36.515 ;
     RECT  10.752 35.363 13.512 36.997 ;
     RECT  7.248 36.515 8.112 37.859 ;
     RECT  10.752 36.997 13.704 38.675 ;
     RECT  29.4 33.683 29.712 38.821 ;
     RECT  30.768 38.725 30.792 38.821 ;
     RECT  29.4 38.821 30.792 38.867 ;
     RECT  10.752 38.675 13.512 38.963 ;
     RECT  29.4 38.867 30.696 39.395 ;
     RECT  12.528 38.963 13.512 40.499 ;
     RECT  7.8 37.859 8.112 40.741 ;
     RECT  6.816 40.741 8.112 40.931 ;
     RECT  2.4 30.611 2.712 41.049 ;
     RECT  7.8 40.931 8.112 41.049 ;
     RECT  13.2 40.499 13.512 41.049 ;
     RECT  18.6 30.851 18.912 41.049 ;
     RECT  24 35.459 24.312 41.049 ;
     RECT  29.4 39.395 29.712 41.049 ;
     RECT  34.8 35.987 35.112 41.049 ;
     RECT  2.4 41.049 2.52 41.063 ;
     RECT  7.8 41.049 7.92 41.063 ;
     RECT  13.2 41.049 13.32 41.063 ;
     RECT  18.6 41.049 18.72 41.063 ;
     RECT  24 41.049 24.12 41.063 ;
     RECT  29.4 41.049 29.52 41.063 ;
     RECT  34.8 41.049 34.92 41.063 ;
     RECT  10.752 38.963 10.776 43.152 ;
     RECT  30.288 43.045 30.312 43.152 ;
  END
END qkd_ctrl_pc_ecc_child_sl
END LIBRARY
